VERSION 5.8 ;
BUSBITCHARS "[]" ;
DIVIDERCHAR "/" ;

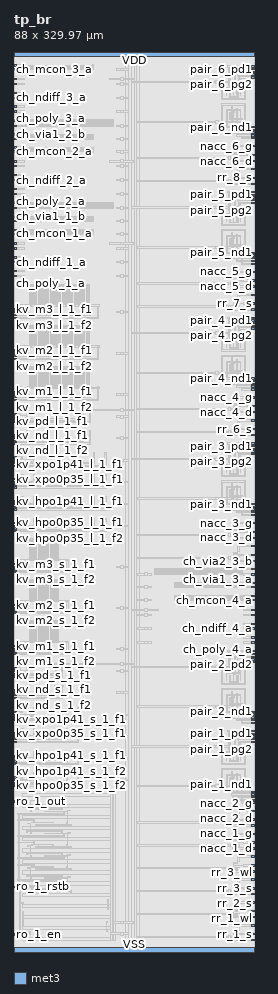
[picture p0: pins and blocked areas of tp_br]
MACRO tp_br
  CLASS BLOCK ;
  FOREIGN tp_br 0 0 ;
  ORIGIN 0 0 ;
  SIZE 88.000 BY 329.970 ;
  SYMMETRY X Y ;
  PIN VDD
    DIRECTION INOUT ;
    USE POWER ;
    PORT
      LAYER met3 ;
        RECT 0.000 328.370 88.000 329.970 ;
    END
  END VDD
  PIN VSS
    DIRECTION INOUT ;
    USE GROUND ;
    PORT
      LAYER met3 ;
        RECT 0.000 0.000 88.000 1.600 ;
    END
  END VSS
  PIN ch_mcon_1_a
    DIRECTION INOUT ;
    USE SIGNAL ;
    PORT
      LAYER met3 ;
        RECT 0.000 263.030 1.000 263.530 ;
    END
  END ch_mcon_1_a
  PIN ch_mcon_1_b
    DIRECTION INOUT ;
    USE SIGNAL ;
    PORT
      LAYER met3 ;
        RECT 0.000 264.530 1.000 265.030 ;
    END
  END ch_mcon_1_b
  PIN ch_mcon_2_a
    DIRECTION INOUT ;
    USE SIGNAL ;
    PORT
      LAYER met3 ;
        RECT 0.000 293.180 1.000 293.680 ;
    END
  END ch_mcon_2_a
  PIN ch_mcon_2_b
    DIRECTION INOUT ;
    USE SIGNAL ;
    PORT
      LAYER met3 ;
        RECT 0.000 294.680 1.000 295.180 ;
    END
  END ch_mcon_2_b
  PIN ch_mcon_3_a
    DIRECTION INOUT ;
    USE SIGNAL ;
    PORT
      LAYER met3 ;
        RECT 0.000 323.330 1.000 323.830 ;
    END
  END ch_mcon_3_a
  PIN ch_mcon_3_b
    DIRECTION INOUT ;
    USE SIGNAL ;
    PORT
      LAYER met3 ;
        RECT 0.000 324.830 1.000 325.330 ;
    END
  END ch_mcon_3_b
  PIN ch_mcon_4_a
    DIRECTION INOUT ;
    USE SIGNAL ;
    PORT
      LAYER met3 ;
        RECT 87.000 128.720 88.000 129.220 ;
    END
  END ch_mcon_4_a
  PIN ch_mcon_4_b
    DIRECTION INOUT ;
    USE SIGNAL ;
    PORT
      LAYER met3 ;
        RECT 87.000 130.220 88.000 130.720 ;
    END
  END ch_mcon_4_b
  PIN ch_ndiff_1_a
    DIRECTION INOUT ;
    USE SIGNAL ;
    PORT
      LAYER met3 ;
        RECT 0.000 252.630 1.000 253.130 ;
    END
  END ch_ndiff_1_a
  PIN ch_ndiff_1_b
    DIRECTION INOUT ;
    USE SIGNAL ;
    PORT
      LAYER met3 ;
        RECT 0.000 254.430 1.000 254.930 ;
    END
  END ch_ndiff_1_b
  PIN ch_ndiff_2_a
    DIRECTION INOUT ;
    USE SIGNAL ;
    PORT
      LAYER met3 ;
        RECT 0.000 282.780 1.000 283.280 ;
    END
  END ch_ndiff_2_a
  PIN ch_ndiff_2_b
    DIRECTION INOUT ;
    USE SIGNAL ;
    PORT
      LAYER met3 ;
        RECT 0.000 284.580 1.000 285.080 ;
    END
  END ch_ndiff_2_b
  PIN ch_ndiff_3_a
    DIRECTION INOUT ;
    USE SIGNAL ;
    PORT
      LAYER met3 ;
        RECT 0.000 312.930 1.000 313.430 ;
    END
  END ch_ndiff_3_a
  PIN ch_ndiff_3_b
    DIRECTION INOUT ;
    USE SIGNAL ;
    PORT
      LAYER met3 ;
        RECT 0.000 314.730 1.000 315.230 ;
    END
  END ch_ndiff_3_b
  PIN ch_ndiff_4_a
    DIRECTION INOUT ;
    USE SIGNAL ;
    PORT
      LAYER met3 ;
        RECT 87.000 118.320 88.000 118.820 ;
    END
  END ch_ndiff_4_a
  PIN ch_ndiff_4_b
    DIRECTION INOUT ;
    USE SIGNAL ;
    PORT
      LAYER met3 ;
        RECT 87.000 120.120 88.000 120.620 ;
    END
  END ch_ndiff_4_b
  PIN ch_pdiff_1_a
    DIRECTION INOUT ;
    USE SIGNAL ;
    PORT
      LAYER met3 ;
        RECT 0.000 257.680 1.000 258.180 ;
    END
  END ch_pdiff_1_a
  PIN ch_pdiff_1_b
    DIRECTION INOUT ;
    USE SIGNAL ;
    PORT
      LAYER met3 ;
        RECT 0.000 259.480 1.000 259.980 ;
    END
  END ch_pdiff_1_b
  PIN ch_pdiff_2_a
    DIRECTION INOUT ;
    USE SIGNAL ;
    PORT
      LAYER met3 ;
        RECT 0.000 287.830 1.000 288.330 ;
    END
  END ch_pdiff_2_a
  PIN ch_pdiff_2_b
    DIRECTION INOUT ;
    USE SIGNAL ;
    PORT
      LAYER met3 ;
        RECT 0.000 289.630 1.000 290.130 ;
    END
  END ch_pdiff_2_b
  PIN ch_pdiff_3_a
    DIRECTION INOUT ;
    USE SIGNAL ;
    PORT
      LAYER met3 ;
        RECT 0.000 317.980 1.000 318.480 ;
    END
  END ch_pdiff_3_a
  PIN ch_pdiff_3_b
    DIRECTION INOUT ;
    USE SIGNAL ;
    PORT
      LAYER met3 ;
        RECT 0.000 319.780 1.000 320.280 ;
    END
  END ch_pdiff_3_b
  PIN ch_pdiff_4_a
    DIRECTION INOUT ;
    USE SIGNAL ;
    PORT
      LAYER met3 ;
        RECT 87.000 123.370 88.000 123.870 ;
    END
  END ch_pdiff_4_a
  PIN ch_pdiff_4_b
    DIRECTION INOUT ;
    USE SIGNAL ;
    PORT
      LAYER met3 ;
        RECT 87.000 125.170 88.000 125.670 ;
    END
  END ch_pdiff_4_b
  PIN ch_poly_1_a
    DIRECTION INOUT ;
    USE SIGNAL ;
    PORT
      LAYER met3 ;
        RECT 0.000 247.580 1.000 248.080 ;
    END
  END ch_poly_1_a
  PIN ch_poly_1_b
    DIRECTION INOUT ;
    USE SIGNAL ;
    PORT
      LAYER met3 ;
        RECT 0.000 249.380 1.000 249.880 ;
    END
  END ch_poly_1_b
  PIN ch_poly_2_a
    DIRECTION INOUT ;
    USE SIGNAL ;
    PORT
      LAYER met3 ;
        RECT 0.000 277.730 1.000 278.230 ;
    END
  END ch_poly_2_a
  PIN ch_poly_2_b
    DIRECTION INOUT ;
    USE SIGNAL ;
    PORT
      LAYER met3 ;
        RECT 0.000 279.530 1.000 280.030 ;
    END
  END ch_poly_2_b
  PIN ch_poly_3_a
    DIRECTION INOUT ;
    USE SIGNAL ;
    PORT
      LAYER met3 ;
        RECT 0.000 307.880 1.000 308.380 ;
    END
  END ch_poly_3_a
  PIN ch_poly_3_b
    DIRECTION INOUT ;
    USE SIGNAL ;
    PORT
      LAYER met3 ;
        RECT 0.000 309.680 1.000 310.180 ;
    END
  END ch_poly_3_b
  PIN ch_poly_4_a
    DIRECTION INOUT ;
    USE SIGNAL ;
    PORT
      LAYER met3 ;
        RECT 87.000 113.270 88.000 113.770 ;
    END
  END ch_poly_4_a
  PIN ch_poly_4_b
    DIRECTION INOUT ;
    USE SIGNAL ;
    PORT
      LAYER met3 ;
        RECT 87.000 115.070 88.000 115.570 ;
    END
  END ch_poly_4_b
  PIN ch_via1_1_a
    DIRECTION INOUT ;
    USE SIGNAL ;
    PORT
      LAYER met3 ;
        RECT 0.000 267.780 1.000 268.280 ;
    END
  END ch_via1_1_a
  PIN ch_via1_1_b
    DIRECTION INOUT ;
    USE SIGNAL ;
    PORT
      LAYER met3 ;
        RECT 0.000 269.280 1.000 269.780 ;
    END
  END ch_via1_1_b
  PIN ch_via1_2_a
    DIRECTION INOUT ;
    USE SIGNAL ;
    PORT
      LAYER met3 ;
        RECT 0.000 297.930 1.000 298.430 ;
    END
  END ch_via1_2_a
  PIN ch_via1_2_b
    DIRECTION INOUT ;
    USE SIGNAL ;
    PORT
      LAYER met3 ;
        RECT 0.000 299.430 1.000 299.930 ;
    END
  END ch_via1_2_b
  PIN ch_via1_3_a
    DIRECTION INOUT ;
    USE SIGNAL ;
    PORT
      LAYER met3 ;
        RECT 87.000 133.470 88.000 133.970 ;
    END
  END ch_via1_3_a
  PIN ch_via1_3_b
    DIRECTION INOUT ;
    USE SIGNAL ;
    PORT
      LAYER met3 ;
        RECT 87.000 134.970 88.000 135.470 ;
    END
  END ch_via1_3_b
  PIN ch_via2_1_a
    DIRECTION INOUT ;
    USE SIGNAL ;
    PORT
      LAYER met3 ;
        RECT 0.000 272.530 1.000 273.030 ;
    END
  END ch_via2_1_a
  PIN ch_via2_1_b
    DIRECTION INOUT ;
    USE SIGNAL ;
    PORT
      LAYER met3 ;
        RECT 0.000 274.480 1.000 274.980 ;
    END
  END ch_via2_1_b
  PIN ch_via2_2_a
    DIRECTION INOUT ;
    USE SIGNAL ;
    PORT
      LAYER met3 ;
        RECT 0.000 302.680 1.000 303.180 ;
    END
  END ch_via2_2_a
  PIN ch_via2_2_b
    DIRECTION INOUT ;
    USE SIGNAL ;
    PORT
      LAYER met3 ;
        RECT 0.000 304.630 1.000 305.130 ;
    END
  END ch_via2_2_b
  PIN ch_via2_3_a
    DIRECTION INOUT ;
    USE SIGNAL ;
    PORT
      LAYER met3 ;
        RECT 87.000 138.220 88.000 138.720 ;
    END
  END ch_via2_3_a
  PIN ch_via2_3_b
    DIRECTION INOUT ;
    USE SIGNAL ;
    PORT
      LAYER met3 ;
        RECT 87.000 140.170 88.000 140.670 ;
    END
  END ch_via2_3_b
  PIN kv_hpo0p35_l_1_f1
    DIRECTION INOUT ;
    USE SIGNAL ;
    PORT
      LAYER met3 ;
        RECT 0.000 157.045 1.000 157.545 ;
    END
  END kv_hpo0p35_l_1_f1
  PIN kv_hpo0p35_l_1_f2
    DIRECTION INOUT ;
    USE SIGNAL ;
    PORT
      LAYER met3 ;
        RECT 0.000 154.045 1.000 154.545 ;
    END
  END kv_hpo0p35_l_1_f2
  PIN kv_hpo0p35_l_1_s1
    DIRECTION INOUT ;
    USE SIGNAL ;
    PORT
      LAYER met3 ;
        RECT 0.000 156.045 1.000 156.545 ;
    END
  END kv_hpo0p35_l_1_s1
  PIN kv_hpo0p35_l_1_s2
    DIRECTION INOUT ;
    USE SIGNAL ;
    PORT
      LAYER met3 ;
        RECT 0.000 155.045 1.000 155.545 ;
    END
  END kv_hpo0p35_l_1_s2
  PIN kv_hpo0p35_s_1_f1
    DIRECTION INOUT ;
    USE SIGNAL ;
    PORT
      LAYER met3 ;
        RECT 0.000 63.760 1.000 64.260 ;
    END
  END kv_hpo0p35_s_1_f1
  PIN kv_hpo0p35_s_1_f2
    DIRECTION INOUT ;
    USE SIGNAL ;
    PORT
      LAYER met3 ;
        RECT 0.000 60.760 1.000 61.260 ;
    END
  END kv_hpo0p35_s_1_f2
  PIN kv_hpo0p35_s_1_s1
    DIRECTION INOUT ;
    USE SIGNAL ;
    PORT
      LAYER met3 ;
        RECT 0.000 62.760 1.000 63.260 ;
    END
  END kv_hpo0p35_s_1_s1
  PIN kv_hpo0p35_s_1_s2
    DIRECTION INOUT ;
    USE SIGNAL ;
    PORT
      LAYER met3 ;
        RECT 0.000 61.760 1.000 62.260 ;
    END
  END kv_hpo0p35_s_1_s2
  PIN kv_hpo1p41_l_1_f1
    DIRECTION INOUT ;
    USE SIGNAL ;
    PORT
      LAYER met3 ;
        RECT 0.000 164.945 1.000 165.445 ;
    END
  END kv_hpo1p41_l_1_f1
  PIN kv_hpo1p41_l_1_f2
    DIRECTION INOUT ;
    USE SIGNAL ;
    PORT
      LAYER met3 ;
        RECT 0.000 161.945 1.000 162.445 ;
    END
  END kv_hpo1p41_l_1_f2
  PIN kv_hpo1p41_l_1_s1
    DIRECTION INOUT ;
    USE SIGNAL ;
    PORT
      LAYER met3 ;
        RECT 0.000 163.945 1.000 164.445 ;
    END
  END kv_hpo1p41_l_1_s1
  PIN kv_hpo1p41_l_1_s2
    DIRECTION INOUT ;
    USE SIGNAL ;
    PORT
      LAYER met3 ;
        RECT 0.000 162.945 1.000 163.445 ;
    END
  END kv_hpo1p41_l_1_s2
  PIN kv_hpo1p41_s_1_f1
    DIRECTION INOUT ;
    USE SIGNAL ;
    PORT
      LAYER met3 ;
        RECT 0.000 71.660 1.000 72.160 ;
    END
  END kv_hpo1p41_s_1_f1
  PIN kv_hpo1p41_s_1_f2
    DIRECTION INOUT ;
    USE SIGNAL ;
    PORT
      LAYER met3 ;
        RECT 0.000 68.660 1.000 69.160 ;
    END
  END kv_hpo1p41_s_1_f2
  PIN kv_hpo1p41_s_1_s1
    DIRECTION INOUT ;
    USE SIGNAL ;
    PORT
      LAYER met3 ;
        RECT 0.000 70.660 1.000 71.160 ;
    END
  END kv_hpo1p41_s_1_s1
  PIN kv_hpo1p41_s_1_s2
    DIRECTION INOUT ;
    USE SIGNAL ;
    PORT
      LAYER met3 ;
        RECT 0.000 69.660 1.000 70.160 ;
    END
  END kv_hpo1p41_s_1_s2
  PIN kv_m1_l_1_f1
    DIRECTION INOUT ;
    USE SIGNAL ;
    PORT
      LAYER met3 ;
        RECT 0.000 205.180 1.000 205.680 ;
    END
  END kv_m1_l_1_f1
  PIN kv_m1_l_1_f2
    DIRECTION INOUT ;
    USE SIGNAL ;
    PORT
      LAYER met3 ;
        RECT 0.000 202.180 1.000 202.680 ;
    END
  END kv_m1_l_1_f2
  PIN kv_m1_l_1_s1
    DIRECTION INOUT ;
    USE SIGNAL ;
    PORT
      LAYER met3 ;
        RECT 0.000 204.180 1.000 204.680 ;
    END
  END kv_m1_l_1_s1
  PIN kv_m1_l_1_s2
    DIRECTION INOUT ;
    USE SIGNAL ;
    PORT
      LAYER met3 ;
        RECT 0.000 203.180 1.000 203.680 ;
    END
  END kv_m1_l_1_s2
  PIN kv_m1_s_1_f1
    DIRECTION INOUT ;
    USE SIGNAL ;
    PORT
      LAYER met3 ;
        RECT 0.000 111.895 1.000 112.395 ;
    END
  END kv_m1_s_1_f1
  PIN kv_m1_s_1_f2
    DIRECTION INOUT ;
    USE SIGNAL ;
    PORT
      LAYER met3 ;
        RECT 0.000 108.895 1.000 109.395 ;
    END
  END kv_m1_s_1_f2
  PIN kv_m1_s_1_s1
    DIRECTION INOUT ;
    USE SIGNAL ;
    PORT
      LAYER met3 ;
        RECT 0.000 110.895 1.000 111.395 ;
    END
  END kv_m1_s_1_s1
  PIN kv_m1_s_1_s2
    DIRECTION INOUT ;
    USE SIGNAL ;
    PORT
      LAYER met3 ;
        RECT 0.000 109.895 1.000 110.395 ;
    END
  END kv_m1_s_1_s2
  PIN kv_m2_l_1_f1
    DIRECTION INOUT ;
    USE SIGNAL ;
    PORT
      LAYER met3 ;
        RECT 0.000 220.230 1.000 220.730 ;
    END
  END kv_m2_l_1_f1
  PIN kv_m2_l_1_f2
    DIRECTION INOUT ;
    USE SIGNAL ;
    PORT
      LAYER met3 ;
        RECT 0.000 217.230 1.000 217.730 ;
    END
  END kv_m2_l_1_f2
  PIN kv_m2_l_1_s1
    DIRECTION INOUT ;
    USE SIGNAL ;
    PORT
      LAYER met3 ;
        RECT 0.000 219.230 1.000 219.730 ;
    END
  END kv_m2_l_1_s1
  PIN kv_m2_l_1_s2
    DIRECTION INOUT ;
    USE SIGNAL ;
    PORT
      LAYER met3 ;
        RECT 0.000 218.230 1.000 218.730 ;
    END
  END kv_m2_l_1_s2
  PIN kv_m2_s_1_f1
    DIRECTION INOUT ;
    USE SIGNAL ;
    PORT
      LAYER met3 ;
        RECT 0.000 126.945 1.000 127.445 ;
    END
  END kv_m2_s_1_f1
  PIN kv_m2_s_1_f2
    DIRECTION INOUT ;
    USE SIGNAL ;
    PORT
      LAYER met3 ;
        RECT 0.000 123.945 1.000 124.445 ;
    END
  END kv_m2_s_1_f2
  PIN kv_m2_s_1_s1
    DIRECTION INOUT ;
    USE SIGNAL ;
    PORT
      LAYER met3 ;
        RECT 0.000 125.945 1.000 126.445 ;
    END
  END kv_m2_s_1_s1
  PIN kv_m2_s_1_s2
    DIRECTION INOUT ;
    USE SIGNAL ;
    PORT
      LAYER met3 ;
        RECT 0.000 124.945 1.000 125.445 ;
    END
  END kv_m2_s_1_s2
  PIN kv_m3_l_1_f1
    DIRECTION INOUT ;
    USE SIGNAL ;
    PORT
      LAYER met3 ;
        RECT 0.000 235.280 1.000 235.780 ;
    END
  END kv_m3_l_1_f1
  PIN kv_m3_l_1_f2
    DIRECTION INOUT ;
    USE SIGNAL ;
    PORT
      LAYER met3 ;
        RECT 0.000 232.280 1.000 232.780 ;
    END
  END kv_m3_l_1_f2
  PIN kv_m3_l_1_s1
    DIRECTION INOUT ;
    USE SIGNAL ;
    PORT
      LAYER met3 ;
        RECT 0.000 234.280 1.000 234.780 ;
    END
  END kv_m3_l_1_s1
  PIN kv_m3_l_1_s2
    DIRECTION INOUT ;
    USE SIGNAL ;
    PORT
      LAYER met3 ;
        RECT 0.000 233.280 1.000 233.780 ;
    END
  END kv_m3_l_1_s2
  PIN kv_m3_s_1_f1
    DIRECTION INOUT ;
    USE SIGNAL ;
    PORT
      LAYER met3 ;
        RECT 0.000 141.995 1.000 142.495 ;
    END
  END kv_m3_s_1_f1
  PIN kv_m3_s_1_f2
    DIRECTION INOUT ;
    USE SIGNAL ;
    PORT
      LAYER met3 ;
        RECT 0.000 138.995 1.000 139.495 ;
    END
  END kv_m3_s_1_f2
  PIN kv_m3_s_1_s1
    DIRECTION INOUT ;
    USE SIGNAL ;
    PORT
      LAYER met3 ;
        RECT 0.000 140.995 1.000 141.495 ;
    END
  END kv_m3_s_1_s1
  PIN kv_m3_s_1_s2
    DIRECTION INOUT ;
    USE SIGNAL ;
    PORT
      LAYER met3 ;
        RECT 0.000 139.995 1.000 140.495 ;
    END
  END kv_m3_s_1_s2
  PIN kv_nd_l_1_f1
    DIRECTION INOUT ;
    USE SIGNAL ;
    PORT
      LAYER met3 ;
        RECT 0.000 189.155 1.000 189.655 ;
    END
  END kv_nd_l_1_f1
  PIN kv_nd_l_1_f2
    DIRECTION INOUT ;
    USE SIGNAL ;
    PORT
      LAYER met3 ;
        RECT 0.000 186.155 1.000 186.655 ;
    END
  END kv_nd_l_1_f2
  PIN kv_nd_l_1_s1
    DIRECTION INOUT ;
    USE SIGNAL ;
    PORT
      LAYER met3 ;
        RECT 0.000 188.155 1.000 188.655 ;
    END
  END kv_nd_l_1_s1
  PIN kv_nd_l_1_s2
    DIRECTION INOUT ;
    USE SIGNAL ;
    PORT
      LAYER met3 ;
        RECT 0.000 187.155 1.000 187.655 ;
    END
  END kv_nd_l_1_s2
  PIN kv_nd_s_1_f1
    DIRECTION INOUT ;
    USE SIGNAL ;
    PORT
      LAYER met3 ;
        RECT 0.000 95.870 1.000 96.370 ;
    END
  END kv_nd_s_1_f1
  PIN kv_nd_s_1_f2
    DIRECTION INOUT ;
    USE SIGNAL ;
    PORT
      LAYER met3 ;
        RECT 0.000 92.870 1.000 93.370 ;
    END
  END kv_nd_s_1_f2
  PIN kv_nd_s_1_s1
    DIRECTION INOUT ;
    USE SIGNAL ;
    PORT
      LAYER met3 ;
        RECT 0.000 94.870 1.000 95.370 ;
    END
  END kv_nd_s_1_s1
  PIN kv_nd_s_1_s2
    DIRECTION INOUT ;
    USE SIGNAL ;
    PORT
      LAYER met3 ;
        RECT 0.000 93.870 1.000 94.370 ;
    END
  END kv_nd_s_1_s2
  PIN kv_pd_l_1_f1
    DIRECTION INOUT ;
    USE SIGNAL ;
    PORT
      LAYER met3 ;
        RECT 0.000 197.030 1.000 197.530 ;
    END
  END kv_pd_l_1_f1
  PIN kv_pd_l_1_f2
    DIRECTION INOUT ;
    USE SIGNAL ;
    PORT
      LAYER met3 ;
        RECT 0.000 194.030 1.000 194.530 ;
    END
  END kv_pd_l_1_f2
  PIN kv_pd_l_1_s1
    DIRECTION INOUT ;
    USE SIGNAL ;
    PORT
      LAYER met3 ;
        RECT 0.000 196.030 1.000 196.530 ;
    END
  END kv_pd_l_1_s1
  PIN kv_pd_l_1_s2
    DIRECTION INOUT ;
    USE SIGNAL ;
    PORT
      LAYER met3 ;
        RECT 0.000 195.030 1.000 195.530 ;
    END
  END kv_pd_l_1_s2
  PIN kv_pd_s_1_f1
    DIRECTION INOUT ;
    USE SIGNAL ;
    PORT
      LAYER met3 ;
        RECT 0.000 103.745 1.000 104.245 ;
    END
  END kv_pd_s_1_f1
  PIN kv_pd_s_1_f2
    DIRECTION INOUT ;
    USE SIGNAL ;
    PORT
      LAYER met3 ;
        RECT 0.000 100.745 1.000 101.245 ;
    END
  END kv_pd_s_1_f2
  PIN kv_pd_s_1_s1
    DIRECTION INOUT ;
    USE SIGNAL ;
    PORT
      LAYER met3 ;
        RECT 0.000 102.745 1.000 103.245 ;
    END
  END kv_pd_s_1_s1
  PIN kv_pd_s_1_s2
    DIRECTION INOUT ;
    USE SIGNAL ;
    PORT
      LAYER met3 ;
        RECT 0.000 101.745 1.000 102.245 ;
    END
  END kv_pd_s_1_s2
  PIN kv_xpo0p35_l_1_f1
    DIRECTION INOUT ;
    USE SIGNAL ;
    PORT
      LAYER met3 ;
        RECT 0.000 173.100 1.000 173.600 ;
    END
  END kv_xpo0p35_l_1_f1
  PIN kv_xpo0p35_l_1_f2
    DIRECTION INOUT ;
    USE SIGNAL ;
    PORT
      LAYER met3 ;
        RECT 0.000 170.100 1.000 170.600 ;
    END
  END kv_xpo0p35_l_1_f2
  PIN kv_xpo0p35_l_1_s1
    DIRECTION INOUT ;
    USE SIGNAL ;
    PORT
      LAYER met3 ;
        RECT 0.000 172.100 1.000 172.600 ;
    END
  END kv_xpo0p35_l_1_s1
  PIN kv_xpo0p35_l_1_s2
    DIRECTION INOUT ;
    USE SIGNAL ;
    PORT
      LAYER met3 ;
        RECT 0.000 171.100 1.000 171.600 ;
    END
  END kv_xpo0p35_l_1_s2
  PIN kv_xpo0p35_s_1_f1
    DIRECTION INOUT ;
    USE SIGNAL ;
    PORT
      LAYER met3 ;
        RECT 0.000 79.815 1.000 80.315 ;
    END
  END kv_xpo0p35_s_1_f1
  PIN kv_xpo0p35_s_1_f2
    DIRECTION INOUT ;
    USE SIGNAL ;
    PORT
      LAYER met3 ;
        RECT 0.000 76.815 1.000 77.315 ;
    END
  END kv_xpo0p35_s_1_f2
  PIN kv_xpo0p35_s_1_s1
    DIRECTION INOUT ;
    USE SIGNAL ;
    PORT
      LAYER met3 ;
        RECT 0.000 78.815 1.000 79.315 ;
    END
  END kv_xpo0p35_s_1_s1
  PIN kv_xpo0p35_s_1_s2
    DIRECTION INOUT ;
    USE SIGNAL ;
    PORT
      LAYER met3 ;
        RECT 0.000 77.815 1.000 78.315 ;
    END
  END kv_xpo0p35_s_1_s2
  PIN kv_xpo1p41_l_1_f1
    DIRECTION INOUT ;
    USE SIGNAL ;
    PORT
      LAYER met3 ;
        RECT 0.000 181.000 1.000 181.500 ;
    END
  END kv_xpo1p41_l_1_f1
  PIN kv_xpo1p41_l_1_f2
    DIRECTION INOUT ;
    USE SIGNAL ;
    PORT
      LAYER met3 ;
        RECT 0.000 178.000 1.000 178.500 ;
    END
  END kv_xpo1p41_l_1_f2
  PIN kv_xpo1p41_l_1_s1
    DIRECTION INOUT ;
    USE SIGNAL ;
    PORT
      LAYER met3 ;
        RECT 0.000 180.000 1.000 180.500 ;
    END
  END kv_xpo1p41_l_1_s1
  PIN kv_xpo1p41_l_1_s2
    DIRECTION INOUT ;
    USE SIGNAL ;
    PORT
      LAYER met3 ;
        RECT 0.000 179.000 1.000 179.500 ;
    END
  END kv_xpo1p41_l_1_s2
  PIN kv_xpo1p41_s_1_f1
    DIRECTION INOUT ;
    USE SIGNAL ;
    PORT
      LAYER met3 ;
        RECT 0.000 87.715 1.000 88.215 ;
    END
  END kv_xpo1p41_s_1_f1
  PIN kv_xpo1p41_s_1_f2
    DIRECTION INOUT ;
    USE SIGNAL ;
    PORT
      LAYER met3 ;
        RECT 0.000 84.715 1.000 85.215 ;
    END
  END kv_xpo1p41_s_1_f2
  PIN kv_xpo1p41_s_1_s1
    DIRECTION INOUT ;
    USE SIGNAL ;
    PORT
      LAYER met3 ;
        RECT 0.000 86.715 1.000 87.215 ;
    END
  END kv_xpo1p41_s_1_s1
  PIN kv_xpo1p41_s_1_s2
    DIRECTION INOUT ;
    USE SIGNAL ;
    PORT
      LAYER met3 ;
        RECT 0.000 85.715 1.000 86.215 ;
    END
  END kv_xpo1p41_s_1_s2
  PIN nacc_1_d
    DIRECTION INOUT ;
    USE SIGNAL ;
    PORT
      LAYER met3 ;
        RECT 87.000 37.700 88.000 38.200 ;
    END
  END nacc_1_d
  PIN nacc_1_g
    DIRECTION INOUT ;
    USE SIGNAL ;
    PORT
      LAYER met3 ;
        RECT 87.000 43.100 88.000 43.600 ;
    END
  END nacc_1_g
  PIN nacc_1_s
    DIRECTION INOUT ;
    USE SIGNAL ;
    PORT
      LAYER met3 ;
        RECT 87.000 39.890 88.000 40.390 ;
    END
  END nacc_1_s
  PIN nacc_2_d
    DIRECTION INOUT ;
    USE SIGNAL ;
    PORT
      LAYER met3 ;
        RECT 87.000 46.100 88.000 46.600 ;
    END
  END nacc_2_d
  PIN nacc_2_g
    DIRECTION INOUT ;
    USE SIGNAL ;
    PORT
      LAYER met3 ;
        RECT 87.000 51.500 88.000 52.000 ;
    END
  END nacc_2_g
  PIN nacc_2_s
    DIRECTION INOUT ;
    USE SIGNAL ;
    PORT
      LAYER met3 ;
        RECT 87.000 48.290 88.000 48.790 ;
    END
  END nacc_2_s
  PIN nacc_3_d
    DIRECTION INOUT ;
    USE SIGNAL ;
    PORT
      LAYER met3 ;
        RECT 87.000 151.570 88.000 152.070 ;
    END
  END nacc_3_d
  PIN nacc_3_g
    DIRECTION INOUT ;
    USE SIGNAL ;
    PORT
      LAYER met3 ;
        RECT 87.000 156.970 88.000 157.470 ;
    END
  END nacc_3_g
  PIN nacc_3_s
    DIRECTION INOUT ;
    USE SIGNAL ;
    PORT
      LAYER met3 ;
        RECT 87.000 153.760 88.000 154.260 ;
    END
  END nacc_3_s
  PIN nacc_4_d
    DIRECTION INOUT ;
    USE SIGNAL ;
    PORT
      LAYER met3 ;
        RECT 87.000 197.630 88.000 198.130 ;
    END
  END nacc_4_d
  PIN nacc_4_g
    DIRECTION INOUT ;
    USE SIGNAL ;
    PORT
      LAYER met3 ;
        RECT 87.000 203.030 88.000 203.530 ;
    END
  END nacc_4_g
  PIN nacc_4_s
    DIRECTION INOUT ;
    USE SIGNAL ;
    PORT
      LAYER met3 ;
        RECT 87.000 199.820 88.000 200.320 ;
    END
  END nacc_4_s
  PIN nacc_5_d
    DIRECTION INOUT ;
    USE SIGNAL ;
    PORT
      LAYER met3 ;
        RECT 87.000 243.690 88.000 244.190 ;
    END
  END nacc_5_d
  PIN nacc_5_g
    DIRECTION INOUT ;
    USE SIGNAL ;
    PORT
      LAYER met3 ;
        RECT 87.000 249.090 88.000 249.590 ;
    END
  END nacc_5_g
  PIN nacc_5_s
    DIRECTION INOUT ;
    USE SIGNAL ;
    PORT
      LAYER met3 ;
        RECT 87.000 245.880 88.000 246.380 ;
    END
  END nacc_5_s
  PIN nacc_6_d
    DIRECTION INOUT ;
    USE SIGNAL ;
    PORT
      LAYER met3 ;
        RECT 87.000 289.750 88.000 290.250 ;
    END
  END nacc_6_d
  PIN nacc_6_g
    DIRECTION INOUT ;
    USE SIGNAL ;
    PORT
      LAYER met3 ;
        RECT 87.000 295.150 88.000 295.650 ;
    END
  END nacc_6_g
  PIN nacc_6_s
    DIRECTION INOUT ;
    USE SIGNAL ;
    PORT
      LAYER met3 ;
        RECT 87.000 291.940 88.000 292.440 ;
    END
  END nacc_6_s
  PIN pair_1_nd1
    DIRECTION INOUT ;
    USE SIGNAL ;
    PORT
      LAYER met3 ;
        RECT 87.000 58.500 88.000 59.000 ;
    END
  END pair_1_nd1
  PIN pair_1_nd2
    DIRECTION INOUT ;
    USE SIGNAL ;
    PORT
      LAYER met3 ;
        RECT 87.000 56.500 88.000 57.000 ;
    END
  END pair_1_nd2
  PIN pair_1_ng1
    DIRECTION INOUT ;
    USE SIGNAL ;
    PORT
      LAYER met3 ;
        RECT 87.000 57.500 88.000 58.000 ;
    END
  END pair_1_ng1
  PIN pair_1_ng2
    DIRECTION INOUT ;
    USE SIGNAL ;
    PORT
      LAYER met3 ;
        RECT 87.000 55.500 88.000 56.000 ;
    END
  END pair_1_ng2
  PIN pair_1_ns
    DIRECTION INOUT ;
    USE SIGNAL ;
    PORT
      LAYER met3 ;
        RECT 87.000 54.500 88.000 55.000 ;
    END
  END pair_1_ns
  PIN pair_1_pd1
    DIRECTION INOUT ;
    USE SIGNAL ;
    PORT
      LAYER met3 ;
        RECT 87.000 79.760 88.000 80.260 ;
    END
  END pair_1_pd1
  PIN pair_1_pd2
    DIRECTION INOUT ;
    USE SIGNAL ;
    PORT
      LAYER met3 ;
        RECT 87.000 78.760 88.000 79.260 ;
    END
  END pair_1_pd2
  PIN pair_1_pg1
    DIRECTION INOUT ;
    USE SIGNAL ;
    PORT
      LAYER met3 ;
        RECT 87.000 80.760 88.000 81.260 ;
    END
  END pair_1_pg1
  PIN pair_1_pg2
    DIRECTION INOUT ;
    USE SIGNAL ;
    PORT
      LAYER met3 ;
        RECT 87.000 76.760 88.000 77.260 ;
    END
  END pair_1_pg2
  PIN pair_1_ps
    DIRECTION INOUT ;
    USE SIGNAL ;
    PORT
      LAYER met3 ;
        RECT 87.000 77.760 88.000 78.260 ;
    END
  END pair_1_ps
  PIN pair_2_nd1
    DIRECTION INOUT ;
    USE SIGNAL ;
    PORT
      LAYER met3 ;
        RECT 87.000 87.760 88.000 88.260 ;
    END
  END pair_2_nd1
  PIN pair_2_nd2
    DIRECTION INOUT ;
    USE SIGNAL ;
    PORT
      LAYER met3 ;
        RECT 87.000 85.760 88.000 86.260 ;
    END
  END pair_2_nd2
  PIN pair_2_ng1
    DIRECTION INOUT ;
    USE SIGNAL ;
    PORT
      LAYER met3 ;
        RECT 87.000 86.760 88.000 87.260 ;
    END
  END pair_2_ng1
  PIN pair_2_ng2
    DIRECTION INOUT ;
    USE SIGNAL ;
    PORT
      LAYER met3 ;
        RECT 87.000 84.760 88.000 85.260 ;
    END
  END pair_2_ng2
  PIN pair_2_ns
    DIRECTION INOUT ;
    USE SIGNAL ;
    PORT
      LAYER met3 ;
        RECT 87.000 83.760 88.000 84.260 ;
    END
  END pair_2_ns
  PIN pair_2_pd1
    DIRECTION INOUT ;
    USE SIGNAL ;
    PORT
      LAYER met3 ;
        RECT 87.000 109.020 88.000 109.520 ;
    END
  END pair_2_pd1
  PIN pair_2_pd2
    DIRECTION INOUT ;
    USE SIGNAL ;
    PORT
      LAYER met3 ;
        RECT 87.000 108.020 88.000 108.520 ;
    END
  END pair_2_pd2
  PIN pair_2_pg1
    DIRECTION INOUT ;
    USE SIGNAL ;
    PORT
      LAYER met3 ;
        RECT 87.000 110.020 88.000 110.520 ;
    END
  END pair_2_pg1
  PIN pair_2_pg2
    DIRECTION INOUT ;
    USE SIGNAL ;
    PORT
      LAYER met3 ;
        RECT 87.000 106.020 88.000 106.520 ;
    END
  END pair_2_pg2
  PIN pair_2_ps
    DIRECTION INOUT ;
    USE SIGNAL ;
    PORT
      LAYER met3 ;
        RECT 87.000 107.020 88.000 107.520 ;
    END
  END pair_2_ps
  PIN pair_3_nd1
    DIRECTION INOUT ;
    USE SIGNAL ;
    PORT
      LAYER met3 ;
        RECT 87.000 163.970 88.000 164.470 ;
    END
  END pair_3_nd1
  PIN pair_3_nd2
    DIRECTION INOUT ;
    USE SIGNAL ;
    PORT
      LAYER met3 ;
        RECT 87.000 161.970 88.000 162.470 ;
    END
  END pair_3_nd2
  PIN pair_3_ng1
    DIRECTION INOUT ;
    USE SIGNAL ;
    PORT
      LAYER met3 ;
        RECT 87.000 162.970 88.000 163.470 ;
    END
  END pair_3_ng1
  PIN pair_3_ng2
    DIRECTION INOUT ;
    USE SIGNAL ;
    PORT
      LAYER met3 ;
        RECT 87.000 160.970 88.000 161.470 ;
    END
  END pair_3_ng2
  PIN pair_3_ns
    DIRECTION INOUT ;
    USE SIGNAL ;
    PORT
      LAYER met3 ;
        RECT 87.000 159.970 88.000 160.470 ;
    END
  END pair_3_ns
  PIN pair_3_pd1
    DIRECTION INOUT ;
    USE SIGNAL ;
    PORT
      LAYER met3 ;
        RECT 87.000 185.230 88.000 185.730 ;
    END
  END pair_3_pd1
  PIN pair_3_pd2
    DIRECTION INOUT ;
    USE SIGNAL ;
    PORT
      LAYER met3 ;
        RECT 87.000 184.230 88.000 184.730 ;
    END
  END pair_3_pd2
  PIN pair_3_pg1
    DIRECTION INOUT ;
    USE SIGNAL ;
    PORT
      LAYER met3 ;
        RECT 87.000 186.230 88.000 186.730 ;
    END
  END pair_3_pg1
  PIN pair_3_pg2
    DIRECTION INOUT ;
    USE SIGNAL ;
    PORT
      LAYER met3 ;
        RECT 87.000 182.230 88.000 182.730 ;
    END
  END pair_3_pg2
  PIN pair_3_ps
    DIRECTION INOUT ;
    USE SIGNAL ;
    PORT
      LAYER met3 ;
        RECT 87.000 183.230 88.000 183.730 ;
    END
  END pair_3_ps
  PIN pair_4_nd1
    DIRECTION INOUT ;
    USE SIGNAL ;
    PORT
      LAYER met3 ;
        RECT 87.000 210.030 88.000 210.530 ;
    END
  END pair_4_nd1
  PIN pair_4_nd2
    DIRECTION INOUT ;
    USE SIGNAL ;
    PORT
      LAYER met3 ;
        RECT 87.000 208.030 88.000 208.530 ;
    END
  END pair_4_nd2
  PIN pair_4_ng1
    DIRECTION INOUT ;
    USE SIGNAL ;
    PORT
      LAYER met3 ;
        RECT 87.000 209.030 88.000 209.530 ;
    END
  END pair_4_ng1
  PIN pair_4_ng2
    DIRECTION INOUT ;
    USE SIGNAL ;
    PORT
      LAYER met3 ;
        RECT 87.000 207.030 88.000 207.530 ;
    END
  END pair_4_ng2
  PIN pair_4_ns
    DIRECTION INOUT ;
    USE SIGNAL ;
    PORT
      LAYER met3 ;
        RECT 87.000 206.030 88.000 206.530 ;
    END
  END pair_4_ns
  PIN pair_4_pd1
    DIRECTION INOUT ;
    USE SIGNAL ;
    PORT
      LAYER met3 ;
        RECT 87.000 231.290 88.000 231.790 ;
    END
  END pair_4_pd1
  PIN pair_4_pd2
    DIRECTION INOUT ;
    USE SIGNAL ;
    PORT
      LAYER met3 ;
        RECT 87.000 230.290 88.000 230.790 ;
    END
  END pair_4_pd2
  PIN pair_4_pg1
    DIRECTION INOUT ;
    USE SIGNAL ;
    PORT
      LAYER met3 ;
        RECT 87.000 232.290 88.000 232.790 ;
    END
  END pair_4_pg1
  PIN pair_4_pg2
    DIRECTION INOUT ;
    USE SIGNAL ;
    PORT
      LAYER met3 ;
        RECT 87.000 228.290 88.000 228.790 ;
    END
  END pair_4_pg2
  PIN pair_4_ps
    DIRECTION INOUT ;
    USE SIGNAL ;
    PORT
      LAYER met3 ;
        RECT 87.000 229.290 88.000 229.790 ;
    END
  END pair_4_ps
  PIN pair_5_nd1
    DIRECTION INOUT ;
    USE SIGNAL ;
    PORT
      LAYER met3 ;
        RECT 87.000 256.090 88.000 256.590 ;
    END
  END pair_5_nd1
  PIN pair_5_nd2
    DIRECTION INOUT ;
    USE SIGNAL ;
    PORT
      LAYER met3 ;
        RECT 87.000 254.090 88.000 254.590 ;
    END
  END pair_5_nd2
  PIN pair_5_ng1
    DIRECTION INOUT ;
    USE SIGNAL ;
    PORT
      LAYER met3 ;
        RECT 87.000 255.090 88.000 255.590 ;
    END
  END pair_5_ng1
  PIN pair_5_ng2
    DIRECTION INOUT ;
    USE SIGNAL ;
    PORT
      LAYER met3 ;
        RECT 87.000 253.090 88.000 253.590 ;
    END
  END pair_5_ng2
  PIN pair_5_ns
    DIRECTION INOUT ;
    USE SIGNAL ;
    PORT
      LAYER met3 ;
        RECT 87.000 252.090 88.000 252.590 ;
    END
  END pair_5_ns
  PIN pair_5_pd1
    DIRECTION INOUT ;
    USE SIGNAL ;
    PORT
      LAYER met3 ;
        RECT 87.000 277.350 88.000 277.850 ;
    END
  END pair_5_pd1
  PIN pair_5_pd2
    DIRECTION INOUT ;
    USE SIGNAL ;
    PORT
      LAYER met3 ;
        RECT 87.000 276.350 88.000 276.850 ;
    END
  END pair_5_pd2
  PIN pair_5_pg1
    DIRECTION INOUT ;
    USE SIGNAL ;
    PORT
      LAYER met3 ;
        RECT 87.000 278.350 88.000 278.850 ;
    END
  END pair_5_pg1
  PIN pair_5_pg2
    DIRECTION INOUT ;
    USE SIGNAL ;
    PORT
      LAYER met3 ;
        RECT 87.000 274.350 88.000 274.850 ;
    END
  END pair_5_pg2
  PIN pair_5_ps
    DIRECTION INOUT ;
    USE SIGNAL ;
    PORT
      LAYER met3 ;
        RECT 87.000 275.350 88.000 275.850 ;
    END
  END pair_5_ps
  PIN pair_6_nd1
    DIRECTION INOUT ;
    USE SIGNAL ;
    PORT
      LAYER met3 ;
        RECT 87.000 302.150 88.000 302.650 ;
    END
  END pair_6_nd1
  PIN pair_6_nd2
    DIRECTION INOUT ;
    USE SIGNAL ;
    PORT
      LAYER met3 ;
        RECT 87.000 300.150 88.000 300.650 ;
    END
  END pair_6_nd2
  PIN pair_6_ng1
    DIRECTION INOUT ;
    USE SIGNAL ;
    PORT
      LAYER met3 ;
        RECT 87.000 301.150 88.000 301.650 ;
    END
  END pair_6_ng1
  PIN pair_6_ng2
    DIRECTION INOUT ;
    USE SIGNAL ;
    PORT
      LAYER met3 ;
        RECT 87.000 299.150 88.000 299.650 ;
    END
  END pair_6_ng2
  PIN pair_6_ns
    DIRECTION INOUT ;
    USE SIGNAL ;
    PORT
      LAYER met3 ;
        RECT 87.000 298.150 88.000 298.650 ;
    END
  END pair_6_ns
  PIN pair_6_pd1
    DIRECTION INOUT ;
    USE SIGNAL ;
    PORT
      LAYER met3 ;
        RECT 87.000 323.410 88.000 323.910 ;
    END
  END pair_6_pd1
  PIN pair_6_pd2
    DIRECTION INOUT ;
    USE SIGNAL ;
    PORT
      LAYER met3 ;
        RECT 87.000 322.410 88.000 322.910 ;
    END
  END pair_6_pd2
  PIN pair_6_pg1
    DIRECTION INOUT ;
    USE SIGNAL ;
    PORT
      LAYER met3 ;
        RECT 87.000 324.410 88.000 324.910 ;
    END
  END pair_6_pg1
  PIN pair_6_pg2
    DIRECTION INOUT ;
    USE SIGNAL ;
    PORT
      LAYER met3 ;
        RECT 87.000 320.410 88.000 320.910 ;
    END
  END pair_6_pg2
  PIN pair_6_ps
    DIRECTION INOUT ;
    USE SIGNAL ;
    PORT
      LAYER met3 ;
        RECT 87.000 321.410 88.000 321.910 ;
    END
  END pair_6_ps
  PIN ro_1_en
    DIRECTION INOUT ;
    USE SIGNAL ;
    PORT
      LAYER met3 ;
        RECT 0.000 6.215 1.000 6.715 ;
    END
  END ro_1_en
  PIN ro_1_out
    DIRECTION INOUT ;
    USE SIGNAL ;
    PORT
      LAYER met3 ;
        RECT 0.000 54.980 1.000 55.480 ;
    END
  END ro_1_out
  PIN ro_1_rstb
    DIRECTION INOUT ;
    USE SIGNAL ;
    PORT
      LAYER met3 ;
        RECT 0.000 23.605 1.000 24.105 ;
    END
  END ro_1_rstb
  PIN rr_1_s
    DIRECTION INOUT ;
    USE SIGNAL ;
    PORT
      LAYER met3 ;
        RECT 87.000 6.290 88.000 6.790 ;
    END
  END rr_1_s
  PIN rr_1_te
    DIRECTION INOUT ;
    USE SIGNAL ;
    PORT
      LAYER met3 ;
        RECT 87.000 4.100 88.000 4.600 ;
    END
  END rr_1_te
  PIN rr_1_wl
    DIRECTION INOUT ;
    USE SIGNAL ;
    PORT
      LAYER met3 ;
        RECT 87.000 9.500 88.000 10.000 ;
    END
  END rr_1_wl
  PIN rr_2_s
    DIRECTION INOUT ;
    USE SIGNAL ;
    PORT
      LAYER met3 ;
        RECT 87.000 14.690 88.000 15.190 ;
    END
  END rr_2_s
  PIN rr_2_te
    DIRECTION INOUT ;
    USE SIGNAL ;
    PORT
      LAYER met3 ;
        RECT 87.000 12.500 88.000 13.000 ;
    END
  END rr_2_te
  PIN rr_2_wl
    DIRECTION INOUT ;
    USE SIGNAL ;
    PORT
      LAYER met3 ;
        RECT 87.000 17.900 88.000 18.400 ;
    END
  END rr_2_wl
  PIN rr_3_s
    DIRECTION INOUT ;
    USE SIGNAL ;
    PORT
      LAYER met3 ;
        RECT 87.000 23.090 88.000 23.590 ;
    END
  END rr_3_s
  PIN rr_3_te
    DIRECTION INOUT ;
    USE SIGNAL ;
    PORT
      LAYER met3 ;
        RECT 87.000 20.900 88.000 21.400 ;
    END
  END rr_3_te
  PIN rr_3_wl
    DIRECTION INOUT ;
    USE SIGNAL ;
    PORT
      LAYER met3 ;
        RECT 87.000 26.300 88.000 26.800 ;
    END
  END rr_3_wl
  PIN rr_4_s
    DIRECTION INOUT ;
    USE SIGNAL ;
    PORT
      LAYER met3 ;
        RECT 87.000 31.490 88.000 31.990 ;
    END
  END rr_4_s
  PIN rr_4_te
    DIRECTION INOUT ;
    USE SIGNAL ;
    PORT
      LAYER met3 ;
        RECT 87.000 29.300 88.000 29.800 ;
    END
  END rr_4_te
  PIN rr_4_wl
    DIRECTION INOUT ;
    USE SIGNAL ;
    PORT
      LAYER met3 ;
        RECT 87.000 34.700 88.000 35.200 ;
    END
  END rr_4_wl
  PIN rr_5_s
    DIRECTION INOUT ;
    USE SIGNAL ;
    PORT
      LAYER met3 ;
        RECT 87.000 145.360 88.000 145.860 ;
    END
  END rr_5_s
  PIN rr_5_te
    DIRECTION INOUT ;
    USE SIGNAL ;
    PORT
      LAYER met3 ;
        RECT 87.000 143.170 88.000 143.670 ;
    END
  END rr_5_te
  PIN rr_5_wl
    DIRECTION INOUT ;
    USE SIGNAL ;
    PORT
      LAYER met3 ;
        RECT 87.000 148.570 88.000 149.070 ;
    END
  END rr_5_wl
  PIN rr_6_s
    DIRECTION INOUT ;
    USE SIGNAL ;
    PORT
      LAYER met3 ;
        RECT 87.000 191.420 88.000 191.920 ;
    END
  END rr_6_s
  PIN rr_6_te
    DIRECTION INOUT ;
    USE SIGNAL ;
    PORT
      LAYER met3 ;
        RECT 87.000 189.230 88.000 189.730 ;
    END
  END rr_6_te
  PIN rr_6_wl
    DIRECTION INOUT ;
    USE SIGNAL ;
    PORT
      LAYER met3 ;
        RECT 87.000 194.630 88.000 195.130 ;
    END
  END rr_6_wl
  PIN rr_7_s
    DIRECTION INOUT ;
    USE SIGNAL ;
    PORT
      LAYER met3 ;
        RECT 87.000 237.480 88.000 237.980 ;
    END
  END rr_7_s
  PIN rr_7_te
    DIRECTION INOUT ;
    USE SIGNAL ;
    PORT
      LAYER met3 ;
        RECT 87.000 235.290 88.000 235.790 ;
    END
  END rr_7_te
  PIN rr_7_wl
    DIRECTION INOUT ;
    USE SIGNAL ;
    PORT
      LAYER met3 ;
        RECT 87.000 240.690 88.000 241.190 ;
    END
  END rr_7_wl
  PIN rr_8_s
    DIRECTION INOUT ;
    USE SIGNAL ;
    PORT
      LAYER met3 ;
        RECT 87.000 283.540 88.000 284.040 ;
    END
  END rr_8_s
  PIN rr_8_te
    DIRECTION INOUT ;
    USE SIGNAL ;
    PORT
      LAYER met3 ;
        RECT 87.000 281.350 88.000 281.850 ;
    END
  END rr_8_te
  PIN rr_8_wl
    DIRECTION INOUT ;
    USE SIGNAL ;
    PORT
      LAYER met3 ;
        RECT 87.000 286.750 88.000 287.250 ;
    END
  END rr_8_wl
  OBS
    LAYER li1 ;
      RECT 0.000 0.000 88.000 329.970 ;
    LAYER met1 ;
      RECT 79.095 167.250 79.325 169.440 ;
      RECT 81.675 167.250 81.905 169.440 ;
      RECT 79.095 166.910 83.665 167.250 ;
      RECT 80.335 169.610 80.665 169.950 ;
      RECT 80.385 167.440 80.615 169.610 ;
      RECT 77.805 167.440 78.035 170.210 ;
      RECT 77.805 170.210 82.965 170.550 ;
      RECT 82.965 167.440 83.195 170.550 ;
      RECT 81.530 170.730 81.870 171.070 ;
      RECT 79.730 171.380 80.070 171.720 ;
      RECT 76.000 166.470 76.340 172.280 ;
      RECT 76.000 172.280 84.660 172.780 ;
      RECT 84.660 166.470 85.000 172.780 ;
      RECT 76.000 165.970 85.000 166.470 ;
      RECT 79.095 175.510 79.325 177.700 ;
      RECT 81.675 175.510 81.905 177.700 ;
      RECT 79.095 175.170 82.465 175.510 ;
      RECT 80.385 175.700 80.615 177.870 ;
      RECT 80.385 177.870 81.265 178.210 ;
      RECT 77.805 175.700 78.035 178.470 ;
      RECT 77.805 178.470 82.965 178.810 ;
      RECT 82.965 175.700 83.195 178.810 ;
      RECT 82.730 178.990 83.070 179.330 ;
      RECT 78.530 179.640 78.870 179.980 ;
      RECT 76.000 174.730 76.340 180.540 ;
      RECT 76.000 180.540 84.660 181.040 ;
      RECT 84.660 174.730 85.000 181.040 ;
      RECT 76.000 174.230 85.000 174.730 ;
      RECT 81.000 190.240 82.820 190.990 ;
      RECT 80.980 191.525 84.390 191.815 ;
      RECT 84.710 191.525 84.800 191.815 ;
      RECT 84.390 191.510 84.710 191.830 ;
      RECT 80.335 192.325 82.055 192.615 ;
      RECT 82.150 193.040 82.470 193.360 ;
      RECT 81.000 198.640 82.820 199.390 ;
      RECT 80.980 199.925 84.390 200.215 ;
      RECT 84.710 199.925 84.800 200.215 ;
      RECT 84.390 199.910 84.710 200.230 ;
      RECT 80.335 200.725 82.055 201.015 ;
      RECT 82.150 201.440 82.470 201.760 ;
      RECT 79.095 213.310 79.325 215.500 ;
      RECT 81.675 213.310 81.905 215.500 ;
      RECT 79.095 212.970 83.665 213.310 ;
      RECT 80.335 215.670 80.665 216.010 ;
      RECT 80.385 213.500 80.615 215.670 ;
      RECT 77.805 213.500 78.035 216.270 ;
      RECT 77.805 216.270 82.965 216.610 ;
      RECT 82.965 213.500 83.195 216.610 ;
      RECT 81.530 216.790 81.870 217.130 ;
      RECT 79.730 217.440 80.070 217.780 ;
      RECT 76.000 212.530 76.340 218.340 ;
      RECT 76.000 218.340 84.660 218.840 ;
      RECT 84.660 212.530 85.000 218.840 ;
      RECT 76.000 212.030 85.000 212.530 ;
      RECT 79.095 221.570 79.325 223.760 ;
      RECT 81.675 221.570 81.905 223.760 ;
      RECT 79.095 221.230 82.465 221.570 ;
      RECT 80.385 221.760 80.615 223.930 ;
      RECT 80.385 223.930 81.265 224.270 ;
      RECT 77.805 221.760 78.035 224.530 ;
      RECT 77.805 224.530 82.965 224.870 ;
      RECT 82.965 221.760 83.195 224.870 ;
      RECT 82.730 225.050 83.070 225.390 ;
      RECT 78.530 225.700 78.870 226.040 ;
      RECT 76.000 220.790 76.340 226.600 ;
      RECT 76.000 226.600 84.660 227.100 ;
      RECT 84.660 220.790 85.000 227.100 ;
      RECT 76.000 220.290 85.000 220.790 ;
      RECT 81.000 236.300 82.820 237.050 ;
      RECT 80.980 237.585 84.390 237.875 ;
      RECT 84.710 237.585 84.800 237.875 ;
      RECT 84.390 237.570 84.710 237.890 ;
      RECT 80.335 238.385 82.055 238.675 ;
      RECT 82.150 239.100 82.470 239.420 ;
      RECT 81.000 244.700 82.820 245.450 ;
      RECT 80.980 245.985 84.390 246.275 ;
      RECT 84.710 245.985 84.800 246.275 ;
      RECT 84.390 245.970 84.710 246.290 ;
      RECT 80.335 246.785 82.055 247.075 ;
      RECT 82.150 247.500 82.470 247.820 ;
      RECT 79.095 259.370 79.325 261.560 ;
      RECT 81.675 259.370 81.905 261.560 ;
      RECT 79.095 259.030 83.665 259.370 ;
      RECT 80.335 261.730 80.665 262.070 ;
      RECT 80.385 259.560 80.615 261.730 ;
      RECT 77.805 259.560 78.035 262.330 ;
      RECT 77.805 262.330 82.965 262.670 ;
      RECT 82.965 259.560 83.195 262.670 ;
      RECT 81.530 262.850 81.870 263.190 ;
      RECT 79.730 263.500 80.070 263.840 ;
      RECT 76.000 258.590 76.340 264.400 ;
      RECT 76.000 264.400 84.660 264.900 ;
      RECT 84.660 258.590 85.000 264.900 ;
      RECT 76.000 258.090 85.000 258.590 ;
      RECT 79.095 267.630 79.325 269.820 ;
      RECT 81.675 267.630 81.905 269.820 ;
      RECT 79.095 267.290 82.465 267.630 ;
      RECT 80.385 267.820 80.615 269.990 ;
      RECT 80.385 269.990 81.265 270.330 ;
      RECT 77.805 267.820 78.035 270.590 ;
      RECT 77.805 270.590 82.965 270.930 ;
      RECT 82.965 267.820 83.195 270.930 ;
      RECT 82.730 271.110 83.070 271.450 ;
      RECT 78.530 271.760 78.870 272.100 ;
      RECT 76.000 266.850 76.340 272.660 ;
      RECT 76.000 272.660 84.660 273.160 ;
      RECT 84.660 266.850 85.000 273.160 ;
      RECT 76.000 266.350 85.000 266.850 ;
      RECT 81.000 282.360 82.820 283.110 ;
      RECT 80.980 283.645 84.390 283.935 ;
      RECT 84.710 283.645 84.800 283.935 ;
      RECT 84.390 283.630 84.710 283.950 ;
      RECT 80.335 284.445 82.055 284.735 ;
      RECT 82.150 285.160 82.470 285.480 ;
      RECT 81.000 290.760 82.820 291.510 ;
      RECT 80.980 292.045 84.390 292.335 ;
      RECT 84.710 292.045 84.800 292.335 ;
      RECT 84.390 292.030 84.710 292.350 ;
      RECT 80.335 292.845 82.055 293.135 ;
      RECT 82.150 293.560 82.470 293.880 ;
      RECT 79.095 305.430 79.325 307.620 ;
      RECT 81.675 305.430 81.905 307.620 ;
      RECT 79.095 305.090 83.665 305.430 ;
      RECT 80.335 307.790 80.665 308.130 ;
      RECT 80.385 305.620 80.615 307.790 ;
      RECT 77.805 305.620 78.035 308.390 ;
      RECT 77.805 308.390 82.965 308.730 ;
      RECT 82.965 305.620 83.195 308.730 ;
      RECT 81.530 308.910 81.870 309.250 ;
      RECT 79.730 309.560 80.070 309.900 ;
      RECT 76.000 304.650 76.340 310.460 ;
      RECT 76.000 310.460 84.660 310.960 ;
      RECT 84.660 304.650 85.000 310.960 ;
      RECT 76.000 304.150 85.000 304.650 ;
      RECT 79.095 313.690 79.325 315.880 ;
      RECT 81.675 313.690 81.905 315.880 ;
      RECT 79.095 313.350 82.465 313.690 ;
      RECT 80.385 313.880 80.615 316.050 ;
      RECT 80.385 316.050 81.265 316.390 ;
      RECT 77.805 313.880 78.035 316.650 ;
      RECT 77.805 316.650 82.965 316.990 ;
      RECT 82.965 313.880 83.195 316.990 ;
      RECT 82.730 317.170 83.070 317.510 ;
      RECT 78.530 317.820 78.870 318.160 ;
      RECT 76.000 312.910 76.340 318.720 ;
      RECT 76.000 318.720 84.660 319.220 ;
      RECT 84.660 312.910 85.000 319.220 ;
      RECT 76.000 312.410 85.000 312.910 ;
      RECT 21.855 263.165 22.645 263.395 ;
      RECT 21.855 263.665 22.645 263.895 ;
      RECT 21.855 264.165 22.645 264.395 ;
      RECT 21.855 264.665 22.645 264.895 ;
      RECT 5.600 207.130 6.000 214.330 ;
      RECT 2.000 206.730 6.000 207.130 ;
      RECT 7.200 207.130 7.600 214.330 ;
      RECT 6.400 206.730 7.600 207.130 ;
      RECT 8.800 207.130 9.200 214.330 ;
      RECT 8.000 206.730 9.200 207.130 ;
      RECT 10.400 207.130 10.800 214.330 ;
      RECT 9.600 206.730 10.800 207.130 ;
      RECT 12.000 207.130 12.400 214.330 ;
      RECT 11.200 206.730 12.400 207.130 ;
      RECT 13.600 207.130 14.000 214.330 ;
      RECT 12.800 206.730 14.000 207.130 ;
      RECT 15.200 207.130 15.600 214.330 ;
      RECT 14.400 206.730 15.600 207.130 ;
      RECT 16.800 207.130 17.200 214.330 ;
      RECT 16.000 206.730 17.200 207.130 ;
      RECT 18.400 207.130 18.800 214.330 ;
      RECT 17.600 206.730 18.800 207.130 ;
      RECT 20.000 207.130 20.400 214.330 ;
      RECT 19.200 206.730 20.400 207.130 ;
      RECT 21.600 207.130 22.000 214.330 ;
      RECT 20.800 206.730 22.000 207.130 ;
      RECT 23.200 207.130 23.600 214.330 ;
      RECT 22.400 206.730 23.600 207.130 ;
      RECT 24.800 207.130 25.200 214.330 ;
      RECT 24.000 206.730 25.200 207.130 ;
      RECT 26.400 207.130 26.800 214.330 ;
      RECT 25.600 206.730 26.800 207.130 ;
      RECT 5.600 214.330 6.800 214.730 ;
      RECT 6.400 207.130 6.800 214.330 ;
      RECT 7.200 214.330 8.400 214.730 ;
      RECT 8.000 207.130 8.400 214.330 ;
      RECT 8.800 214.330 10.000 214.730 ;
      RECT 9.600 207.130 10.000 214.330 ;
      RECT 10.400 214.330 11.600 214.730 ;
      RECT 11.200 207.130 11.600 214.330 ;
      RECT 12.000 214.330 13.200 214.730 ;
      RECT 12.800 207.130 13.200 214.330 ;
      RECT 13.600 214.330 14.800 214.730 ;
      RECT 14.400 207.130 14.800 214.330 ;
      RECT 15.200 214.330 16.400 214.730 ;
      RECT 16.000 207.130 16.400 214.330 ;
      RECT 16.800 214.330 18.000 214.730 ;
      RECT 17.600 207.130 18.000 214.330 ;
      RECT 18.400 214.330 19.600 214.730 ;
      RECT 19.200 207.130 19.600 214.330 ;
      RECT 20.000 214.330 21.200 214.730 ;
      RECT 20.800 207.130 21.200 214.330 ;
      RECT 21.600 214.330 22.800 214.730 ;
      RECT 22.400 207.130 22.800 214.330 ;
      RECT 23.200 214.330 24.400 214.730 ;
      RECT 24.000 207.130 24.400 214.330 ;
      RECT 24.800 214.330 26.000 214.730 ;
      RECT 25.600 207.130 26.000 214.330 ;
      RECT 27.200 206.730 31.200 207.130 ;
      RECT 26.400 214.330 27.600 214.730 ;
      RECT 27.200 207.130 27.600 214.330 ;
      RECT 21.855 293.315 22.645 293.545 ;
      RECT 21.855 293.815 22.645 294.045 ;
      RECT 21.855 294.315 22.645 294.545 ;
      RECT 21.855 294.815 22.645 295.045 ;
      RECT 21.855 323.465 22.645 323.695 ;
      RECT 21.855 323.965 22.645 324.195 ;
      RECT 21.855 324.465 22.645 324.695 ;
      RECT 21.855 324.965 22.645 325.195 ;
      RECT 37.840 287.920 38.160 288.240 ;
      RECT 35.240 289.720 35.560 290.040 ;
      RECT 37.840 293.270 38.160 293.590 ;
      RECT 37.840 298.020 38.160 298.340 ;
      RECT 37.840 302.770 38.160 303.090 ;
      RECT 37.840 307.970 38.160 308.290 ;
      RECT 37.840 313.020 38.160 313.340 ;
      RECT 37.840 318.070 38.160 318.390 ;
      RECT 35.240 319.870 35.560 320.190 ;
      RECT 37.840 323.420 38.160 323.740 ;
      RECT 23.855 293.815 24.645 294.045 ;
      RECT 24.855 293.815 25.645 294.045 ;
      RECT 25.855 293.815 26.645 294.045 ;
      RECT 26.855 293.815 27.645 294.045 ;
      RECT 27.855 293.815 28.645 294.045 ;
      RECT 28.885 293.285 29.115 294.075 ;
      RECT 22.855 294.315 23.645 294.545 ;
      RECT 23.855 294.315 24.645 294.545 ;
      RECT 24.855 294.315 25.645 294.545 ;
      RECT 25.855 294.315 26.645 294.545 ;
      RECT 26.855 294.315 27.645 294.545 ;
      RECT 27.855 294.315 28.645 294.545 ;
      RECT 22.855 294.815 23.645 295.045 ;
      RECT 23.855 294.815 24.645 295.045 ;
      RECT 24.855 294.815 25.645 295.045 ;
      RECT 25.855 294.815 26.645 295.045 ;
      RECT 26.855 294.815 27.645 295.045 ;
      RECT 27.855 294.815 28.645 295.045 ;
      RECT 28.885 294.285 29.115 295.075 ;
      RECT 22.340 298.050 23.160 298.310 ;
      RECT 23.340 298.050 24.160 298.310 ;
      RECT 24.340 298.050 25.160 298.310 ;
      RECT 25.340 298.050 26.160 298.310 ;
      RECT 26.340 298.050 27.160 298.310 ;
      RECT 27.340 298.050 28.160 298.310 ;
      RECT 28.340 298.050 29.160 298.310 ;
      RECT 23.855 293.315 24.645 293.545 ;
      RECT 22.340 298.550 23.160 298.810 ;
      RECT 23.340 298.550 24.160 298.810 ;
      RECT 24.340 298.550 25.160 298.810 ;
      RECT 25.340 298.550 26.160 298.810 ;
      RECT 26.340 298.550 27.160 298.810 ;
      RECT 27.340 298.550 28.160 298.810 ;
      RECT 28.340 298.550 29.160 298.810 ;
      RECT 22.340 299.050 23.160 299.310 ;
      RECT 23.340 299.050 24.160 299.310 ;
      RECT 24.340 299.050 25.160 299.310 ;
      RECT 25.340 299.050 26.160 299.310 ;
      RECT 26.340 299.050 27.160 299.310 ;
      RECT 27.340 299.050 28.160 299.310 ;
      RECT 28.340 299.050 29.160 299.310 ;
      RECT 22.340 299.550 23.160 299.810 ;
      RECT 23.340 299.550 24.160 299.810 ;
      RECT 24.340 299.550 25.160 299.810 ;
      RECT 25.340 299.550 26.160 299.810 ;
      RECT 26.340 299.550 27.160 299.810 ;
      RECT 27.340 299.550 28.160 299.810 ;
      RECT 28.340 299.550 29.160 299.810 ;
      RECT 24.855 293.315 25.645 293.545 ;
      RECT 25.855 293.315 26.645 293.545 ;
      RECT 26.855 293.315 27.645 293.545 ;
      RECT 27.855 293.315 28.645 293.545 ;
      RECT 22.855 293.315 23.645 293.545 ;
      RECT 22.855 323.465 23.645 323.695 ;
      RECT 23.855 323.465 24.645 323.695 ;
      RECT 24.855 323.465 25.645 323.695 ;
      RECT 25.855 323.465 26.645 323.695 ;
      RECT 26.855 323.465 27.645 323.695 ;
      RECT 27.855 323.465 28.645 323.695 ;
      RECT 22.855 293.815 23.645 294.045 ;
      RECT 22.855 323.965 23.645 324.195 ;
      RECT 23.855 323.965 24.645 324.195 ;
      RECT 24.855 323.965 25.645 324.195 ;
      RECT 25.855 323.965 26.645 324.195 ;
      RECT 26.855 323.965 27.645 324.195 ;
      RECT 27.855 323.965 28.645 324.195 ;
      RECT 28.885 323.435 29.115 324.225 ;
      RECT 22.855 324.465 23.645 324.695 ;
      RECT 23.855 324.465 24.645 324.695 ;
      RECT 24.855 324.465 25.645 324.695 ;
      RECT 25.855 324.465 26.645 324.695 ;
      RECT 26.855 324.465 27.645 324.695 ;
      RECT 27.855 324.465 28.645 324.695 ;
      RECT 22.855 324.965 23.645 325.195 ;
      RECT 23.855 324.965 24.645 325.195 ;
      RECT 24.855 324.965 25.645 325.195 ;
      RECT 25.855 324.965 26.645 325.195 ;
      RECT 26.855 324.965 27.645 325.195 ;
      RECT 27.855 324.965 28.645 325.195 ;
      RECT 28.885 324.435 29.115 325.225 ;
      RECT 27.340 268.900 28.160 269.160 ;
      RECT 28.340 268.900 29.160 269.160 ;
      RECT 22.340 269.400 23.160 269.660 ;
      RECT 23.340 269.400 24.160 269.660 ;
      RECT 24.340 269.400 25.160 269.660 ;
      RECT 25.340 269.400 26.160 269.660 ;
      RECT 26.340 269.400 27.160 269.660 ;
      RECT 27.340 269.400 28.160 269.660 ;
      RECT 28.340 269.400 29.160 269.660 ;
      RECT 22.855 263.165 23.645 263.395 ;
      RECT 23.855 263.665 24.645 263.895 ;
      RECT 24.855 263.665 25.645 263.895 ;
      RECT 23.855 263.165 24.645 263.395 ;
      RECT 25.855 263.665 26.645 263.895 ;
      RECT 26.855 263.665 27.645 263.895 ;
      RECT 27.855 263.665 28.645 263.895 ;
      RECT 28.885 263.135 29.115 263.925 ;
      RECT 22.855 264.165 23.645 264.395 ;
      RECT 23.855 264.165 24.645 264.395 ;
      RECT 24.855 264.165 25.645 264.395 ;
      RECT 24.855 263.165 25.645 263.395 ;
      RECT 25.855 264.165 26.645 264.395 ;
      RECT 26.855 264.165 27.645 264.395 ;
      RECT 27.855 264.165 28.645 264.395 ;
      RECT 22.855 264.665 23.645 264.895 ;
      RECT 27.855 263.165 28.645 263.395 ;
      RECT 23.855 264.665 24.645 264.895 ;
      RECT 24.855 264.665 25.645 264.895 ;
      RECT 25.855 264.665 26.645 264.895 ;
      RECT 25.855 263.165 26.645 263.395 ;
      RECT 26.855 264.665 27.645 264.895 ;
      RECT 27.855 264.665 28.645 264.895 ;
      RECT 28.885 264.135 29.115 264.925 ;
      RECT 22.340 267.900 23.160 268.160 ;
      RECT 23.340 267.900 24.160 268.160 ;
      RECT 24.340 267.900 25.160 268.160 ;
      RECT 26.855 263.165 27.645 263.395 ;
      RECT 25.340 267.900 26.160 268.160 ;
      RECT 26.340 267.900 27.160 268.160 ;
      RECT 27.340 267.900 28.160 268.160 ;
      RECT 28.340 267.900 29.160 268.160 ;
      RECT 22.340 268.400 23.160 268.660 ;
      RECT 23.340 268.400 24.160 268.660 ;
      RECT 24.340 268.400 25.160 268.660 ;
      RECT 25.340 268.400 26.160 268.660 ;
      RECT 26.340 268.400 27.160 268.660 ;
      RECT 22.855 263.665 23.645 263.895 ;
      RECT 27.340 268.400 28.160 268.660 ;
      RECT 28.340 268.400 29.160 268.660 ;
      RECT 22.340 268.900 23.160 269.160 ;
      RECT 23.340 268.900 24.160 269.160 ;
      RECT 24.340 268.900 25.160 269.160 ;
      RECT 25.340 268.900 26.160 269.160 ;
      RECT 26.340 268.900 27.160 269.160 ;
      RECT 37.840 282.870 38.160 283.190 ;
      RECT 37.840 252.720 38.160 253.040 ;
      RECT 37.840 267.870 38.160 268.190 ;
      RECT 37.840 257.770 38.160 258.090 ;
      RECT 37.840 263.120 38.160 263.440 ;
      RECT 35.240 259.570 35.560 259.890 ;
      RECT 37.840 272.620 38.160 272.940 ;
      RECT 37.840 277.820 38.160 278.140 ;
      RECT 37.840 247.670 38.160 247.990 ;
      RECT 11.340 268.900 12.160 269.160 ;
      RECT 11.340 269.400 12.160 269.660 ;
      RECT 11.340 298.050 12.160 298.310 ;
      RECT 11.340 298.550 12.160 298.810 ;
      RECT 11.340 299.050 12.160 299.310 ;
      RECT 11.340 267.900 12.160 268.160 ;
      RECT 11.340 299.550 12.160 299.810 ;
      RECT 11.340 268.400 12.160 268.660 ;
      RECT 16.855 293.815 17.645 294.045 ;
      RECT 16.855 294.315 17.645 294.545 ;
      RECT 16.855 294.815 17.645 295.045 ;
      RECT 16.340 298.050 17.160 298.310 ;
      RECT 16.340 298.550 17.160 298.810 ;
      RECT 16.340 299.050 17.160 299.310 ;
      RECT 16.340 299.550 17.160 299.810 ;
      RECT 16.855 323.465 17.645 323.695 ;
      RECT 16.855 293.315 17.645 293.545 ;
      RECT 16.855 323.965 17.645 324.195 ;
      RECT 16.855 324.465 17.645 324.695 ;
      RECT 16.855 324.965 17.645 325.195 ;
      RECT 17.855 323.465 18.645 323.695 ;
      RECT 18.855 323.465 19.645 323.695 ;
      RECT 17.855 323.965 18.645 324.195 ;
      RECT 18.855 323.965 19.645 324.195 ;
      RECT 19.855 323.965 20.645 324.195 ;
      RECT 20.855 323.965 21.645 324.195 ;
      RECT 19.855 323.465 20.645 323.695 ;
      RECT 17.855 324.465 18.645 324.695 ;
      RECT 18.855 324.465 19.645 324.695 ;
      RECT 19.855 324.465 20.645 324.695 ;
      RECT 20.855 324.465 21.645 324.695 ;
      RECT 20.855 323.465 21.645 323.695 ;
      RECT 17.855 324.965 18.645 325.195 ;
      RECT 18.855 324.965 19.645 325.195 ;
      RECT 19.855 324.965 20.645 325.195 ;
      RECT 20.855 324.965 21.645 325.195 ;
      RECT 11.855 324.465 12.645 324.695 ;
      RECT 12.855 324.465 13.645 324.695 ;
      RECT 13.855 324.465 14.645 324.695 ;
      RECT 14.855 324.465 15.645 324.695 ;
      RECT 15.855 324.465 16.645 324.695 ;
      RECT 11.855 323.965 12.645 324.195 ;
      RECT 12.855 323.965 13.645 324.195 ;
      RECT 13.855 323.965 14.645 324.195 ;
      RECT 14.855 323.965 15.645 324.195 ;
      RECT 15.855 323.965 16.645 324.195 ;
      RECT 11.855 324.965 12.645 325.195 ;
      RECT 12.855 324.965 13.645 325.195 ;
      RECT 13.855 324.965 14.645 325.195 ;
      RECT 14.855 324.965 15.645 325.195 ;
      RECT 15.855 324.965 16.645 325.195 ;
      RECT 12.855 323.465 13.645 323.695 ;
      RECT 13.855 323.465 14.645 323.695 ;
      RECT 14.855 323.465 15.645 323.695 ;
      RECT 15.855 323.465 16.645 323.695 ;
      RECT 11.855 323.465 12.645 323.695 ;
      RECT 11.855 294.815 12.645 295.045 ;
      RECT 12.855 294.815 13.645 295.045 ;
      RECT 13.855 294.815 14.645 295.045 ;
      RECT 14.855 294.815 15.645 295.045 ;
      RECT 15.855 294.815 16.645 295.045 ;
      RECT 13.855 293.815 14.645 294.045 ;
      RECT 11.855 293.315 12.645 293.545 ;
      RECT 12.340 298.050 13.160 298.310 ;
      RECT 13.340 298.050 14.160 298.310 ;
      RECT 14.340 298.050 15.160 298.310 ;
      RECT 15.340 298.050 16.160 298.310 ;
      RECT 14.855 293.815 15.645 294.045 ;
      RECT 12.855 293.315 13.645 293.545 ;
      RECT 12.340 298.550 13.160 298.810 ;
      RECT 13.340 298.550 14.160 298.810 ;
      RECT 14.340 298.550 15.160 298.810 ;
      RECT 15.340 298.550 16.160 298.810 ;
      RECT 15.855 293.815 16.645 294.045 ;
      RECT 13.855 293.315 14.645 293.545 ;
      RECT 12.340 299.050 13.160 299.310 ;
      RECT 13.340 299.050 14.160 299.310 ;
      RECT 14.340 299.050 15.160 299.310 ;
      RECT 15.340 299.050 16.160 299.310 ;
      RECT 11.855 293.815 12.645 294.045 ;
      RECT 14.855 293.315 15.645 293.545 ;
      RECT 15.855 293.315 16.645 293.545 ;
      RECT 12.340 299.550 13.160 299.810 ;
      RECT 13.340 299.550 14.160 299.810 ;
      RECT 14.340 299.550 15.160 299.810 ;
      RECT 15.340 299.550 16.160 299.810 ;
      RECT 11.855 294.315 12.645 294.545 ;
      RECT 12.855 294.315 13.645 294.545 ;
      RECT 13.855 294.315 14.645 294.545 ;
      RECT 14.855 294.315 15.645 294.545 ;
      RECT 15.855 294.315 16.645 294.545 ;
      RECT 12.855 293.815 13.645 294.045 ;
      RECT 20.855 293.315 21.645 293.545 ;
      RECT 17.855 293.315 18.645 293.545 ;
      RECT 18.855 293.315 19.645 293.545 ;
      RECT 17.340 298.550 18.160 298.810 ;
      RECT 18.340 298.550 19.160 298.810 ;
      RECT 19.340 298.550 20.160 298.810 ;
      RECT 20.340 298.550 21.160 298.810 ;
      RECT 21.340 298.550 22.160 298.810 ;
      RECT 17.855 294.815 18.645 295.045 ;
      RECT 18.855 294.815 19.645 295.045 ;
      RECT 19.855 294.815 20.645 295.045 ;
      RECT 20.855 294.815 21.645 295.045 ;
      RECT 17.855 293.815 18.645 294.045 ;
      RECT 18.855 293.815 19.645 294.045 ;
      RECT 17.340 299.050 18.160 299.310 ;
      RECT 18.340 299.050 19.160 299.310 ;
      RECT 19.340 299.050 20.160 299.310 ;
      RECT 20.340 299.050 21.160 299.310 ;
      RECT 21.340 299.050 22.160 299.310 ;
      RECT 17.855 294.315 18.645 294.545 ;
      RECT 18.855 294.315 19.645 294.545 ;
      RECT 19.855 294.315 20.645 294.545 ;
      RECT 20.855 294.315 21.645 294.545 ;
      RECT 17.340 298.050 18.160 298.310 ;
      RECT 18.340 298.050 19.160 298.310 ;
      RECT 19.340 298.050 20.160 298.310 ;
      RECT 17.340 299.550 18.160 299.810 ;
      RECT 18.340 299.550 19.160 299.810 ;
      RECT 19.340 299.550 20.160 299.810 ;
      RECT 20.340 299.550 21.160 299.810 ;
      RECT 21.340 299.550 22.160 299.810 ;
      RECT 20.340 298.050 21.160 298.310 ;
      RECT 21.340 298.050 22.160 298.310 ;
      RECT 19.855 293.815 20.645 294.045 ;
      RECT 20.855 293.815 21.645 294.045 ;
      RECT 19.855 293.315 20.645 293.545 ;
      RECT 3.660 294.815 4.645 295.045 ;
      RECT 3.340 294.770 3.660 295.090 ;
      RECT 4.340 298.050 5.160 298.310 ;
      RECT 4.340 299.550 5.160 299.810 ;
      RECT 5.340 299.550 6.160 299.810 ;
      RECT 6.340 299.550 7.160 299.810 ;
      RECT 7.340 299.550 8.160 299.810 ;
      RECT 8.340 299.550 9.160 299.810 ;
      RECT 9.340 299.550 10.160 299.810 ;
      RECT 10.340 299.550 11.160 299.810 ;
      RECT 5.340 298.050 6.160 298.310 ;
      RECT 6.340 298.050 7.160 298.310 ;
      RECT 7.340 298.050 8.160 298.310 ;
      RECT 8.340 298.050 9.160 298.310 ;
      RECT 9.340 298.050 10.160 298.310 ;
      RECT 10.340 298.050 11.160 298.310 ;
      RECT 7.855 294.315 8.645 294.545 ;
      RECT 8.855 294.315 9.645 294.545 ;
      RECT 9.855 294.315 10.645 294.545 ;
      RECT 10.855 294.315 11.645 294.545 ;
      RECT 4.855 293.815 5.645 294.045 ;
      RECT 3.340 307.970 3.660 308.290 ;
      RECT 3.340 309.770 3.660 310.090 ;
      RECT 3.340 313.020 3.660 313.340 ;
      RECT 3.340 314.820 3.660 315.140 ;
      RECT 3.340 318.070 3.660 318.390 ;
      RECT 3.340 319.870 3.660 320.190 ;
      RECT 4.855 323.465 5.645 323.695 ;
      RECT 5.855 323.465 6.645 323.695 ;
      RECT 6.855 323.465 7.645 323.695 ;
      RECT 7.855 323.465 8.645 323.695 ;
      RECT 8.855 323.465 9.645 323.695 ;
      RECT 9.855 323.465 10.645 323.695 ;
      RECT 10.855 323.465 11.645 323.695 ;
      RECT 5.855 293.815 6.645 294.045 ;
      RECT 6.855 293.815 7.645 294.045 ;
      RECT 7.855 293.815 8.645 294.045 ;
      RECT 8.855 293.815 9.645 294.045 ;
      RECT 9.855 293.815 10.645 294.045 ;
      RECT 10.855 293.815 11.645 294.045 ;
      RECT 4.340 298.550 5.160 298.810 ;
      RECT 5.340 298.550 6.160 298.810 ;
      RECT 6.340 298.550 7.160 298.810 ;
      RECT 7.340 298.550 8.160 298.810 ;
      RECT 3.660 323.465 4.645 323.695 ;
      RECT 3.340 323.420 3.660 323.740 ;
      RECT 8.340 298.550 9.160 298.810 ;
      RECT 4.855 323.965 5.645 324.195 ;
      RECT 5.855 323.965 6.645 324.195 ;
      RECT 6.855 323.965 7.645 324.195 ;
      RECT 7.855 323.965 8.645 324.195 ;
      RECT 8.855 323.965 9.645 324.195 ;
      RECT 9.855 323.965 10.645 324.195 ;
      RECT 10.855 323.965 11.645 324.195 ;
      RECT 9.340 298.550 10.160 298.810 ;
      RECT 10.340 298.550 11.160 298.810 ;
      RECT 3.340 289.720 3.660 290.040 ;
      RECT 4.855 293.315 5.645 293.545 ;
      RECT 5.855 293.315 6.645 293.545 ;
      RECT 4.385 293.785 4.615 294.575 ;
      RECT 4.855 294.815 5.645 295.045 ;
      RECT 5.855 294.815 6.645 295.045 ;
      RECT 6.855 294.815 7.645 295.045 ;
      RECT 7.855 294.815 8.645 295.045 ;
      RECT 4.855 324.465 5.645 324.695 ;
      RECT 5.855 324.465 6.645 324.695 ;
      RECT 6.855 324.465 7.645 324.695 ;
      RECT 7.855 324.465 8.645 324.695 ;
      RECT 8.855 324.465 9.645 324.695 ;
      RECT 9.855 324.465 10.645 324.695 ;
      RECT 10.855 324.465 11.645 324.695 ;
      RECT 8.855 294.815 9.645 295.045 ;
      RECT 9.855 294.815 10.645 295.045 ;
      RECT 10.855 294.815 11.645 295.045 ;
      RECT 4.340 299.050 5.160 299.310 ;
      RECT 5.340 299.050 6.160 299.310 ;
      RECT 6.340 299.050 7.160 299.310 ;
      RECT 7.340 299.050 8.160 299.310 ;
      RECT 8.340 299.050 9.160 299.310 ;
      RECT 9.340 299.050 10.160 299.310 ;
      RECT 10.340 299.050 11.160 299.310 ;
      RECT 4.385 323.935 4.615 324.725 ;
      RECT 4.855 324.965 5.645 325.195 ;
      RECT 5.855 324.965 6.645 325.195 ;
      RECT 6.855 324.965 7.645 325.195 ;
      RECT 7.855 324.965 8.645 325.195 ;
      RECT 8.855 324.965 9.645 325.195 ;
      RECT 9.855 324.965 10.645 325.195 ;
      RECT 10.855 324.965 11.645 325.195 ;
      RECT 6.855 293.315 7.645 293.545 ;
      RECT 7.855 293.315 8.645 293.545 ;
      RECT 8.855 293.315 9.645 293.545 ;
      RECT 9.855 293.315 10.645 293.545 ;
      RECT 10.855 293.315 11.645 293.545 ;
      RECT 3.340 287.920 3.660 288.240 ;
      RECT 3.660 293.315 4.645 293.545 ;
      RECT 3.340 293.270 3.660 293.590 ;
      RECT 4.855 294.315 5.645 294.545 ;
      RECT 5.855 294.315 6.645 294.545 ;
      RECT 6.855 294.315 7.645 294.545 ;
      RECT 3.660 324.965 4.645 325.195 ;
      RECT 3.340 324.920 3.660 325.240 ;
      RECT 6.855 264.165 7.645 264.395 ;
      RECT 4.340 268.400 5.160 268.660 ;
      RECT 5.340 268.400 6.160 268.660 ;
      RECT 6.340 268.400 7.160 268.660 ;
      RECT 7.340 268.400 8.160 268.660 ;
      RECT 8.340 268.400 9.160 268.660 ;
      RECT 9.340 268.400 10.160 268.660 ;
      RECT 10.340 268.400 11.160 268.660 ;
      RECT 7.855 264.165 8.645 264.395 ;
      RECT 3.340 259.570 3.660 259.890 ;
      RECT 3.340 254.520 3.660 254.840 ;
      RECT 4.855 263.165 5.645 263.395 ;
      RECT 5.855 263.165 6.645 263.395 ;
      RECT 10.340 267.900 11.160 268.160 ;
      RECT 6.855 263.165 7.645 263.395 ;
      RECT 3.660 263.165 4.645 263.395 ;
      RECT 3.340 263.120 3.660 263.440 ;
      RECT 7.855 263.165 8.645 263.395 ;
      RECT 4.855 263.665 5.645 263.895 ;
      RECT 3.340 257.770 3.660 258.090 ;
      RECT 3.340 252.720 3.660 253.040 ;
      RECT 4.385 263.635 4.615 264.425 ;
      RECT 4.855 264.665 5.645 264.895 ;
      RECT 5.855 264.665 6.645 264.895 ;
      RECT 8.855 264.165 9.645 264.395 ;
      RECT 9.855 264.165 10.645 264.395 ;
      RECT 10.855 264.165 11.645 264.395 ;
      RECT 3.340 277.820 3.660 278.140 ;
      RECT 3.340 279.620 3.660 279.940 ;
      RECT 3.340 282.870 3.660 283.190 ;
      RECT 3.340 284.670 3.660 284.990 ;
      RECT 8.855 263.165 9.645 263.395 ;
      RECT 9.855 263.165 10.645 263.395 ;
      RECT 10.855 263.165 11.645 263.395 ;
      RECT 5.855 263.665 6.645 263.895 ;
      RECT 6.855 263.665 7.645 263.895 ;
      RECT 7.855 263.665 8.645 263.895 ;
      RECT 4.340 269.400 5.160 269.660 ;
      RECT 8.855 263.665 9.645 263.895 ;
      RECT 5.340 269.400 6.160 269.660 ;
      RECT 6.340 269.400 7.160 269.660 ;
      RECT 9.855 263.665 10.645 263.895 ;
      RECT 3.660 264.665 4.645 264.895 ;
      RECT 3.340 264.620 3.660 264.940 ;
      RECT 3.340 247.670 3.660 247.990 ;
      RECT 10.855 263.665 11.645 263.895 ;
      RECT 4.340 267.900 5.160 268.160 ;
      RECT 3.340 249.470 3.660 249.790 ;
      RECT 5.340 267.900 6.160 268.160 ;
      RECT 6.340 267.900 7.160 268.160 ;
      RECT 7.340 267.900 8.160 268.160 ;
      RECT 8.340 267.900 9.160 268.160 ;
      RECT 9.340 267.900 10.160 268.160 ;
      RECT 7.340 269.400 8.160 269.660 ;
      RECT 8.340 269.400 9.160 269.660 ;
      RECT 9.340 269.400 10.160 269.660 ;
      RECT 10.340 269.400 11.160 269.660 ;
      RECT 6.855 264.665 7.645 264.895 ;
      RECT 7.855 264.665 8.645 264.895 ;
      RECT 8.855 264.665 9.645 264.895 ;
      RECT 9.855 264.665 10.645 264.895 ;
      RECT 10.855 264.665 11.645 264.895 ;
      RECT 10.340 268.900 11.160 269.160 ;
      RECT 4.855 264.165 5.645 264.395 ;
      RECT 4.340 268.900 5.160 269.160 ;
      RECT 5.340 268.900 6.160 269.160 ;
      RECT 6.340 268.900 7.160 269.160 ;
      RECT 7.340 268.900 8.160 269.160 ;
      RECT 8.340 268.900 9.160 269.160 ;
      RECT 9.340 268.900 10.160 269.160 ;
      RECT 5.855 264.165 6.645 264.395 ;
      RECT 15.340 267.900 16.160 268.160 ;
      RECT 16.340 267.900 17.160 268.160 ;
      RECT 17.340 268.900 18.160 269.160 ;
      RECT 18.340 268.900 19.160 269.160 ;
      RECT 11.855 264.665 12.645 264.895 ;
      RECT 12.855 264.665 13.645 264.895 ;
      RECT 12.855 264.165 13.645 264.395 ;
      RECT 19.340 268.900 20.160 269.160 ;
      RECT 20.340 268.900 21.160 269.160 ;
      RECT 13.855 264.165 14.645 264.395 ;
      RECT 21.340 268.900 22.160 269.160 ;
      RECT 14.855 264.165 15.645 264.395 ;
      RECT 20.855 263.665 21.645 263.895 ;
      RECT 12.340 269.400 13.160 269.660 ;
      RECT 13.340 269.400 14.160 269.660 ;
      RECT 14.340 269.400 15.160 269.660 ;
      RECT 15.340 269.400 16.160 269.660 ;
      RECT 18.855 263.165 19.645 263.395 ;
      RECT 19.855 263.165 20.645 263.395 ;
      RECT 20.855 263.165 21.645 263.395 ;
      RECT 17.340 267.900 18.160 268.160 ;
      RECT 12.340 268.400 13.160 268.660 ;
      RECT 13.340 268.400 14.160 268.660 ;
      RECT 14.340 268.400 15.160 268.660 ;
      RECT 15.340 268.400 16.160 268.660 ;
      RECT 16.340 268.400 17.160 268.660 ;
      RECT 17.340 268.400 18.160 268.660 ;
      RECT 18.340 268.400 19.160 268.660 ;
      RECT 19.340 268.400 20.160 268.660 ;
      RECT 18.340 267.900 19.160 268.160 ;
      RECT 19.340 267.900 20.160 268.160 ;
      RECT 20.340 267.900 21.160 268.160 ;
      RECT 21.340 267.900 22.160 268.160 ;
      RECT 16.340 269.400 17.160 269.660 ;
      RECT 17.340 269.400 18.160 269.660 ;
      RECT 18.340 269.400 19.160 269.660 ;
      RECT 19.340 269.400 20.160 269.660 ;
      RECT 13.855 264.665 14.645 264.895 ;
      RECT 14.855 264.665 15.645 264.895 ;
      RECT 15.855 264.665 16.645 264.895 ;
      RECT 16.855 264.665 17.645 264.895 ;
      RECT 17.855 264.665 18.645 264.895 ;
      RECT 18.855 264.665 19.645 264.895 ;
      RECT 19.855 264.665 20.645 264.895 ;
      RECT 20.855 264.665 21.645 264.895 ;
      RECT 11.855 263.665 12.645 263.895 ;
      RECT 20.340 268.400 21.160 268.660 ;
      RECT 21.340 268.400 22.160 268.660 ;
      RECT 13.855 263.665 14.645 263.895 ;
      RECT 14.855 263.665 15.645 263.895 ;
      RECT 15.855 263.665 16.645 263.895 ;
      RECT 16.855 263.665 17.645 263.895 ;
      RECT 17.855 263.665 18.645 263.895 ;
      RECT 20.340 269.400 21.160 269.660 ;
      RECT 21.340 269.400 22.160 269.660 ;
      RECT 12.855 263.665 13.645 263.895 ;
      RECT 14.855 263.165 15.645 263.395 ;
      RECT 15.855 263.165 16.645 263.395 ;
      RECT 12.340 268.900 13.160 269.160 ;
      RECT 13.340 268.900 14.160 269.160 ;
      RECT 14.340 268.900 15.160 269.160 ;
      RECT 11.855 263.165 12.645 263.395 ;
      RECT 15.855 264.165 16.645 264.395 ;
      RECT 16.855 264.165 17.645 264.395 ;
      RECT 17.855 264.165 18.645 264.395 ;
      RECT 18.855 264.165 19.645 264.395 ;
      RECT 19.855 264.165 20.645 264.395 ;
      RECT 20.855 264.165 21.645 264.395 ;
      RECT 16.855 263.165 17.645 263.395 ;
      RECT 12.855 263.165 13.645 263.395 ;
      RECT 17.855 263.165 18.645 263.395 ;
      RECT 18.855 263.665 19.645 263.895 ;
      RECT 19.855 263.665 20.645 263.895 ;
      RECT 13.855 263.165 14.645 263.395 ;
      RECT 15.340 268.900 16.160 269.160 ;
      RECT 16.340 268.900 17.160 269.160 ;
      RECT 11.855 264.165 12.645 264.395 ;
      RECT 12.340 267.900 13.160 268.160 ;
      RECT 13.340 267.900 14.160 268.160 ;
      RECT 14.340 267.900 15.160 268.160 ;
      RECT 4.590 198.620 4.910 198.940 ;
      RECT 2.920 174.690 3.240 175.010 ;
      RECT 2.920 182.590 3.240 182.910 ;
      RECT 7.080 182.590 7.400 182.910 ;
      RECT 2.920 166.535 3.240 166.855 ;
      RECT 2.090 190.745 2.410 191.065 ;
      RECT 2.090 198.620 2.410 198.940 ;
      RECT 4.590 190.745 4.910 191.065 ;
      RECT 7.080 166.535 7.400 166.855 ;
      RECT 7.080 174.690 7.400 175.010 ;
      RECT 29.140 198.620 29.460 198.940 ;
      RECT 37.840 204.270 38.160 204.590 ;
      RECT 37.840 234.370 38.160 234.690 ;
      RECT 29.240 174.690 29.560 175.010 ;
      RECT 37.840 219.320 38.160 219.640 ;
      RECT 25.090 190.745 25.410 191.065 ;
      RECT 33.400 174.690 33.720 175.010 ;
      RECT 29.240 166.535 29.560 166.855 ;
      RECT 37.840 196.120 38.160 196.440 ;
      RECT 37.840 188.245 38.160 188.565 ;
      RECT 29.240 182.590 29.560 182.910 ;
      RECT 37.840 180.090 38.160 180.410 ;
      RECT 37.840 172.190 38.160 172.510 ;
      RECT 33.400 166.535 33.720 166.855 ;
      RECT 33.400 182.590 33.720 182.910 ;
      RECT 25.090 198.620 25.410 198.940 ;
      RECT 27.590 198.620 27.910 198.940 ;
      RECT 27.590 190.745 27.910 191.065 ;
      RECT 3.000 48.870 37.300 50.120 ;
      RECT 3.000 52.940 37.300 54.190 ;
      RECT 3.000 57.010 37.300 58.260 ;
      RECT 3.000 4.100 37.300 5.350 ;
      RECT 3.000 8.170 37.300 9.420 ;
      RECT 3.000 12.240 37.300 13.490 ;
      RECT 3.000 16.310 37.300 17.560 ;
      RECT 3.000 20.380 37.300 21.630 ;
      RECT 3.000 24.450 37.300 25.700 ;
      RECT 3.000 28.520 37.300 29.770 ;
      RECT 3.000 32.590 37.300 33.840 ;
      RECT 3.000 36.660 37.300 37.910 ;
      RECT 3.000 40.730 37.300 41.980 ;
      RECT 3.000 44.800 37.300 46.050 ;
      RECT 37.840 86.805 38.160 87.125 ;
      RECT 23.400 89.305 23.720 89.625 ;
      RECT 37.840 94.960 38.160 95.280 ;
      RECT 37.840 102.835 38.160 103.155 ;
      RECT 37.840 110.985 38.160 111.305 ;
      RECT 37.840 126.035 38.160 126.355 ;
      RECT 37.840 141.085 38.160 141.405 ;
      RECT 37.840 156.135 38.160 156.455 ;
      RECT 29.240 158.635 29.560 158.955 ;
      RECT 33.400 158.635 33.720 158.955 ;
      RECT 37.840 164.035 38.160 164.355 ;
      RECT 7.080 158.635 7.400 158.955 ;
      RECT 15.090 97.460 15.410 97.780 ;
      RECT 17.590 97.460 17.910 97.780 ;
      RECT 19.240 89.305 19.560 89.625 ;
      RECT 2.090 105.335 2.410 105.655 ;
      RECT 4.590 105.335 4.910 105.655 ;
      RECT 15.090 105.335 15.410 105.655 ;
      RECT 17.590 105.335 17.910 105.655 ;
      RECT 19.140 105.335 19.460 105.655 ;
      RECT 2.920 89.305 3.240 89.625 ;
      RECT 5.600 113.845 6.000 121.045 ;
      RECT 2.000 113.445 6.000 113.845 ;
      RECT 7.200 113.845 7.600 121.045 ;
      RECT 6.400 113.445 7.600 113.845 ;
      RECT 8.800 113.845 9.200 121.045 ;
      RECT 8.000 113.445 9.200 113.845 ;
      RECT 10.400 113.845 10.800 121.045 ;
      RECT 9.600 113.445 10.800 113.845 ;
      RECT 12.000 113.845 12.400 121.045 ;
      RECT 11.200 113.445 12.400 113.845 ;
      RECT 13.600 113.845 14.000 121.045 ;
      RECT 12.800 113.445 14.000 113.845 ;
      RECT 15.200 113.845 15.600 121.045 ;
      RECT 14.400 113.445 15.600 113.845 ;
      RECT 5.600 121.045 6.800 121.445 ;
      RECT 6.400 113.845 6.800 121.045 ;
      RECT 7.200 121.045 8.400 121.445 ;
      RECT 8.000 113.845 8.400 121.045 ;
      RECT 8.800 121.045 10.000 121.445 ;
      RECT 9.600 113.845 10.000 121.045 ;
      RECT 10.400 121.045 11.600 121.445 ;
      RECT 11.200 113.845 11.600 121.045 ;
      RECT 12.000 121.045 13.200 121.445 ;
      RECT 12.800 113.845 13.200 121.045 ;
      RECT 13.600 121.045 14.800 121.445 ;
      RECT 14.400 113.845 14.800 121.045 ;
      RECT 16.000 113.445 20.000 113.845 ;
      RECT 15.200 121.045 16.400 121.445 ;
      RECT 16.000 113.845 16.400 121.045 ;
      RECT 7.080 89.305 7.400 89.625 ;
      RECT 2.090 97.460 2.410 97.780 ;
      RECT 4.590 97.460 4.910 97.780 ;
      RECT 2.920 158.635 3.240 158.955 ;
      RECT 2.920 81.405 3.240 81.725 ;
      RECT 7.080 81.405 7.400 81.725 ;
      RECT 19.240 81.405 19.560 81.725 ;
      RECT 19.400 47.215 19.720 47.535 ;
      RECT 18.130 50.555 18.420 51.275 ;
      RECT 11.255 51.415 11.545 51.460 ;
      RECT 16.535 51.415 16.825 51.460 ;
      RECT 11.255 51.600 11.545 51.645 ;
      RECT 16.535 51.600 16.825 51.645 ;
      RECT 11.255 51.460 18.935 51.600 ;
      RECT 18.935 51.415 19.225 51.645 ;
      RECT 5.960 51.455 6.280 51.775 ;
      RECT 20.355 51.705 20.675 52.025 ;
      RECT 4.540 52.205 4.860 52.525 ;
      RECT 17.500 52.205 17.820 52.525 ;
      RECT 4.965 6.255 5.285 6.575 ;
      RECT 1.660 6.320 3.715 6.610 ;
      RECT 1.340 6.305 1.660 6.625 ;
      RECT 4.200 7.180 5.735 7.470 ;
      RECT 5.735 6.320 6.025 7.470 ;
      RECT 6.455 47.345 6.745 47.390 ;
      RECT 8.855 47.345 9.145 47.390 ;
      RECT 6.455 47.530 6.745 47.575 ;
      RECT 8.855 47.530 9.145 47.575 ;
      RECT 6.455 47.390 14.135 47.530 ;
      RECT 14.135 47.345 14.425 47.575 ;
      RECT 3.130 9.805 3.450 10.125 ;
      RECT 4.780 55.070 5.100 55.390 ;
      RECT 3.130 14.445 3.450 14.765 ;
      RECT 8.330 55.355 8.650 55.675 ;
      RECT 2.360 17.960 3.435 18.250 ;
      RECT 2.040 17.945 2.360 18.265 ;
      RECT 7.260 47.715 7.550 48.435 ;
      RECT 7.860 22.045 8.180 22.365 ;
      RECT 20.820 22.045 21.140 22.365 ;
      RECT 3.320 22.585 3.640 22.905 ;
      RECT 19.400 22.795 19.720 23.115 ;
      RECT 6.455 22.925 6.745 22.970 ;
      RECT 8.855 22.925 9.145 22.970 ;
      RECT 6.455 23.110 6.745 23.155 ;
      RECT 8.855 23.110 9.145 23.155 ;
      RECT 6.455 22.970 14.135 23.110 ;
      RECT 14.135 22.925 14.425 23.155 ;
      RECT 7.260 23.295 7.550 24.015 ;
      RECT 4.005 23.760 5.310 24.050 ;
      RECT 5.020 22.560 5.310 23.760 ;
      RECT 2.920 65.350 3.240 65.670 ;
      RECT 18.130 26.135 18.420 26.855 ;
      RECT 11.255 26.995 11.545 27.040 ;
      RECT 16.535 26.995 16.825 27.040 ;
      RECT 11.255 27.180 11.545 27.225 ;
      RECT 16.535 27.180 16.825 27.225 ;
      RECT 11.255 27.040 18.935 27.180 ;
      RECT 18.935 26.995 19.225 27.225 ;
      RECT 5.960 27.035 6.280 27.355 ;
      RECT 20.355 27.285 20.675 27.605 ;
      RECT 4.540 27.785 4.860 28.105 ;
      RECT 17.500 27.785 17.820 28.105 ;
      RECT 7.080 65.350 7.400 65.670 ;
      RECT 7.860 30.185 8.180 30.505 ;
      RECT 20.820 30.185 21.140 30.505 ;
      RECT 5.005 30.685 5.325 31.005 ;
      RECT 19.400 30.935 19.720 31.255 ;
      RECT 6.455 31.065 6.745 31.110 ;
      RECT 8.855 31.065 9.145 31.110 ;
      RECT 6.455 31.250 6.745 31.295 ;
      RECT 8.855 31.250 9.145 31.295 ;
      RECT 6.455 31.110 14.135 31.250 ;
      RECT 14.135 31.065 14.425 31.295 ;
      RECT 7.260 31.435 7.550 32.155 ;
      RECT 19.240 65.350 19.560 65.670 ;
      RECT 18.130 34.275 18.420 34.995 ;
      RECT 11.255 35.135 11.545 35.180 ;
      RECT 16.535 35.135 16.825 35.180 ;
      RECT 11.255 35.320 11.545 35.365 ;
      RECT 16.535 35.320 16.825 35.365 ;
      RECT 11.255 35.180 18.935 35.320 ;
      RECT 18.935 35.135 19.225 35.365 ;
      RECT 5.960 35.175 6.280 35.495 ;
      RECT 20.355 35.425 20.675 35.745 ;
      RECT 4.540 35.925 4.860 36.245 ;
      RECT 17.500 35.925 17.820 36.245 ;
      RECT 2.920 73.250 3.240 73.570 ;
      RECT 7.860 38.325 8.180 38.645 ;
      RECT 20.820 38.325 21.140 38.645 ;
      RECT 5.005 38.825 5.325 39.145 ;
      RECT 19.400 39.075 19.720 39.395 ;
      RECT 6.455 39.205 6.745 39.250 ;
      RECT 8.855 39.205 9.145 39.250 ;
      RECT 6.455 39.390 6.745 39.435 ;
      RECT 8.855 39.390 9.145 39.435 ;
      RECT 6.455 39.250 14.135 39.390 ;
      RECT 14.135 39.205 14.425 39.435 ;
      RECT 7.260 39.575 7.550 40.295 ;
      RECT 7.080 73.250 7.400 73.570 ;
      RECT 18.130 42.415 18.420 43.135 ;
      RECT 11.255 43.275 11.545 43.320 ;
      RECT 16.535 43.275 16.825 43.320 ;
      RECT 11.255 43.460 11.545 43.505 ;
      RECT 16.535 43.460 16.825 43.505 ;
      RECT 11.255 43.320 18.935 43.460 ;
      RECT 18.935 43.275 19.225 43.505 ;
      RECT 5.960 43.315 6.280 43.635 ;
      RECT 20.355 43.565 20.675 43.885 ;
      RECT 4.540 44.065 4.860 44.385 ;
      RECT 17.500 44.065 17.820 44.385 ;
      RECT 19.240 73.250 19.560 73.570 ;
      RECT 7.860 46.465 8.180 46.785 ;
      RECT 20.820 46.465 21.140 46.785 ;
      RECT 5.005 46.965 5.325 47.285 ;
      RECT 37.840 70.750 38.160 71.070 ;
      RECT 23.400 81.405 23.720 81.725 ;
      RECT 34.230 19.105 34.550 19.425 ;
      RECT 33.815 7.465 34.135 7.785 ;
      RECT 23.400 73.250 23.720 73.570 ;
      RECT 37.840 78.905 38.160 79.225 ;
      RECT 33.815 10.965 34.135 11.285 ;
      RECT 37.840 62.850 38.160 63.170 ;
      RECT 23.400 65.350 23.720 65.670 ;
      RECT 34.230 15.605 34.550 15.925 ;
      RECT 63.355 129.855 64.145 130.085 ;
      RECT 63.355 130.355 64.145 130.585 ;
      RECT 63.840 133.590 64.660 133.850 ;
      RECT 63.840 134.090 64.660 134.350 ;
      RECT 63.840 134.590 64.660 134.850 ;
      RECT 63.840 135.090 64.660 135.350 ;
      RECT 63.355 128.855 64.145 129.085 ;
      RECT 63.355 129.355 64.145 129.585 ;
      RECT 74.355 129.855 75.145 130.085 ;
      RECT 74.355 130.355 75.145 130.585 ;
      RECT 73.840 133.590 74.660 133.850 ;
      RECT 73.840 134.090 74.660 134.350 ;
      RECT 73.840 134.590 74.660 134.850 ;
      RECT 73.840 135.090 74.660 135.350 ;
      RECT 74.355 128.855 75.145 129.085 ;
      RECT 74.355 129.355 75.145 129.585 ;
      RECT 82.355 129.855 83.145 130.085 ;
      RECT 83.385 129.325 83.615 130.115 ;
      RECT 75.355 129.855 76.145 130.085 ;
      RECT 75.355 130.355 76.145 130.585 ;
      RECT 76.355 130.355 77.145 130.585 ;
      RECT 77.355 130.355 78.145 130.585 ;
      RECT 78.355 130.355 79.145 130.585 ;
      RECT 79.355 130.355 80.145 130.585 ;
      RECT 80.355 130.355 81.145 130.585 ;
      RECT 81.355 130.355 82.145 130.585 ;
      RECT 82.355 130.355 83.145 130.585 ;
      RECT 83.355 130.355 84.340 130.585 ;
      RECT 84.340 130.310 84.660 130.630 ;
      RECT 76.355 129.855 77.145 130.085 ;
      RECT 74.840 133.590 75.660 133.850 ;
      RECT 75.840 133.590 76.660 133.850 ;
      RECT 76.840 133.590 77.660 133.850 ;
      RECT 77.840 133.590 78.660 133.850 ;
      RECT 78.840 133.590 79.660 133.850 ;
      RECT 79.840 133.590 80.660 133.850 ;
      RECT 80.840 133.590 81.660 133.850 ;
      RECT 81.840 133.590 82.660 133.850 ;
      RECT 82.840 133.590 83.660 133.850 ;
      RECT 77.355 129.855 78.145 130.085 ;
      RECT 74.840 134.090 75.660 134.350 ;
      RECT 75.840 134.090 76.660 134.350 ;
      RECT 76.840 134.090 77.660 134.350 ;
      RECT 77.840 134.090 78.660 134.350 ;
      RECT 78.840 134.090 79.660 134.350 ;
      RECT 79.840 134.090 80.660 134.350 ;
      RECT 80.840 134.090 81.660 134.350 ;
      RECT 81.840 134.090 82.660 134.350 ;
      RECT 82.840 134.090 83.660 134.350 ;
      RECT 78.355 129.855 79.145 130.085 ;
      RECT 74.840 134.590 75.660 134.850 ;
      RECT 75.840 134.590 76.660 134.850 ;
      RECT 76.840 134.590 77.660 134.850 ;
      RECT 77.840 134.590 78.660 134.850 ;
      RECT 78.840 134.590 79.660 134.850 ;
      RECT 79.840 134.590 80.660 134.850 ;
      RECT 80.840 134.590 81.660 134.850 ;
      RECT 81.840 134.590 82.660 134.850 ;
      RECT 82.840 134.590 83.660 134.850 ;
      RECT 79.355 129.855 80.145 130.085 ;
      RECT 74.840 135.090 75.660 135.350 ;
      RECT 75.840 135.090 76.660 135.350 ;
      RECT 76.840 135.090 77.660 135.350 ;
      RECT 77.840 135.090 78.660 135.350 ;
      RECT 78.840 135.090 79.660 135.350 ;
      RECT 79.840 135.090 80.660 135.350 ;
      RECT 80.840 135.090 81.660 135.350 ;
      RECT 81.840 135.090 82.660 135.350 ;
      RECT 82.840 135.090 83.660 135.350 ;
      RECT 81.000 144.180 82.820 144.930 ;
      RECT 80.980 145.465 84.390 145.755 ;
      RECT 84.710 145.465 84.800 145.755 ;
      RECT 84.390 145.450 84.710 145.770 ;
      RECT 80.335 146.265 82.055 146.555 ;
      RECT 82.150 146.980 82.470 147.300 ;
      RECT 81.000 152.580 82.820 153.330 ;
      RECT 80.980 153.865 84.390 154.155 ;
      RECT 84.710 153.865 84.800 154.155 ;
      RECT 84.390 153.850 84.710 154.170 ;
      RECT 80.335 154.665 82.055 154.955 ;
      RECT 82.150 155.380 82.470 155.700 ;
      RECT 84.340 125.260 84.660 125.580 ;
      RECT 80.355 129.855 81.145 130.085 ;
      RECT 75.355 128.855 76.145 129.085 ;
      RECT 76.355 128.855 77.145 129.085 ;
      RECT 77.355 128.855 78.145 129.085 ;
      RECT 78.355 128.855 79.145 129.085 ;
      RECT 79.355 128.855 80.145 129.085 ;
      RECT 80.355 128.855 81.145 129.085 ;
      RECT 81.355 128.855 82.145 129.085 ;
      RECT 82.355 128.855 83.145 129.085 ;
      RECT 83.355 128.855 84.340 129.085 ;
      RECT 84.340 128.810 84.660 129.130 ;
      RECT 81.355 129.855 82.145 130.085 ;
      RECT 75.355 129.355 76.145 129.585 ;
      RECT 76.355 129.355 77.145 129.585 ;
      RECT 77.355 129.355 78.145 129.585 ;
      RECT 78.355 129.355 79.145 129.585 ;
      RECT 79.355 129.355 80.145 129.585 ;
      RECT 80.355 129.355 81.145 129.585 ;
      RECT 81.355 129.355 82.145 129.585 ;
      RECT 82.355 129.355 83.145 129.585 ;
      RECT 70.355 130.355 71.145 130.585 ;
      RECT 71.355 130.355 72.145 130.585 ;
      RECT 72.355 130.355 73.145 130.585 ;
      RECT 73.355 130.355 74.145 130.585 ;
      RECT 72.355 129.855 73.145 130.085 ;
      RECT 73.355 129.855 74.145 130.085 ;
      RECT 68.355 129.855 69.145 130.085 ;
      RECT 64.840 135.090 65.660 135.350 ;
      RECT 65.840 135.090 66.660 135.350 ;
      RECT 66.840 135.090 67.660 135.350 ;
      RECT 67.840 135.090 68.660 135.350 ;
      RECT 68.840 135.090 69.660 135.350 ;
      RECT 69.840 135.090 70.660 135.350 ;
      RECT 70.840 135.090 71.660 135.350 ;
      RECT 71.840 135.090 72.660 135.350 ;
      RECT 72.840 135.090 73.660 135.350 ;
      RECT 71.355 129.855 72.145 130.085 ;
      RECT 64.355 129.855 65.145 130.085 ;
      RECT 64.355 130.355 65.145 130.585 ;
      RECT 65.355 130.355 66.145 130.585 ;
      RECT 66.355 129.855 67.145 130.085 ;
      RECT 64.840 134.090 65.660 134.350 ;
      RECT 65.840 134.090 66.660 134.350 ;
      RECT 66.840 134.090 67.660 134.350 ;
      RECT 67.840 134.090 68.660 134.350 ;
      RECT 68.840 134.090 69.660 134.350 ;
      RECT 69.840 134.090 70.660 134.350 ;
      RECT 70.840 134.090 71.660 134.350 ;
      RECT 71.840 134.090 72.660 134.350 ;
      RECT 72.840 134.090 73.660 134.350 ;
      RECT 66.355 130.355 67.145 130.585 ;
      RECT 67.355 130.355 68.145 130.585 ;
      RECT 68.355 130.355 69.145 130.585 ;
      RECT 69.355 130.355 70.145 130.585 ;
      RECT 65.355 129.855 66.145 130.085 ;
      RECT 69.355 129.855 70.145 130.085 ;
      RECT 64.355 128.855 65.145 129.085 ;
      RECT 65.355 128.855 66.145 129.085 ;
      RECT 66.355 128.855 67.145 129.085 ;
      RECT 67.355 128.855 68.145 129.085 ;
      RECT 68.355 128.855 69.145 129.085 ;
      RECT 69.355 128.855 70.145 129.085 ;
      RECT 70.355 128.855 71.145 129.085 ;
      RECT 71.355 128.855 72.145 129.085 ;
      RECT 72.355 128.855 73.145 129.085 ;
      RECT 73.355 128.855 74.145 129.085 ;
      RECT 64.840 133.590 65.660 133.850 ;
      RECT 65.840 133.590 66.660 133.850 ;
      RECT 66.840 133.590 67.660 133.850 ;
      RECT 67.840 133.590 68.660 133.850 ;
      RECT 68.840 133.590 69.660 133.850 ;
      RECT 67.355 129.855 68.145 130.085 ;
      RECT 64.840 134.590 65.660 134.850 ;
      RECT 65.840 134.590 66.660 134.850 ;
      RECT 66.840 134.590 67.660 134.850 ;
      RECT 67.840 134.590 68.660 134.850 ;
      RECT 70.355 129.855 71.145 130.085 ;
      RECT 64.355 129.355 65.145 129.585 ;
      RECT 65.355 129.355 66.145 129.585 ;
      RECT 66.355 129.355 67.145 129.585 ;
      RECT 67.355 129.355 68.145 129.585 ;
      RECT 68.355 129.355 69.145 129.585 ;
      RECT 69.355 129.355 70.145 129.585 ;
      RECT 70.355 129.355 71.145 129.585 ;
      RECT 71.355 129.355 72.145 129.585 ;
      RECT 72.355 129.355 73.145 129.585 ;
      RECT 73.355 129.355 74.145 129.585 ;
      RECT 68.840 134.590 69.660 134.850 ;
      RECT 69.840 134.590 70.660 134.850 ;
      RECT 70.840 134.590 71.660 134.850 ;
      RECT 71.840 134.590 72.660 134.850 ;
      RECT 72.840 134.590 73.660 134.850 ;
      RECT 69.840 133.590 70.660 133.850 ;
      RECT 70.840 133.590 71.660 133.850 ;
      RECT 71.840 133.590 72.660 133.850 ;
      RECT 72.840 133.590 73.660 133.850 ;
      RECT 77.805 99.490 78.035 102.260 ;
      RECT 77.805 102.260 82.965 102.600 ;
      RECT 82.965 99.490 83.195 102.600 ;
      RECT 82.730 102.780 83.070 103.120 ;
      RECT 78.530 103.430 78.870 103.770 ;
      RECT 76.000 98.520 76.340 104.330 ;
      RECT 76.000 104.330 84.660 104.830 ;
      RECT 84.660 98.520 85.000 104.830 ;
      RECT 76.000 98.020 85.000 98.520 ;
      RECT 84.340 113.360 84.660 113.680 ;
      RECT 84.340 115.160 84.660 115.480 ;
      RECT 84.340 118.410 84.660 118.730 ;
      RECT 84.340 120.210 84.660 120.530 ;
      RECT 84.340 123.460 84.660 123.780 ;
      RECT 79.095 91.040 79.325 93.230 ;
      RECT 81.675 91.040 81.905 93.230 ;
      RECT 79.095 90.700 83.665 91.040 ;
      RECT 80.335 93.400 80.665 93.740 ;
      RECT 80.385 91.230 80.615 93.400 ;
      RECT 77.805 91.230 78.035 94.000 ;
      RECT 77.805 94.000 82.965 94.340 ;
      RECT 82.965 91.230 83.195 94.340 ;
      RECT 81.530 94.520 81.870 94.860 ;
      RECT 79.730 95.170 80.070 95.510 ;
      RECT 76.000 90.260 76.340 96.070 ;
      RECT 76.000 96.070 84.660 96.570 ;
      RECT 84.660 90.260 85.000 96.570 ;
      RECT 76.000 89.760 85.000 90.260 ;
      RECT 79.095 99.300 79.325 101.490 ;
      RECT 81.675 99.300 81.905 101.490 ;
      RECT 79.095 98.960 82.465 99.300 ;
      RECT 80.385 99.490 80.615 101.660 ;
      RECT 80.385 101.660 81.265 102.000 ;
      RECT 62.840 133.590 63.660 133.850 ;
      RECT 62.355 129.855 63.145 130.085 ;
      RECT 58.885 128.825 59.115 129.615 ;
      RECT 59.355 130.355 60.145 130.585 ;
      RECT 49.840 138.310 50.160 138.630 ;
      RECT 60.355 130.355 61.145 130.585 ;
      RECT 61.355 130.355 62.145 130.585 ;
      RECT 49.840 133.560 50.160 133.880 ;
      RECT 58.840 134.090 59.660 134.350 ;
      RECT 59.840 134.090 60.660 134.350 ;
      RECT 60.840 134.090 61.660 134.350 ;
      RECT 58.840 135.090 59.660 135.350 ;
      RECT 59.840 135.090 60.660 135.350 ;
      RECT 60.840 135.090 61.660 135.350 ;
      RECT 61.840 135.090 62.660 135.350 ;
      RECT 62.840 135.090 63.660 135.350 ;
      RECT 61.840 134.090 62.660 134.350 ;
      RECT 58.840 134.590 59.660 134.850 ;
      RECT 59.840 134.590 60.660 134.850 ;
      RECT 49.840 128.810 50.160 129.130 ;
      RECT 60.840 134.590 61.660 134.850 ;
      RECT 59.355 129.355 60.145 129.585 ;
      RECT 60.355 129.355 61.145 129.585 ;
      RECT 61.355 129.355 62.145 129.585 ;
      RECT 62.355 129.355 63.145 129.585 ;
      RECT 61.840 134.590 62.660 134.850 ;
      RECT 62.840 134.590 63.660 134.850 ;
      RECT 62.840 134.090 63.660 134.350 ;
      RECT 62.355 130.355 63.145 130.585 ;
      RECT 59.355 129.855 60.145 130.085 ;
      RECT 49.840 113.360 50.160 113.680 ;
      RECT 60.355 129.855 61.145 130.085 ;
      RECT 58.885 129.825 59.115 130.615 ;
      RECT 49.840 118.410 50.160 118.730 ;
      RECT 61.355 129.855 62.145 130.085 ;
      RECT 58.840 133.590 59.660 133.850 ;
      RECT 49.840 123.460 50.160 123.780 ;
      RECT 59.840 133.590 60.660 133.850 ;
      RECT 52.440 125.260 52.760 125.580 ;
      RECT 60.840 133.590 61.660 133.850 ;
      RECT 59.355 128.855 60.145 129.085 ;
      RECT 60.355 128.855 61.145 129.085 ;
      RECT 61.355 128.855 62.145 129.085 ;
      RECT 62.355 128.855 63.145 129.085 ;
      RECT 61.840 133.590 62.660 133.850 ;
      RECT 82.730 73.520 83.070 73.860 ;
      RECT 79.095 61.780 79.325 63.970 ;
      RECT 81.675 61.780 81.905 63.970 ;
      RECT 79.095 61.440 83.665 61.780 ;
      RECT 78.530 74.170 78.870 74.510 ;
      RECT 76.000 69.260 76.340 75.070 ;
      RECT 76.000 75.070 84.660 75.570 ;
      RECT 84.660 69.260 85.000 75.570 ;
      RECT 76.000 68.760 85.000 69.260 ;
      RECT 80.335 64.140 80.665 64.480 ;
      RECT 80.385 61.970 80.615 64.140 ;
      RECT 77.805 61.970 78.035 64.740 ;
      RECT 77.805 64.740 82.965 65.080 ;
      RECT 82.965 61.970 83.195 65.080 ;
      RECT 81.530 65.260 81.870 65.600 ;
      RECT 80.980 6.395 84.390 6.685 ;
      RECT 84.710 6.395 84.800 6.685 ;
      RECT 84.390 6.380 84.710 6.700 ;
      RECT 80.980 23.195 84.390 23.485 ;
      RECT 84.710 23.195 84.800 23.485 ;
      RECT 84.390 23.180 84.710 23.500 ;
      RECT 82.150 7.910 82.470 8.230 ;
      RECT 80.980 48.395 84.390 48.685 ;
      RECT 84.710 48.395 84.800 48.685 ;
      RECT 84.390 48.380 84.710 48.700 ;
      RECT 80.335 49.195 82.055 49.485 ;
      RECT 80.980 31.595 84.390 31.885 ;
      RECT 84.710 31.595 84.800 31.885 ;
      RECT 84.390 31.580 84.710 31.900 ;
      RECT 82.150 49.910 82.470 50.230 ;
      RECT 81.000 38.710 82.820 39.460 ;
      RECT 80.980 14.795 84.390 15.085 ;
      RECT 84.710 14.795 84.800 15.085 ;
      RECT 84.390 14.780 84.710 15.100 ;
      RECT 81.000 13.510 82.820 14.260 ;
      RECT 80.980 39.995 84.390 40.285 ;
      RECT 84.710 39.995 84.800 40.285 ;
      RECT 84.390 39.980 84.710 40.300 ;
      RECT 80.335 40.795 82.055 41.085 ;
      RECT 82.150 41.510 82.470 41.830 ;
      RECT 80.335 32.395 82.055 32.685 ;
      RECT 79.730 65.910 80.070 66.250 ;
      RECT 76.000 61.000 76.340 66.810 ;
      RECT 76.000 66.810 84.660 67.310 ;
      RECT 84.660 61.000 85.000 67.310 ;
      RECT 76.000 60.500 85.000 61.000 ;
      RECT 80.335 23.995 82.055 24.285 ;
      RECT 79.095 70.040 79.325 72.230 ;
      RECT 81.675 70.040 81.905 72.230 ;
      RECT 79.095 69.700 82.465 70.040 ;
      RECT 80.385 70.230 80.615 72.400 ;
      RECT 80.385 72.400 81.265 72.740 ;
      RECT 82.150 33.110 82.470 33.430 ;
      RECT 77.805 70.230 78.035 73.000 ;
      RECT 77.805 73.000 82.965 73.340 ;
      RECT 82.965 70.230 83.195 73.340 ;
      RECT 81.000 30.310 82.820 31.060 ;
      RECT 80.335 15.595 82.055 15.885 ;
      RECT 81.000 21.910 82.820 22.660 ;
      RECT 80.335 7.195 82.055 7.485 ;
      RECT 82.150 16.310 82.470 16.630 ;
      RECT 82.150 24.710 82.470 25.030 ;
      RECT 81.000 47.110 82.820 47.860 ;
      RECT 81.000 5.110 82.820 5.860 ;
    LAYER met2 ;
      RECT 83.360 167.245 83.640 167.260 ;
      RECT 83.335 166.915 83.665 167.245 ;
      RECT 83.360 160.405 83.640 166.915 ;
      RECT 83.315 160.035 83.685 160.405 ;
      RECT 80.360 169.945 80.640 169.960 ;
      RECT 80.335 169.615 80.665 169.945 ;
      RECT 80.360 162.405 80.640 169.615 ;
      RECT 80.315 162.035 80.685 162.405 ;
      RECT 77.960 170.545 78.240 170.560 ;
      RECT 77.935 170.215 78.265 170.545 ;
      RECT 77.960 164.405 78.240 170.215 ;
      RECT 77.915 164.035 78.285 164.405 ;
      RECT 81.560 171.065 81.840 171.080 ;
      RECT 81.535 170.735 81.865 171.065 ;
      RECT 81.560 161.405 81.840 170.735 ;
      RECT 81.515 161.035 81.885 161.405 ;
      RECT 79.760 171.715 80.040 171.730 ;
      RECT 79.735 171.385 80.065 171.715 ;
      RECT 79.760 163.405 80.040 171.385 ;
      RECT 79.715 163.035 80.085 163.405 ;
      RECT 41.000 0.200 42.000 327.770 ;
      RECT 45.000 0.200 46.000 327.770 ;
      RECT 43.000 2.200 44.000 329.770 ;
      RECT 82.135 175.175 82.160 175.505 ;
      RECT 82.115 183.295 82.485 183.665 ;
      RECT 82.440 175.175 82.465 175.505 ;
      RECT 82.160 175.160 82.440 183.295 ;
      RECT 80.935 177.875 80.960 178.205 ;
      RECT 80.915 184.295 81.285 184.665 ;
      RECT 81.240 177.875 81.265 178.205 ;
      RECT 80.960 177.860 81.240 184.295 ;
      RECT 79.135 178.475 79.160 178.805 ;
      RECT 79.115 185.295 79.485 185.665 ;
      RECT 79.440 178.475 79.465 178.805 ;
      RECT 79.160 178.460 79.440 185.295 ;
      RECT 78.535 179.645 78.560 179.975 ;
      RECT 78.515 186.295 78.885 186.665 ;
      RECT 78.840 179.645 78.865 179.975 ;
      RECT 78.560 179.630 78.840 186.295 ;
      RECT 81.615 190.430 81.985 190.800 ;
      RECT 84.365 191.485 84.735 191.855 ;
      RECT 80.365 192.480 80.625 192.630 ;
      RECT 80.335 189.665 80.655 192.480 ;
      RECT 80.310 189.295 80.680 189.665 ;
      RECT 82.125 193.000 82.495 195.065 ;
      RECT 81.615 198.830 81.985 199.200 ;
      RECT 84.365 199.885 84.735 200.255 ;
      RECT 80.365 200.880 80.625 201.030 ;
      RECT 80.335 198.065 80.655 200.880 ;
      RECT 80.310 197.695 80.680 198.065 ;
      RECT 82.125 201.400 82.495 203.465 ;
      RECT 75.985 212.095 76.355 212.465 ;
      RECT 83.360 213.305 83.640 213.320 ;
      RECT 83.335 212.975 83.665 213.305 ;
      RECT 83.360 206.465 83.640 212.975 ;
      RECT 83.315 206.095 83.685 206.465 ;
      RECT 80.360 216.005 80.640 216.020 ;
      RECT 80.335 215.675 80.665 216.005 ;
      RECT 80.360 208.465 80.640 215.675 ;
      RECT 80.315 208.095 80.685 208.465 ;
      RECT 77.960 216.605 78.240 216.620 ;
      RECT 77.935 216.275 78.265 216.605 ;
      RECT 77.960 210.465 78.240 216.275 ;
      RECT 77.915 210.095 78.285 210.465 ;
      RECT 81.560 217.125 81.840 217.140 ;
      RECT 81.535 216.795 81.865 217.125 ;
      RECT 81.560 207.465 81.840 216.795 ;
      RECT 81.515 207.095 81.885 207.465 ;
      RECT 79.760 217.775 80.040 217.790 ;
      RECT 79.735 217.445 80.065 217.775 ;
      RECT 79.760 209.465 80.040 217.445 ;
      RECT 79.715 209.095 80.085 209.465 ;
      RECT 75.985 226.665 76.355 227.035 ;
      RECT 82.735 225.055 82.760 225.385 ;
      RECT 82.715 228.355 83.085 228.725 ;
      RECT 83.040 225.055 83.065 225.385 ;
      RECT 82.760 225.040 83.040 228.355 ;
      RECT 82.135 221.235 82.160 221.565 ;
      RECT 82.115 229.355 82.485 229.725 ;
      RECT 82.440 221.235 82.465 221.565 ;
      RECT 82.160 221.220 82.440 229.355 ;
      RECT 80.935 223.935 80.960 224.265 ;
      RECT 80.915 230.355 81.285 230.725 ;
      RECT 81.240 223.935 81.265 224.265 ;
      RECT 80.960 223.920 81.240 230.355 ;
      RECT 79.135 224.535 79.160 224.865 ;
      RECT 79.115 231.355 79.485 231.725 ;
      RECT 79.440 224.535 79.465 224.865 ;
      RECT 79.160 224.520 79.440 231.355 ;
      RECT 78.535 225.705 78.560 226.035 ;
      RECT 78.515 232.355 78.885 232.725 ;
      RECT 78.840 225.705 78.865 226.035 ;
      RECT 78.560 225.690 78.840 232.355 ;
      RECT 81.615 236.490 81.985 236.860 ;
      RECT 84.365 237.545 84.735 237.915 ;
      RECT 80.365 238.540 80.625 238.690 ;
      RECT 80.335 235.725 80.655 238.540 ;
      RECT 80.310 235.355 80.680 235.725 ;
      RECT 82.125 239.060 82.495 241.125 ;
      RECT 81.615 244.890 81.985 245.260 ;
      RECT 84.365 245.945 84.735 246.315 ;
      RECT 80.365 246.940 80.625 247.090 ;
      RECT 80.335 244.125 80.655 246.940 ;
      RECT 80.310 243.755 80.680 244.125 ;
      RECT 82.125 247.460 82.495 249.525 ;
      RECT 75.985 258.155 76.355 258.525 ;
      RECT 83.360 259.365 83.640 259.380 ;
      RECT 83.335 259.035 83.665 259.365 ;
      RECT 83.360 252.525 83.640 259.035 ;
      RECT 83.315 252.155 83.685 252.525 ;
      RECT 80.360 262.065 80.640 262.080 ;
      RECT 80.335 261.735 80.665 262.065 ;
      RECT 80.360 254.525 80.640 261.735 ;
      RECT 80.315 254.155 80.685 254.525 ;
      RECT 77.960 262.665 78.240 262.680 ;
      RECT 77.935 262.335 78.265 262.665 ;
      RECT 77.960 256.525 78.240 262.335 ;
      RECT 77.915 256.155 78.285 256.525 ;
      RECT 81.560 263.185 81.840 263.200 ;
      RECT 81.535 262.855 81.865 263.185 ;
      RECT 81.560 253.525 81.840 262.855 ;
      RECT 81.515 253.155 81.885 253.525 ;
      RECT 79.760 263.835 80.040 263.850 ;
      RECT 79.735 263.505 80.065 263.835 ;
      RECT 79.760 255.525 80.040 263.505 ;
      RECT 79.715 255.155 80.085 255.525 ;
      RECT 75.985 272.725 76.355 273.095 ;
      RECT 82.735 271.115 82.760 271.445 ;
      RECT 82.715 274.415 83.085 274.785 ;
      RECT 83.040 271.115 83.065 271.445 ;
      RECT 82.760 271.100 83.040 274.415 ;
      RECT 82.135 267.295 82.160 267.625 ;
      RECT 82.115 275.415 82.485 275.785 ;
      RECT 82.440 267.295 82.465 267.625 ;
      RECT 82.160 267.280 82.440 275.415 ;
      RECT 80.935 269.995 80.960 270.325 ;
      RECT 80.915 276.415 81.285 276.785 ;
      RECT 81.240 269.995 81.265 270.325 ;
      RECT 80.960 269.980 81.240 276.415 ;
      RECT 79.135 270.595 79.160 270.925 ;
      RECT 79.115 277.415 79.485 277.785 ;
      RECT 79.440 270.595 79.465 270.925 ;
      RECT 79.160 270.580 79.440 277.415 ;
      RECT 78.535 271.765 78.560 272.095 ;
      RECT 78.515 278.415 78.885 278.785 ;
      RECT 78.840 271.765 78.865 272.095 ;
      RECT 78.560 271.750 78.840 278.415 ;
      RECT 81.615 282.550 81.985 282.920 ;
      RECT 84.365 283.605 84.735 283.975 ;
      RECT 80.365 284.600 80.625 284.750 ;
      RECT 80.335 281.785 80.655 284.600 ;
      RECT 80.310 281.415 80.680 281.785 ;
      RECT 82.125 285.120 82.495 287.185 ;
      RECT 81.615 290.950 81.985 291.320 ;
      RECT 84.365 292.005 84.735 292.375 ;
      RECT 80.365 293.000 80.625 293.150 ;
      RECT 80.335 290.185 80.655 293.000 ;
      RECT 80.310 289.815 80.680 290.185 ;
      RECT 82.125 293.520 82.495 295.585 ;
      RECT 75.985 304.215 76.355 304.585 ;
      RECT 83.360 305.425 83.640 305.440 ;
      RECT 83.335 305.095 83.665 305.425 ;
      RECT 83.360 298.585 83.640 305.095 ;
      RECT 83.315 298.215 83.685 298.585 ;
      RECT 80.360 308.125 80.640 308.140 ;
      RECT 80.335 307.795 80.665 308.125 ;
      RECT 80.360 300.585 80.640 307.795 ;
      RECT 80.315 300.215 80.685 300.585 ;
      RECT 77.960 308.725 78.240 308.740 ;
      RECT 77.935 308.395 78.265 308.725 ;
      RECT 77.960 302.585 78.240 308.395 ;
      RECT 77.915 302.215 78.285 302.585 ;
      RECT 81.560 309.245 81.840 309.260 ;
      RECT 81.535 308.915 81.865 309.245 ;
      RECT 81.560 299.585 81.840 308.915 ;
      RECT 81.515 299.215 81.885 299.585 ;
      RECT 79.760 309.895 80.040 309.910 ;
      RECT 79.735 309.565 80.065 309.895 ;
      RECT 79.760 301.585 80.040 309.565 ;
      RECT 79.715 301.215 80.085 301.585 ;
      RECT 75.985 318.785 76.355 319.155 ;
      RECT 82.735 317.175 82.760 317.505 ;
      RECT 82.715 320.475 83.085 320.845 ;
      RECT 83.040 317.175 83.065 317.505 ;
      RECT 82.760 317.160 83.040 320.475 ;
      RECT 82.135 313.355 82.160 313.685 ;
      RECT 82.115 321.475 82.485 321.845 ;
      RECT 82.440 313.355 82.465 313.685 ;
      RECT 82.160 313.340 82.440 321.475 ;
      RECT 80.935 316.055 80.960 316.385 ;
      RECT 80.915 322.475 81.285 322.845 ;
      RECT 81.240 316.055 81.265 316.385 ;
      RECT 80.960 316.040 81.240 322.475 ;
      RECT 79.135 316.655 79.160 316.985 ;
      RECT 79.115 323.475 79.485 323.845 ;
      RECT 79.440 316.655 79.465 316.985 ;
      RECT 79.160 316.640 79.440 323.475 ;
      RECT 78.535 317.825 78.560 318.155 ;
      RECT 78.515 324.475 78.885 324.845 ;
      RECT 78.840 317.825 78.865 318.155 ;
      RECT 78.560 317.810 78.840 324.475 ;
      RECT 75.985 166.035 76.355 166.405 ;
      RECT 75.985 180.605 76.355 180.975 ;
      RECT 82.735 178.995 82.760 179.325 ;
      RECT 82.715 182.295 83.085 182.665 ;
      RECT 83.040 178.995 83.065 179.325 ;
      RECT 82.760 178.980 83.040 182.295 ;
      RECT 21.840 267.900 22.660 268.160 ;
      RECT 21.840 268.400 22.660 268.660 ;
      RECT 21.840 268.900 22.660 269.160 ;
      RECT 21.840 269.400 22.660 269.660 ;
      RECT 21.215 272.640 22.235 272.920 ;
      RECT 21.215 273.290 22.235 273.570 ;
      RECT 21.215 273.940 22.235 274.220 ;
      RECT 21.215 274.590 22.235 274.870 ;
      RECT 21.840 298.050 22.660 298.310 ;
      RECT 21.840 298.550 22.660 298.810 ;
      RECT 21.840 299.050 22.660 299.310 ;
      RECT 21.840 299.550 22.660 299.810 ;
      RECT 21.215 302.790 22.235 303.070 ;
      RECT 21.215 303.440 22.235 303.720 ;
      RECT 21.215 304.090 22.235 304.370 ;
      RECT 5.600 222.180 6.000 229.380 ;
      RECT 2.000 221.780 6.000 222.180 ;
      RECT 7.200 222.180 7.600 229.380 ;
      RECT 6.400 221.780 7.600 222.180 ;
      RECT 8.800 222.180 9.200 229.380 ;
      RECT 8.000 221.780 9.200 222.180 ;
      RECT 10.400 222.180 10.800 229.380 ;
      RECT 9.600 221.780 10.800 222.180 ;
      RECT 12.000 222.180 12.400 229.380 ;
      RECT 11.200 221.780 12.400 222.180 ;
      RECT 13.600 222.180 14.000 229.380 ;
      RECT 12.800 221.780 14.000 222.180 ;
      RECT 15.200 222.180 15.600 229.380 ;
      RECT 14.400 221.780 15.600 222.180 ;
      RECT 16.800 222.180 17.200 229.380 ;
      RECT 16.000 221.780 17.200 222.180 ;
      RECT 18.400 222.180 18.800 229.380 ;
      RECT 17.600 221.780 18.800 222.180 ;
      RECT 20.000 222.180 20.400 229.380 ;
      RECT 19.200 221.780 20.400 222.180 ;
      RECT 21.600 222.180 22.000 229.380 ;
      RECT 20.800 221.780 22.000 222.180 ;
      RECT 23.200 222.180 23.600 229.380 ;
      RECT 22.400 221.780 23.600 222.180 ;
      RECT 24.800 222.180 25.200 229.380 ;
      RECT 24.000 221.780 25.200 222.180 ;
      RECT 26.400 222.180 26.800 229.380 ;
      RECT 25.600 221.780 26.800 222.180 ;
      RECT 5.600 229.380 6.800 229.780 ;
      RECT 6.400 222.180 6.800 229.380 ;
      RECT 7.200 229.380 8.400 229.780 ;
      RECT 8.000 222.180 8.400 229.380 ;
      RECT 8.800 229.380 10.000 229.780 ;
      RECT 9.600 222.180 10.000 229.380 ;
      RECT 10.400 229.380 11.600 229.780 ;
      RECT 11.200 222.180 11.600 229.380 ;
      RECT 12.000 229.380 13.200 229.780 ;
      RECT 12.800 222.180 13.200 229.380 ;
      RECT 13.600 229.380 14.800 229.780 ;
      RECT 14.400 222.180 14.800 229.380 ;
      RECT 15.200 229.380 16.400 229.780 ;
      RECT 16.000 222.180 16.400 229.380 ;
      RECT 16.800 229.380 18.000 229.780 ;
      RECT 17.600 222.180 18.000 229.380 ;
      RECT 18.400 229.380 19.600 229.780 ;
      RECT 19.200 222.180 19.600 229.380 ;
      RECT 20.000 229.380 21.200 229.780 ;
      RECT 20.800 222.180 21.200 229.380 ;
      RECT 21.600 229.380 22.800 229.780 ;
      RECT 22.400 222.180 22.800 229.380 ;
      RECT 23.200 229.380 24.400 229.780 ;
      RECT 24.000 222.180 24.400 229.380 ;
      RECT 24.800 229.380 26.000 229.780 ;
      RECT 25.600 222.180 26.000 229.380 ;
      RECT 27.200 221.780 31.200 222.180 ;
      RECT 26.400 229.380 27.600 229.780 ;
      RECT 27.200 222.180 27.600 229.380 ;
      RECT 21.215 304.740 22.235 305.020 ;
      RECT 31.615 272.640 32.635 272.920 ;
      RECT 31.615 273.290 32.635 273.570 ;
      RECT 31.615 273.940 32.635 274.220 ;
      RECT 31.615 274.590 32.635 274.870 ;
      RECT 31.615 302.790 32.635 303.070 ;
      RECT 31.615 303.440 32.635 303.720 ;
      RECT 31.615 304.090 32.635 304.370 ;
      RECT 31.615 304.740 32.635 305.020 ;
      RECT 32.915 302.790 33.935 303.070 ;
      RECT 34.215 302.790 35.235 303.070 ;
      RECT 35.515 302.790 36.535 303.070 ;
      RECT 37.815 302.745 38.185 303.115 ;
      RECT 37.815 293.245 38.185 293.615 ;
      RECT 32.915 303.440 33.935 303.720 ;
      RECT 34.215 303.440 35.235 303.720 ;
      RECT 35.515 303.440 36.535 303.720 ;
      RECT 37.815 297.995 38.185 298.365 ;
      RECT 32.915 304.090 33.935 304.370 ;
      RECT 34.215 304.090 35.235 304.370 ;
      RECT 35.515 304.090 36.535 304.370 ;
      RECT 35.215 289.695 35.585 290.065 ;
      RECT 32.915 304.740 33.935 305.020 ;
      RECT 34.215 304.740 35.235 305.020 ;
      RECT 35.515 304.740 36.535 305.020 ;
      RECT 37.815 307.945 38.185 308.315 ;
      RECT 37.815 312.995 38.185 313.365 ;
      RECT 37.815 318.045 38.185 318.415 ;
      RECT 35.215 319.845 35.585 320.215 ;
      RECT 37.815 323.395 38.185 323.765 ;
      RECT 25.840 299.550 26.660 299.810 ;
      RECT 26.840 299.550 27.660 299.810 ;
      RECT 27.840 299.550 28.660 299.810 ;
      RECT 28.870 299.020 29.130 299.840 ;
      RECT 22.515 302.790 23.535 303.070 ;
      RECT 23.815 302.790 24.835 303.070 ;
      RECT 25.115 302.790 26.135 303.070 ;
      RECT 26.415 302.790 27.435 303.070 ;
      RECT 27.715 302.790 28.735 303.070 ;
      RECT 29.015 302.790 30.035 303.070 ;
      RECT 30.315 302.790 31.335 303.070 ;
      RECT 23.840 298.050 24.660 298.310 ;
      RECT 24.840 298.050 25.660 298.310 ;
      RECT 25.840 298.050 26.660 298.310 ;
      RECT 26.840 298.050 27.660 298.310 ;
      RECT 27.840 298.050 28.660 298.310 ;
      RECT 22.515 303.440 23.535 303.720 ;
      RECT 23.815 303.440 24.835 303.720 ;
      RECT 25.115 303.440 26.135 303.720 ;
      RECT 26.415 303.440 27.435 303.720 ;
      RECT 27.715 303.440 28.735 303.720 ;
      RECT 29.015 303.440 30.035 303.720 ;
      RECT 30.315 303.440 31.335 303.720 ;
      RECT 22.840 298.050 23.660 298.310 ;
      RECT 22.840 298.550 23.660 298.810 ;
      RECT 23.840 298.550 24.660 298.810 ;
      RECT 24.840 298.550 25.660 298.810 ;
      RECT 22.515 304.090 23.535 304.370 ;
      RECT 23.815 304.090 24.835 304.370 ;
      RECT 25.115 304.090 26.135 304.370 ;
      RECT 26.415 304.090 27.435 304.370 ;
      RECT 27.715 304.090 28.735 304.370 ;
      RECT 29.015 304.090 30.035 304.370 ;
      RECT 30.315 304.090 31.335 304.370 ;
      RECT 25.840 298.550 26.660 298.810 ;
      RECT 26.840 298.550 27.660 298.810 ;
      RECT 27.840 298.550 28.660 298.810 ;
      RECT 28.870 298.020 29.130 298.840 ;
      RECT 22.515 304.740 23.535 305.020 ;
      RECT 23.815 304.740 24.835 305.020 ;
      RECT 25.115 304.740 26.135 305.020 ;
      RECT 26.415 304.740 27.435 305.020 ;
      RECT 27.715 304.740 28.735 305.020 ;
      RECT 29.015 304.740 30.035 305.020 ;
      RECT 30.315 304.740 31.335 305.020 ;
      RECT 22.840 299.050 23.660 299.310 ;
      RECT 23.840 299.050 24.660 299.310 ;
      RECT 24.840 299.050 25.660 299.310 ;
      RECT 25.840 299.050 26.660 299.310 ;
      RECT 26.840 299.050 27.660 299.310 ;
      RECT 27.840 299.050 28.660 299.310 ;
      RECT 22.840 299.550 23.660 299.810 ;
      RECT 23.840 299.550 24.660 299.810 ;
      RECT 24.840 299.550 25.660 299.810 ;
      RECT 23.840 267.900 24.660 268.160 ;
      RECT 22.515 273.940 23.535 274.220 ;
      RECT 23.815 273.940 24.835 274.220 ;
      RECT 25.115 273.940 26.135 274.220 ;
      RECT 26.415 273.940 27.435 274.220 ;
      RECT 27.715 273.940 28.735 274.220 ;
      RECT 29.015 273.940 30.035 274.220 ;
      RECT 30.315 273.940 31.335 274.220 ;
      RECT 28.870 267.870 29.130 268.690 ;
      RECT 24.840 267.900 25.660 268.160 ;
      RECT 22.515 274.590 23.535 274.870 ;
      RECT 23.815 274.590 24.835 274.870 ;
      RECT 22.840 268.400 23.660 268.660 ;
      RECT 25.115 274.590 26.135 274.870 ;
      RECT 26.415 274.590 27.435 274.870 ;
      RECT 27.715 274.590 28.735 274.870 ;
      RECT 29.015 274.590 30.035 274.870 ;
      RECT 30.315 274.590 31.335 274.870 ;
      RECT 22.840 268.900 23.660 269.160 ;
      RECT 23.840 268.900 24.660 269.160 ;
      RECT 24.840 268.900 25.660 269.160 ;
      RECT 25.840 267.900 26.660 268.160 ;
      RECT 25.840 268.900 26.660 269.160 ;
      RECT 26.840 268.900 27.660 269.160 ;
      RECT 23.840 268.400 24.660 268.660 ;
      RECT 27.840 268.900 28.660 269.160 ;
      RECT 22.840 269.400 23.660 269.660 ;
      RECT 23.840 269.400 24.660 269.660 ;
      RECT 24.840 269.400 25.660 269.660 ;
      RECT 25.840 269.400 26.660 269.660 ;
      RECT 26.840 267.900 27.660 268.160 ;
      RECT 26.840 269.400 27.660 269.660 ;
      RECT 27.840 269.400 28.660 269.660 ;
      RECT 28.870 268.870 29.130 269.690 ;
      RECT 22.515 272.640 23.535 272.920 ;
      RECT 23.815 272.640 24.835 272.920 ;
      RECT 24.840 268.400 25.660 268.660 ;
      RECT 25.840 268.400 26.660 268.660 ;
      RECT 25.115 272.640 26.135 272.920 ;
      RECT 26.415 272.640 27.435 272.920 ;
      RECT 27.840 267.900 28.660 268.160 ;
      RECT 27.715 272.640 28.735 272.920 ;
      RECT 29.015 272.640 30.035 272.920 ;
      RECT 30.315 272.640 31.335 272.920 ;
      RECT 26.840 268.400 27.660 268.660 ;
      RECT 22.840 267.900 23.660 268.160 ;
      RECT 22.515 273.290 23.535 273.570 ;
      RECT 23.815 273.290 24.835 273.570 ;
      RECT 25.115 273.290 26.135 273.570 ;
      RECT 26.415 273.290 27.435 273.570 ;
      RECT 27.715 273.290 28.735 273.570 ;
      RECT 29.015 273.290 30.035 273.570 ;
      RECT 30.315 273.290 31.335 273.570 ;
      RECT 27.840 268.400 28.660 268.660 ;
      RECT 37.815 267.845 38.185 268.215 ;
      RECT 32.915 272.640 33.935 272.920 ;
      RECT 34.215 272.640 35.235 272.920 ;
      RECT 35.515 272.640 36.535 272.920 ;
      RECT 37.815 272.595 38.185 272.965 ;
      RECT 37.815 252.695 38.185 253.065 ;
      RECT 37.815 263.095 38.185 263.465 ;
      RECT 32.915 273.290 33.935 273.570 ;
      RECT 37.815 257.745 38.185 258.115 ;
      RECT 32.915 274.590 33.935 274.870 ;
      RECT 34.215 274.590 35.235 274.870 ;
      RECT 35.515 274.590 36.535 274.870 ;
      RECT 37.815 277.795 38.185 278.165 ;
      RECT 37.815 282.845 38.185 283.215 ;
      RECT 37.815 287.895 38.185 288.265 ;
      RECT 34.215 273.290 35.235 273.570 ;
      RECT 32.915 273.940 33.935 274.220 ;
      RECT 34.215 273.940 35.235 274.220 ;
      RECT 35.515 273.940 36.535 274.220 ;
      RECT 35.515 273.290 36.535 273.570 ;
      RECT 35.215 259.545 35.585 259.915 ;
      RECT 37.815 247.645 38.185 248.015 ;
      RECT 10.815 274.590 11.835 274.870 ;
      RECT 10.815 272.640 11.835 272.920 ;
      RECT 10.815 302.790 11.835 303.070 ;
      RECT 10.815 303.440 11.835 303.720 ;
      RECT 10.815 273.290 11.835 273.570 ;
      RECT 10.815 304.090 11.835 304.370 ;
      RECT 10.815 304.740 11.835 305.020 ;
      RECT 10.815 273.940 11.835 274.220 ;
      RECT 18.840 298.050 19.660 298.310 ;
      RECT 19.840 298.050 20.660 298.310 ;
      RECT 20.840 298.050 21.660 298.310 ;
      RECT 11.840 298.550 12.660 298.810 ;
      RECT 12.840 298.550 13.660 298.810 ;
      RECT 13.840 298.550 14.660 298.810 ;
      RECT 14.840 298.550 15.660 298.810 ;
      RECT 15.840 298.550 16.660 298.810 ;
      RECT 16.840 298.550 17.660 298.810 ;
      RECT 17.840 298.550 18.660 298.810 ;
      RECT 18.840 298.550 19.660 298.810 ;
      RECT 19.840 298.550 20.660 298.810 ;
      RECT 20.840 298.550 21.660 298.810 ;
      RECT 11.840 299.050 12.660 299.310 ;
      RECT 12.840 299.050 13.660 299.310 ;
      RECT 13.840 299.050 14.660 299.310 ;
      RECT 14.840 299.050 15.660 299.310 ;
      RECT 15.840 299.050 16.660 299.310 ;
      RECT 16.840 299.050 17.660 299.310 ;
      RECT 17.840 299.050 18.660 299.310 ;
      RECT 18.840 299.050 19.660 299.310 ;
      RECT 19.840 299.050 20.660 299.310 ;
      RECT 20.840 299.050 21.660 299.310 ;
      RECT 11.840 299.550 12.660 299.810 ;
      RECT 12.840 299.550 13.660 299.810 ;
      RECT 13.840 299.550 14.660 299.810 ;
      RECT 14.840 299.550 15.660 299.810 ;
      RECT 15.840 299.550 16.660 299.810 ;
      RECT 16.840 299.550 17.660 299.810 ;
      RECT 17.840 299.550 18.660 299.810 ;
      RECT 18.840 299.550 19.660 299.810 ;
      RECT 19.840 299.550 20.660 299.810 ;
      RECT 20.840 299.550 21.660 299.810 ;
      RECT 11.840 298.050 12.660 298.310 ;
      RECT 12.840 298.050 13.660 298.310 ;
      RECT 12.115 302.790 13.135 303.070 ;
      RECT 13.415 302.790 14.435 303.070 ;
      RECT 14.715 302.790 15.735 303.070 ;
      RECT 16.015 302.790 17.035 303.070 ;
      RECT 17.315 302.790 18.335 303.070 ;
      RECT 18.615 302.790 19.635 303.070 ;
      RECT 19.915 302.790 20.935 303.070 ;
      RECT 13.840 298.050 14.660 298.310 ;
      RECT 12.115 303.440 13.135 303.720 ;
      RECT 13.415 303.440 14.435 303.720 ;
      RECT 14.715 303.440 15.735 303.720 ;
      RECT 16.015 303.440 17.035 303.720 ;
      RECT 17.315 303.440 18.335 303.720 ;
      RECT 18.615 303.440 19.635 303.720 ;
      RECT 19.915 303.440 20.935 303.720 ;
      RECT 14.840 298.050 15.660 298.310 ;
      RECT 15.840 298.050 16.660 298.310 ;
      RECT 12.115 304.090 13.135 304.370 ;
      RECT 13.415 304.090 14.435 304.370 ;
      RECT 14.715 304.090 15.735 304.370 ;
      RECT 16.015 304.090 17.035 304.370 ;
      RECT 17.315 304.090 18.335 304.370 ;
      RECT 18.615 304.090 19.635 304.370 ;
      RECT 19.915 304.090 20.935 304.370 ;
      RECT 16.840 298.050 17.660 298.310 ;
      RECT 12.115 304.740 13.135 305.020 ;
      RECT 13.415 304.740 14.435 305.020 ;
      RECT 14.715 304.740 15.735 305.020 ;
      RECT 16.015 304.740 17.035 305.020 ;
      RECT 17.315 304.740 18.335 305.020 ;
      RECT 18.615 304.740 19.635 305.020 ;
      RECT 19.915 304.740 20.935 305.020 ;
      RECT 17.840 298.050 18.660 298.310 ;
      RECT 4.315 302.790 5.335 303.070 ;
      RECT 5.615 302.790 6.635 303.070 ;
      RECT 6.915 302.790 7.935 303.070 ;
      RECT 8.215 302.790 9.235 303.070 ;
      RECT 9.515 302.790 10.535 303.070 ;
      RECT 7.840 299.050 8.660 299.310 ;
      RECT 8.840 299.050 9.660 299.310 ;
      RECT 9.840 299.050 10.660 299.310 ;
      RECT 10.840 299.050 11.660 299.310 ;
      RECT 3.685 298.050 4.660 298.310 ;
      RECT 3.315 297.995 3.685 298.365 ;
      RECT 4.840 298.550 5.660 298.810 ;
      RECT 5.840 298.550 6.660 298.810 ;
      RECT 6.840 298.550 7.660 298.810 ;
      RECT 4.315 303.440 5.335 303.720 ;
      RECT 5.615 303.440 6.635 303.720 ;
      RECT 6.915 303.440 7.935 303.720 ;
      RECT 8.215 303.440 9.235 303.720 ;
      RECT 9.515 303.440 10.535 303.720 ;
      RECT 7.840 298.550 8.660 298.810 ;
      RECT 8.840 298.550 9.660 298.810 ;
      RECT 9.840 298.550 10.660 298.810 ;
      RECT 10.840 298.550 11.660 298.810 ;
      RECT 3.315 289.695 3.685 290.065 ;
      RECT 3.315 293.245 3.685 293.615 ;
      RECT 4.370 298.520 4.630 299.340 ;
      RECT 4.840 299.550 5.660 299.810 ;
      RECT 5.840 299.550 6.660 299.810 ;
      RECT 4.315 304.090 5.335 304.370 ;
      RECT 5.615 304.090 6.635 304.370 ;
      RECT 6.915 304.090 7.935 304.370 ;
      RECT 8.215 304.090 9.235 304.370 ;
      RECT 9.515 304.090 10.535 304.370 ;
      RECT 6.840 299.550 7.660 299.810 ;
      RECT 7.840 299.550 8.660 299.810 ;
      RECT 8.840 299.550 9.660 299.810 ;
      RECT 9.840 299.550 10.660 299.810 ;
      RECT 10.840 299.550 11.660 299.810 ;
      RECT 3.315 294.745 3.685 295.115 ;
      RECT 4.840 298.050 5.660 298.310 ;
      RECT 5.840 298.050 6.660 298.310 ;
      RECT 4.315 304.740 5.335 305.020 ;
      RECT 5.615 304.740 6.635 305.020 ;
      RECT 6.915 304.740 7.935 305.020 ;
      RECT 8.215 304.740 9.235 305.020 ;
      RECT 9.515 304.740 10.535 305.020 ;
      RECT 6.840 298.050 7.660 298.310 ;
      RECT 7.840 298.050 8.660 298.310 ;
      RECT 8.840 298.050 9.660 298.310 ;
      RECT 9.840 298.050 10.660 298.310 ;
      RECT 10.840 298.050 11.660 298.310 ;
      RECT 4.840 299.050 5.660 299.310 ;
      RECT 5.840 299.050 6.660 299.310 ;
      RECT 6.840 299.050 7.660 299.310 ;
      RECT 3.685 299.550 4.660 299.810 ;
      RECT 3.315 299.495 3.685 299.865 ;
      RECT 3.315 307.945 3.685 308.315 ;
      RECT 3.315 309.745 3.685 310.115 ;
      RECT 3.315 312.995 3.685 313.365 ;
      RECT 3.315 314.795 3.685 315.165 ;
      RECT 3.315 318.045 3.685 318.415 ;
      RECT 3.315 319.845 3.685 320.215 ;
      RECT 3.315 323.395 3.685 323.765 ;
      RECT 3.315 324.895 3.685 325.265 ;
      RECT 3.315 284.645 3.685 285.015 ;
      RECT 3.315 287.895 3.685 288.265 ;
      RECT 4.370 268.370 4.630 269.190 ;
      RECT 5.840 268.900 6.660 269.160 ;
      RECT 4.840 269.400 5.660 269.660 ;
      RECT 6.840 269.400 7.660 269.660 ;
      RECT 7.840 269.400 8.660 269.660 ;
      RECT 8.840 269.400 9.660 269.660 ;
      RECT 9.840 269.400 10.660 269.660 ;
      RECT 9.840 268.400 10.660 268.660 ;
      RECT 10.840 268.400 11.660 268.660 ;
      RECT 4.315 273.290 5.335 273.570 ;
      RECT 5.615 273.290 6.635 273.570 ;
      RECT 6.915 273.290 7.935 273.570 ;
      RECT 8.215 273.290 9.235 273.570 ;
      RECT 9.515 273.290 10.535 273.570 ;
      RECT 10.840 269.400 11.660 269.660 ;
      RECT 6.840 268.900 7.660 269.160 ;
      RECT 5.840 269.400 6.660 269.660 ;
      RECT 7.840 268.900 8.660 269.160 ;
      RECT 3.685 269.400 4.660 269.660 ;
      RECT 3.315 269.345 3.685 269.715 ;
      RECT 4.315 272.640 5.335 272.920 ;
      RECT 5.615 272.640 6.635 272.920 ;
      RECT 6.915 272.640 7.935 272.920 ;
      RECT 8.215 272.640 9.235 272.920 ;
      RECT 9.515 272.640 10.535 272.920 ;
      RECT 8.840 268.900 9.660 269.160 ;
      RECT 9.840 268.900 10.660 269.160 ;
      RECT 10.840 268.900 11.660 269.160 ;
      RECT 4.315 274.590 5.335 274.870 ;
      RECT 5.615 274.590 6.635 274.870 ;
      RECT 6.915 274.590 7.935 274.870 ;
      RECT 8.215 274.590 9.235 274.870 ;
      RECT 3.315 257.745 3.685 258.115 ;
      RECT 3.315 252.695 3.685 253.065 ;
      RECT 3.315 259.545 3.685 259.915 ;
      RECT 3.315 249.445 3.685 249.815 ;
      RECT 3.315 263.095 3.685 263.465 ;
      RECT 3.315 254.495 3.685 254.865 ;
      RECT 3.315 264.595 3.685 264.965 ;
      RECT 9.515 274.590 10.535 274.870 ;
      RECT 3.685 267.900 4.660 268.160 ;
      RECT 3.315 267.845 3.685 268.215 ;
      RECT 4.840 267.900 5.660 268.160 ;
      RECT 5.840 267.900 6.660 268.160 ;
      RECT 6.840 267.900 7.660 268.160 ;
      RECT 7.840 267.900 8.660 268.160 ;
      RECT 8.840 267.900 9.660 268.160 ;
      RECT 9.840 267.900 10.660 268.160 ;
      RECT 10.840 267.900 11.660 268.160 ;
      RECT 4.315 273.940 5.335 274.220 ;
      RECT 5.615 273.940 6.635 274.220 ;
      RECT 6.915 273.940 7.935 274.220 ;
      RECT 8.215 273.940 9.235 274.220 ;
      RECT 9.515 273.940 10.535 274.220 ;
      RECT 4.840 268.400 5.660 268.660 ;
      RECT 5.840 268.400 6.660 268.660 ;
      RECT 6.840 268.400 7.660 268.660 ;
      RECT 7.840 268.400 8.660 268.660 ;
      RECT 8.840 268.400 9.660 268.660 ;
      RECT 4.840 268.900 5.660 269.160 ;
      RECT 3.315 277.795 3.685 278.165 ;
      RECT 3.315 279.595 3.685 279.965 ;
      RECT 3.315 282.845 3.685 283.215 ;
      RECT 3.315 247.645 3.685 248.015 ;
      RECT 13.840 269.400 14.660 269.660 ;
      RECT 13.415 274.590 14.435 274.870 ;
      RECT 14.715 274.590 15.735 274.870 ;
      RECT 16.015 274.590 17.035 274.870 ;
      RECT 17.315 274.590 18.335 274.870 ;
      RECT 18.615 274.590 19.635 274.870 ;
      RECT 19.915 274.590 20.935 274.870 ;
      RECT 14.840 268.900 15.660 269.160 ;
      RECT 15.840 268.900 16.660 269.160 ;
      RECT 16.840 268.900 17.660 269.160 ;
      RECT 17.840 268.900 18.660 269.160 ;
      RECT 18.840 268.900 19.660 269.160 ;
      RECT 19.840 268.900 20.660 269.160 ;
      RECT 13.415 272.640 14.435 272.920 ;
      RECT 14.715 272.640 15.735 272.920 ;
      RECT 12.115 273.290 13.135 273.570 ;
      RECT 13.415 273.290 14.435 273.570 ;
      RECT 14.715 273.290 15.735 273.570 ;
      RECT 16.015 273.290 17.035 273.570 ;
      RECT 17.315 273.290 18.335 273.570 ;
      RECT 18.615 273.290 19.635 273.570 ;
      RECT 19.915 273.290 20.935 273.570 ;
      RECT 15.840 268.400 16.660 268.660 ;
      RECT 16.840 268.400 17.660 268.660 ;
      RECT 17.840 268.400 18.660 268.660 ;
      RECT 18.840 268.400 19.660 268.660 ;
      RECT 19.840 268.400 20.660 268.660 ;
      RECT 20.840 268.400 21.660 268.660 ;
      RECT 16.015 272.640 17.035 272.920 ;
      RECT 17.315 272.640 18.335 272.920 ;
      RECT 18.615 272.640 19.635 272.920 ;
      RECT 19.915 272.640 20.935 272.920 ;
      RECT 20.840 268.900 21.660 269.160 ;
      RECT 13.840 267.900 14.660 268.160 ;
      RECT 14.840 267.900 15.660 268.160 ;
      RECT 15.840 267.900 16.660 268.160 ;
      RECT 16.840 267.900 17.660 268.160 ;
      RECT 14.840 269.400 15.660 269.660 ;
      RECT 15.840 269.400 16.660 269.660 ;
      RECT 16.840 269.400 17.660 269.660 ;
      RECT 17.840 269.400 18.660 269.660 ;
      RECT 18.840 269.400 19.660 269.660 ;
      RECT 19.840 269.400 20.660 269.660 ;
      RECT 20.840 269.400 21.660 269.660 ;
      RECT 20.840 267.900 21.660 268.160 ;
      RECT 17.840 267.900 18.660 268.160 ;
      RECT 11.840 267.900 12.660 268.160 ;
      RECT 18.840 267.900 19.660 268.160 ;
      RECT 12.840 267.900 13.660 268.160 ;
      RECT 19.915 273.940 20.935 274.220 ;
      RECT 19.840 267.900 20.660 268.160 ;
      RECT 11.840 268.900 12.660 269.160 ;
      RECT 12.840 268.900 13.660 269.160 ;
      RECT 13.840 268.900 14.660 269.160 ;
      RECT 12.115 273.940 13.135 274.220 ;
      RECT 11.840 268.400 12.660 268.660 ;
      RECT 12.840 268.400 13.660 268.660 ;
      RECT 13.415 273.940 14.435 274.220 ;
      RECT 13.840 268.400 14.660 268.660 ;
      RECT 14.840 268.400 15.660 268.660 ;
      RECT 14.715 273.940 15.735 274.220 ;
      RECT 11.840 269.400 12.660 269.660 ;
      RECT 16.015 273.940 17.035 274.220 ;
      RECT 12.840 269.400 13.660 269.660 ;
      RECT 17.315 273.940 18.335 274.220 ;
      RECT 12.115 272.640 13.135 272.920 ;
      RECT 12.115 274.590 13.135 274.870 ;
      RECT 18.615 273.940 19.635 274.220 ;
      RECT 7.055 166.510 7.425 166.880 ;
      RECT 5.015 206.745 5.385 207.115 ;
      RECT 7.055 174.665 7.425 175.035 ;
      RECT 2.895 166.510 3.265 166.880 ;
      RECT 4.565 190.720 4.935 191.090 ;
      RECT 2.065 198.595 2.435 198.965 ;
      RECT 2.895 182.565 3.265 182.935 ;
      RECT 2.895 174.665 3.265 175.035 ;
      RECT 4.565 198.595 4.935 198.965 ;
      RECT 2.065 190.720 2.435 191.090 ;
      RECT 2.215 206.745 2.585 207.115 ;
      RECT 7.055 182.565 7.425 182.935 ;
      RECT 37.815 204.245 38.185 204.615 ;
      RECT 29.115 198.595 29.485 198.965 ;
      RECT 33.375 182.565 33.745 182.935 ;
      RECT 29.215 166.510 29.585 166.880 ;
      RECT 33.375 166.510 33.745 166.880 ;
      RECT 27.815 206.745 28.185 207.115 ;
      RECT 33.375 174.665 33.745 175.035 ;
      RECT 37.815 219.295 38.185 219.665 ;
      RECT 37.815 188.220 38.185 188.590 ;
      RECT 37.815 180.065 38.185 180.435 ;
      RECT 37.815 196.095 38.185 196.465 ;
      RECT 30.615 206.745 30.985 207.115 ;
      RECT 25.065 190.720 25.435 191.090 ;
      RECT 29.215 182.565 29.585 182.935 ;
      RECT 37.815 172.165 38.185 172.535 ;
      RECT 25.065 198.595 25.435 198.965 ;
      RECT 27.565 190.720 27.935 191.090 ;
      RECT 37.815 234.345 38.185 234.715 ;
      RECT 29.215 174.665 29.585 175.035 ;
      RECT 27.565 198.595 27.935 198.965 ;
      RECT 19.215 65.325 19.585 65.695 ;
      RECT 23.375 65.325 23.745 65.695 ;
      RECT 37.815 70.725 38.185 71.095 ;
      RECT 2.895 73.225 3.265 73.595 ;
      RECT 7.055 73.225 7.425 73.595 ;
      RECT 19.215 73.225 19.585 73.595 ;
      RECT 23.375 73.225 23.745 73.595 ;
      RECT 37.815 78.880 38.185 79.250 ;
      RECT 2.895 81.380 3.265 81.750 ;
      RECT 7.055 81.380 7.425 81.750 ;
      RECT 19.215 81.380 19.585 81.750 ;
      RECT 23.375 81.380 23.745 81.750 ;
      RECT 37.815 86.780 38.185 87.150 ;
      RECT 2.895 89.280 3.265 89.650 ;
      RECT 7.055 89.280 7.425 89.650 ;
      RECT 19.215 89.280 19.585 89.650 ;
      RECT 23.375 89.280 23.745 89.650 ;
      RECT 37.815 94.935 38.185 95.305 ;
      RECT 2.065 97.435 2.435 97.805 ;
      RECT 4.565 97.435 4.935 97.805 ;
      RECT 15.065 97.435 15.435 97.805 ;
      RECT 17.565 97.435 17.935 97.805 ;
      RECT 37.815 102.810 38.185 103.180 ;
      RECT 2.065 105.310 2.435 105.680 ;
      RECT 4.565 105.310 4.935 105.680 ;
      RECT 15.065 105.310 15.435 105.680 ;
      RECT 17.565 105.310 17.935 105.680 ;
      RECT 19.115 105.310 19.485 105.680 ;
      RECT 37.815 110.960 38.185 111.330 ;
      RECT 2.215 113.460 2.585 113.830 ;
      RECT 5.015 113.460 5.385 113.830 ;
      RECT 16.615 113.460 16.985 113.830 ;
      RECT 19.415 113.460 19.785 113.830 ;
      RECT 37.815 126.010 38.185 126.380 ;
      RECT 5.600 128.895 6.000 136.095 ;
      RECT 2.000 128.495 6.000 128.895 ;
      RECT 7.200 128.895 7.600 136.095 ;
      RECT 6.400 128.495 7.600 128.895 ;
      RECT 8.800 128.895 9.200 136.095 ;
      RECT 8.000 128.495 9.200 128.895 ;
      RECT 10.400 128.895 10.800 136.095 ;
      RECT 9.600 128.495 10.800 128.895 ;
      RECT 12.000 128.895 12.400 136.095 ;
      RECT 11.200 128.495 12.400 128.895 ;
      RECT 13.600 128.895 14.000 136.095 ;
      RECT 12.800 128.495 14.000 128.895 ;
      RECT 15.200 128.895 15.600 136.095 ;
      RECT 14.400 128.495 15.600 128.895 ;
      RECT 5.600 136.095 6.800 136.495 ;
      RECT 6.400 128.895 6.800 136.095 ;
      RECT 7.200 136.095 8.400 136.495 ;
      RECT 8.000 128.895 8.400 136.095 ;
      RECT 8.800 136.095 10.000 136.495 ;
      RECT 9.600 128.895 10.000 136.095 ;
      RECT 10.400 136.095 11.600 136.495 ;
      RECT 11.200 128.895 11.600 136.095 ;
      RECT 12.000 136.095 13.200 136.495 ;
      RECT 12.800 128.895 13.200 136.095 ;
      RECT 13.600 136.095 14.800 136.495 ;
      RECT 14.400 128.895 14.800 136.095 ;
      RECT 16.000 128.495 20.000 128.895 ;
      RECT 15.200 136.095 16.400 136.495 ;
      RECT 16.000 128.895 16.400 136.095 ;
      RECT 37.815 141.060 38.185 141.430 ;
      RECT 37.815 156.110 38.185 156.480 ;
      RECT 2.895 158.610 3.265 158.980 ;
      RECT 7.055 158.610 7.425 158.980 ;
      RECT 29.215 158.610 29.585 158.980 ;
      RECT 33.375 158.610 33.745 158.980 ;
      RECT 37.815 164.010 38.185 164.380 ;
      RECT 1.315 6.280 1.685 6.650 ;
      RECT 33.815 10.965 34.135 11.285 ;
      RECT 33.875 7.785 34.075 10.965 ;
      RECT 33.815 7.465 34.135 7.785 ;
      RECT 3.130 14.445 3.450 14.765 ;
      RECT 3.190 10.125 3.390 14.445 ;
      RECT 3.130 9.805 3.450 10.125 ;
      RECT 34.230 19.105 34.550 19.425 ;
      RECT 34.290 15.925 34.490 19.105 ;
      RECT 34.230 15.605 34.550 15.925 ;
      RECT 7.835 22.020 8.205 22.390 ;
      RECT 20.795 22.020 21.165 22.390 ;
      RECT 2.100 6.315 4.965 6.515 ;
      RECT 4.965 6.255 5.285 6.575 ;
      RECT 2.100 18.265 2.300 22.645 ;
      RECT 2.040 17.945 2.360 18.265 ;
      RECT 2.100 6.515 2.300 17.945 ;
      RECT 2.100 22.645 3.320 22.845 ;
      RECT 3.320 22.585 3.640 22.905 ;
      RECT 7.220 23.670 7.590 24.040 ;
      RECT 18.090 26.110 18.460 26.480 ;
      RECT 19.460 23.115 19.660 27.345 ;
      RECT 19.400 22.795 19.720 23.115 ;
      RECT 19.460 27.345 20.355 27.545 ;
      RECT 20.355 27.285 20.675 27.605 ;
      RECT 4.515 27.760 4.885 28.130 ;
      RECT 17.475 27.760 17.845 28.130 ;
      RECT 7.835 30.160 8.205 30.530 ;
      RECT 20.795 30.160 21.165 30.530 ;
      RECT 5.005 30.685 5.325 30.745 ;
      RECT 5.325 30.745 6.220 30.945 ;
      RECT 6.020 27.355 6.220 30.745 ;
      RECT 5.960 27.035 6.280 27.355 ;
      RECT 5.005 30.745 5.325 31.005 ;
      RECT 7.220 31.810 7.590 32.180 ;
      RECT 18.090 34.250 18.460 34.620 ;
      RECT 19.460 31.255 19.660 35.485 ;
      RECT 19.400 30.935 19.720 31.255 ;
      RECT 19.460 35.485 20.355 35.685 ;
      RECT 20.355 35.425 20.675 35.745 ;
      RECT 4.515 35.900 4.885 36.270 ;
      RECT 17.475 35.900 17.845 36.270 ;
      RECT 7.835 38.300 8.205 38.670 ;
      RECT 20.795 38.300 21.165 38.670 ;
      RECT 5.005 38.825 5.325 38.885 ;
      RECT 5.325 38.885 6.220 39.085 ;
      RECT 6.020 35.495 6.220 38.885 ;
      RECT 5.960 35.175 6.280 35.495 ;
      RECT 5.005 38.885 5.325 39.145 ;
      RECT 7.220 39.950 7.590 40.320 ;
      RECT 18.090 42.390 18.460 42.760 ;
      RECT 19.460 39.395 19.660 43.625 ;
      RECT 19.400 39.075 19.720 39.395 ;
      RECT 19.460 43.625 20.355 43.825 ;
      RECT 20.355 43.565 20.675 43.885 ;
      RECT 4.515 44.040 4.885 44.410 ;
      RECT 17.475 44.040 17.845 44.410 ;
      RECT 7.835 46.440 8.205 46.810 ;
      RECT 20.795 46.440 21.165 46.810 ;
      RECT 5.005 46.965 5.325 47.025 ;
      RECT 5.325 47.025 6.220 47.225 ;
      RECT 6.020 43.635 6.220 47.025 ;
      RECT 5.960 43.315 6.280 43.635 ;
      RECT 5.005 47.025 5.325 47.285 ;
      RECT 7.220 48.090 7.590 48.460 ;
      RECT 18.090 50.530 18.460 50.900 ;
      RECT 19.460 47.535 19.660 51.765 ;
      RECT 19.400 47.215 19.720 47.535 ;
      RECT 19.460 51.765 20.355 51.965 ;
      RECT 20.355 51.705 20.675 52.025 ;
      RECT 4.515 52.180 4.885 52.550 ;
      RECT 17.475 52.180 17.845 52.550 ;
      RECT 4.755 55.045 5.125 55.415 ;
      RECT 6.020 51.775 6.220 55.415 ;
      RECT 5.960 51.455 6.280 51.775 ;
      RECT 6.020 55.415 8.330 55.615 ;
      RECT 8.330 55.355 8.650 55.675 ;
      RECT 35.300 4.100 36.100 58.260 ;
      RECT 36.500 4.100 37.300 58.260 ;
      RECT 37.815 62.825 38.185 63.195 ;
      RECT 2.895 65.325 3.265 65.695 ;
      RECT 7.055 65.325 7.425 65.695 ;
      RECT 63.340 133.590 64.160 133.850 ;
      RECT 63.340 134.090 64.160 134.350 ;
      RECT 63.340 134.590 64.160 134.850 ;
      RECT 63.340 135.090 64.160 135.350 ;
      RECT 63.165 138.330 64.185 138.610 ;
      RECT 63.165 138.980 64.185 139.260 ;
      RECT 63.165 139.630 64.185 139.910 ;
      RECT 63.165 140.280 64.185 140.560 ;
      RECT 84.315 123.435 84.685 123.805 ;
      RECT 73.565 138.330 74.585 138.610 ;
      RECT 73.565 138.980 74.585 139.260 ;
      RECT 73.565 139.630 74.585 139.910 ;
      RECT 73.565 140.280 74.585 140.560 ;
      RECT 75.340 133.590 76.160 133.850 ;
      RECT 76.340 133.590 77.160 133.850 ;
      RECT 77.340 133.590 78.160 133.850 ;
      RECT 78.340 133.590 79.160 133.850 ;
      RECT 79.340 133.590 80.160 133.850 ;
      RECT 80.340 133.590 81.160 133.850 ;
      RECT 81.340 133.590 82.160 133.850 ;
      RECT 82.340 133.590 83.160 133.850 ;
      RECT 83.340 133.590 84.315 133.850 ;
      RECT 84.315 133.535 84.685 133.905 ;
      RECT 74.340 134.090 75.160 134.350 ;
      RECT 75.340 134.090 76.160 134.350 ;
      RECT 76.340 134.090 77.160 134.350 ;
      RECT 77.340 134.090 78.160 134.350 ;
      RECT 78.340 134.090 79.160 134.350 ;
      RECT 79.340 134.090 80.160 134.350 ;
      RECT 80.340 134.090 81.160 134.350 ;
      RECT 81.340 134.090 82.160 134.350 ;
      RECT 82.340 134.090 83.160 134.350 ;
      RECT 74.340 134.590 75.160 134.850 ;
      RECT 75.340 134.590 76.160 134.850 ;
      RECT 76.340 134.590 77.160 134.850 ;
      RECT 77.340 134.590 78.160 134.850 ;
      RECT 78.340 134.590 79.160 134.850 ;
      RECT 79.340 134.590 80.160 134.850 ;
      RECT 80.340 134.590 81.160 134.850 ;
      RECT 81.340 134.590 82.160 134.850 ;
      RECT 82.340 134.590 83.160 134.850 ;
      RECT 83.370 134.060 83.630 134.880 ;
      RECT 74.340 135.090 75.160 135.350 ;
      RECT 75.340 135.090 76.160 135.350 ;
      RECT 76.340 135.090 77.160 135.350 ;
      RECT 77.340 135.090 78.160 135.350 ;
      RECT 78.340 135.090 79.160 135.350 ;
      RECT 79.340 135.090 80.160 135.350 ;
      RECT 80.340 135.090 81.160 135.350 ;
      RECT 81.340 135.090 82.160 135.350 ;
      RECT 82.340 135.090 83.160 135.350 ;
      RECT 83.340 135.090 84.315 135.350 ;
      RECT 84.315 135.035 84.685 135.405 ;
      RECT 84.315 125.235 84.685 125.605 ;
      RECT 74.865 138.330 75.885 138.610 ;
      RECT 76.165 138.330 77.185 138.610 ;
      RECT 77.465 138.330 78.485 138.610 ;
      RECT 78.765 138.330 79.785 138.610 ;
      RECT 80.065 138.330 81.085 138.610 ;
      RECT 81.365 138.330 82.385 138.610 ;
      RECT 82.665 138.330 83.685 138.610 ;
      RECT 84.315 128.785 84.685 129.155 ;
      RECT 74.865 138.980 75.885 139.260 ;
      RECT 76.165 138.980 77.185 139.260 ;
      RECT 77.465 138.980 78.485 139.260 ;
      RECT 78.765 138.980 79.785 139.260 ;
      RECT 80.065 138.980 81.085 139.260 ;
      RECT 81.365 138.980 82.385 139.260 ;
      RECT 82.665 138.980 83.685 139.260 ;
      RECT 84.315 130.285 84.685 130.655 ;
      RECT 74.865 139.630 75.885 139.910 ;
      RECT 76.165 139.630 77.185 139.910 ;
      RECT 77.465 139.630 78.485 139.910 ;
      RECT 78.765 139.630 79.785 139.910 ;
      RECT 80.065 139.630 81.085 139.910 ;
      RECT 81.365 139.630 82.385 139.910 ;
      RECT 82.665 139.630 83.685 139.910 ;
      RECT 74.340 133.590 75.160 133.850 ;
      RECT 74.865 140.280 75.885 140.560 ;
      RECT 76.165 140.280 77.185 140.560 ;
      RECT 77.465 140.280 78.485 140.560 ;
      RECT 78.765 140.280 79.785 140.560 ;
      RECT 80.065 140.280 81.085 140.560 ;
      RECT 81.365 140.280 82.385 140.560 ;
      RECT 82.665 140.280 83.685 140.560 ;
      RECT 81.615 144.370 81.985 144.740 ;
      RECT 84.365 145.425 84.735 145.795 ;
      RECT 80.365 146.420 80.625 146.570 ;
      RECT 80.335 143.605 80.655 146.420 ;
      RECT 80.310 143.235 80.680 143.605 ;
      RECT 82.125 146.940 82.495 149.005 ;
      RECT 81.615 152.770 81.985 153.140 ;
      RECT 84.365 153.825 84.735 154.195 ;
      RECT 80.365 154.820 80.625 154.970 ;
      RECT 80.335 152.005 80.655 154.820 ;
      RECT 80.310 151.635 80.680 152.005 ;
      RECT 82.125 155.340 82.495 157.405 ;
      RECT 64.465 138.330 65.485 138.610 ;
      RECT 65.765 138.330 66.785 138.610 ;
      RECT 67.065 138.330 68.085 138.610 ;
      RECT 68.365 138.330 69.385 138.610 ;
      RECT 69.665 138.330 70.685 138.610 ;
      RECT 70.965 138.330 71.985 138.610 ;
      RECT 72.265 138.330 73.285 138.610 ;
      RECT 64.340 134.590 65.160 134.850 ;
      RECT 65.340 134.590 66.160 134.850 ;
      RECT 66.340 134.590 67.160 134.850 ;
      RECT 67.340 134.590 68.160 134.850 ;
      RECT 68.340 134.590 69.160 134.850 ;
      RECT 69.340 134.590 70.160 134.850 ;
      RECT 70.340 134.590 71.160 134.850 ;
      RECT 71.340 134.590 72.160 134.850 ;
      RECT 64.465 138.980 65.485 139.260 ;
      RECT 65.765 138.980 66.785 139.260 ;
      RECT 67.065 138.980 68.085 139.260 ;
      RECT 68.365 138.980 69.385 139.260 ;
      RECT 69.665 138.980 70.685 139.260 ;
      RECT 70.965 138.980 71.985 139.260 ;
      RECT 72.265 138.980 73.285 139.260 ;
      RECT 72.340 134.590 73.160 134.850 ;
      RECT 73.340 134.590 74.160 134.850 ;
      RECT 73.340 133.590 74.160 133.850 ;
      RECT 64.340 134.090 65.160 134.350 ;
      RECT 65.340 134.090 66.160 134.350 ;
      RECT 66.340 134.090 67.160 134.350 ;
      RECT 67.340 134.090 68.160 134.350 ;
      RECT 68.340 134.090 69.160 134.350 ;
      RECT 64.465 139.630 65.485 139.910 ;
      RECT 65.765 139.630 66.785 139.910 ;
      RECT 67.065 139.630 68.085 139.910 ;
      RECT 68.365 139.630 69.385 139.910 ;
      RECT 69.665 139.630 70.685 139.910 ;
      RECT 70.965 139.630 71.985 139.910 ;
      RECT 72.265 139.630 73.285 139.910 ;
      RECT 69.340 134.090 70.160 134.350 ;
      RECT 70.340 134.090 71.160 134.350 ;
      RECT 71.340 134.090 72.160 134.350 ;
      RECT 72.340 134.090 73.160 134.350 ;
      RECT 64.340 135.090 65.160 135.350 ;
      RECT 65.340 135.090 66.160 135.350 ;
      RECT 66.340 135.090 67.160 135.350 ;
      RECT 67.340 135.090 68.160 135.350 ;
      RECT 64.465 140.280 65.485 140.560 ;
      RECT 65.765 140.280 66.785 140.560 ;
      RECT 67.065 140.280 68.085 140.560 ;
      RECT 68.365 140.280 69.385 140.560 ;
      RECT 69.665 140.280 70.685 140.560 ;
      RECT 70.965 140.280 71.985 140.560 ;
      RECT 72.265 140.280 73.285 140.560 ;
      RECT 68.340 135.090 69.160 135.350 ;
      RECT 69.340 135.090 70.160 135.350 ;
      RECT 70.340 135.090 71.160 135.350 ;
      RECT 71.340 135.090 72.160 135.350 ;
      RECT 72.340 135.090 73.160 135.350 ;
      RECT 73.340 135.090 74.160 135.350 ;
      RECT 73.340 134.090 74.160 134.350 ;
      RECT 64.340 133.590 65.160 133.850 ;
      RECT 65.340 133.590 66.160 133.850 ;
      RECT 66.340 133.590 67.160 133.850 ;
      RECT 67.340 133.590 68.160 133.850 ;
      RECT 68.340 133.590 69.160 133.850 ;
      RECT 69.340 133.590 70.160 133.850 ;
      RECT 70.340 133.590 71.160 133.850 ;
      RECT 71.340 133.590 72.160 133.850 ;
      RECT 72.340 133.590 73.160 133.850 ;
      RECT 80.935 101.665 80.960 101.995 ;
      RECT 80.915 108.085 81.285 108.455 ;
      RECT 81.240 101.665 81.265 101.995 ;
      RECT 80.960 101.650 81.240 108.085 ;
      RECT 79.135 102.265 79.160 102.595 ;
      RECT 79.115 109.085 79.485 109.455 ;
      RECT 79.440 102.265 79.465 102.595 ;
      RECT 79.160 102.250 79.440 109.085 ;
      RECT 81.560 94.855 81.840 94.870 ;
      RECT 81.535 94.525 81.865 94.855 ;
      RECT 81.560 85.195 81.840 94.525 ;
      RECT 81.515 84.825 81.885 85.195 ;
      RECT 78.535 103.435 78.560 103.765 ;
      RECT 78.515 110.085 78.885 110.455 ;
      RECT 78.840 103.435 78.865 103.765 ;
      RECT 78.560 103.420 78.840 110.085 ;
      RECT 75.985 89.825 76.355 90.195 ;
      RECT 79.760 95.505 80.040 95.520 ;
      RECT 79.735 95.175 80.065 95.505 ;
      RECT 79.760 87.195 80.040 95.175 ;
      RECT 79.715 86.825 80.085 87.195 ;
      RECT 84.315 113.335 84.685 113.705 ;
      RECT 75.985 104.395 76.355 104.765 ;
      RECT 82.735 102.785 82.760 103.115 ;
      RECT 82.715 106.085 83.085 106.455 ;
      RECT 83.040 102.785 83.065 103.115 ;
      RECT 82.760 102.770 83.040 106.085 ;
      RECT 77.960 94.335 78.240 94.350 ;
      RECT 77.935 94.005 78.265 94.335 ;
      RECT 77.960 88.195 78.240 94.005 ;
      RECT 77.915 87.825 78.285 88.195 ;
      RECT 84.315 115.135 84.685 115.505 ;
      RECT 80.360 93.735 80.640 93.750 ;
      RECT 80.335 93.405 80.665 93.735 ;
      RECT 80.360 86.195 80.640 93.405 ;
      RECT 80.315 85.825 80.685 86.195 ;
      RECT 83.360 91.035 83.640 91.050 ;
      RECT 83.335 90.705 83.665 91.035 ;
      RECT 83.360 84.195 83.640 90.705 ;
      RECT 83.315 83.825 83.685 84.195 ;
      RECT 84.315 118.385 84.685 118.755 ;
      RECT 84.315 120.185 84.685 120.555 ;
      RECT 82.135 98.965 82.160 99.295 ;
      RECT 82.115 107.085 82.485 107.455 ;
      RECT 82.440 98.965 82.465 99.295 ;
      RECT 82.160 98.950 82.440 107.085 ;
      RECT 57.965 138.330 58.985 138.610 ;
      RECT 59.265 138.330 60.285 138.610 ;
      RECT 60.565 138.330 61.585 138.610 ;
      RECT 51.465 139.630 52.485 139.910 ;
      RECT 52.765 139.630 53.785 139.910 ;
      RECT 54.065 139.630 55.085 139.910 ;
      RECT 55.365 139.630 56.385 139.910 ;
      RECT 56.665 139.630 57.685 139.910 ;
      RECT 57.965 139.630 58.985 139.910 ;
      RECT 59.265 139.630 60.285 139.910 ;
      RECT 60.565 139.630 61.585 139.910 ;
      RECT 61.865 139.630 62.885 139.910 ;
      RECT 61.865 138.330 62.885 138.610 ;
      RECT 61.340 135.090 62.160 135.350 ;
      RECT 62.340 135.090 63.160 135.350 ;
      RECT 49.815 133.535 50.185 133.905 ;
      RECT 49.815 128.785 50.185 129.155 ;
      RECT 59.340 134.090 60.160 134.350 ;
      RECT 60.340 134.090 61.160 134.350 ;
      RECT 61.340 134.090 62.160 134.350 ;
      RECT 62.340 134.090 63.160 134.350 ;
      RECT 49.815 123.435 50.185 123.805 ;
      RECT 49.815 113.335 50.185 113.705 ;
      RECT 59.340 133.590 60.160 133.850 ;
      RECT 60.340 133.590 61.160 133.850 ;
      RECT 61.340 133.590 62.160 133.850 ;
      RECT 62.340 133.590 63.160 133.850 ;
      RECT 58.870 133.560 59.130 134.380 ;
      RECT 51.465 140.280 52.485 140.560 ;
      RECT 52.765 140.280 53.785 140.560 ;
      RECT 54.065 140.280 55.085 140.560 ;
      RECT 55.365 140.280 56.385 140.560 ;
      RECT 56.665 140.280 57.685 140.560 ;
      RECT 57.965 140.280 58.985 140.560 ;
      RECT 59.265 140.280 60.285 140.560 ;
      RECT 60.565 140.280 61.585 140.560 ;
      RECT 61.865 140.280 62.885 140.560 ;
      RECT 59.340 134.590 60.160 134.850 ;
      RECT 49.815 138.285 50.185 138.655 ;
      RECT 51.465 138.980 52.485 139.260 ;
      RECT 52.765 138.980 53.785 139.260 ;
      RECT 54.065 138.980 55.085 139.260 ;
      RECT 55.365 138.980 56.385 139.260 ;
      RECT 56.665 138.980 57.685 139.260 ;
      RECT 57.965 138.980 58.985 139.260 ;
      RECT 59.265 138.980 60.285 139.260 ;
      RECT 60.565 138.980 61.585 139.260 ;
      RECT 61.865 138.980 62.885 139.260 ;
      RECT 60.340 134.590 61.160 134.850 ;
      RECT 61.340 134.590 62.160 134.850 ;
      RECT 62.340 134.590 63.160 134.850 ;
      RECT 52.415 125.235 52.785 125.605 ;
      RECT 49.815 118.385 50.185 118.755 ;
      RECT 59.340 135.090 60.160 135.350 ;
      RECT 58.870 134.560 59.130 135.380 ;
      RECT 60.340 135.090 61.160 135.350 ;
      RECT 51.465 138.330 52.485 138.610 ;
      RECT 52.765 138.330 53.785 138.610 ;
      RECT 54.065 138.330 55.085 138.610 ;
      RECT 55.365 138.330 56.385 138.610 ;
      RECT 56.665 138.330 57.685 138.610 ;
      RECT 80.365 15.750 80.625 15.900 ;
      RECT 80.335 12.935 80.655 15.750 ;
      RECT 80.310 12.565 80.680 12.935 ;
      RECT 82.125 16.270 82.495 18.335 ;
      RECT 81.615 38.900 81.985 39.270 ;
      RECT 80.365 40.950 80.625 41.100 ;
      RECT 80.335 38.135 80.655 40.950 ;
      RECT 80.310 37.765 80.680 38.135 ;
      RECT 75.985 60.565 76.355 60.935 ;
      RECT 83.360 61.775 83.640 61.790 ;
      RECT 83.335 61.445 83.665 61.775 ;
      RECT 83.360 54.935 83.640 61.445 ;
      RECT 83.315 54.565 83.685 54.935 ;
      RECT 82.125 7.870 82.495 9.935 ;
      RECT 82.125 41.470 82.495 43.535 ;
      RECT 79.760 66.245 80.040 66.260 ;
      RECT 79.735 65.915 80.065 66.245 ;
      RECT 79.760 57.935 80.040 65.915 ;
      RECT 79.715 57.565 80.085 57.935 ;
      RECT 81.615 5.300 81.985 5.670 ;
      RECT 81.615 22.100 81.985 22.470 ;
      RECT 80.365 24.150 80.625 24.300 ;
      RECT 80.335 21.335 80.655 24.150 ;
      RECT 80.310 20.965 80.680 21.335 ;
      RECT 84.365 31.555 84.735 31.925 ;
      RECT 80.365 7.350 80.625 7.500 ;
      RECT 80.335 4.535 80.655 7.350 ;
      RECT 80.310 4.165 80.680 4.535 ;
      RECT 80.360 64.475 80.640 64.490 ;
      RECT 80.335 64.145 80.665 64.475 ;
      RECT 80.360 56.935 80.640 64.145 ;
      RECT 80.315 56.565 80.685 56.935 ;
      RECT 77.960 65.075 78.240 65.090 ;
      RECT 77.935 64.745 78.265 65.075 ;
      RECT 77.960 58.935 78.240 64.745 ;
      RECT 77.915 58.565 78.285 58.935 ;
      RECT 81.560 65.595 81.840 65.610 ;
      RECT 81.535 65.265 81.865 65.595 ;
      RECT 81.560 55.935 81.840 65.265 ;
      RECT 81.515 55.565 81.885 55.935 ;
      RECT 84.365 39.955 84.735 40.325 ;
      RECT 82.125 24.670 82.495 26.735 ;
      RECT 84.365 14.755 84.735 15.125 ;
      RECT 81.615 13.700 81.985 14.070 ;
      RECT 81.615 30.500 81.985 30.870 ;
      RECT 75.985 75.135 76.355 75.505 ;
      RECT 82.735 73.525 82.760 73.855 ;
      RECT 82.715 76.825 83.085 77.195 ;
      RECT 83.040 73.525 83.065 73.855 ;
      RECT 82.760 73.510 83.040 76.825 ;
      RECT 82.135 69.705 82.160 70.035 ;
      RECT 82.115 77.825 82.485 78.195 ;
      RECT 82.440 69.705 82.465 70.035 ;
      RECT 82.160 69.690 82.440 77.825 ;
      RECT 80.935 72.405 80.960 72.735 ;
      RECT 80.915 78.825 81.285 79.195 ;
      RECT 81.240 72.405 81.265 72.735 ;
      RECT 80.960 72.390 81.240 78.825 ;
      RECT 80.365 32.550 80.625 32.700 ;
      RECT 80.335 29.735 80.655 32.550 ;
      RECT 80.310 29.365 80.680 29.735 ;
      RECT 79.135 73.005 79.160 73.335 ;
      RECT 79.115 79.825 79.485 80.195 ;
      RECT 79.440 73.005 79.465 73.335 ;
      RECT 79.160 72.990 79.440 79.825 ;
      RECT 78.535 74.175 78.560 74.505 ;
      RECT 78.515 80.825 78.885 81.195 ;
      RECT 78.840 74.175 78.865 74.505 ;
      RECT 78.560 74.160 78.840 80.825 ;
      RECT 81.615 47.300 81.985 47.670 ;
      RECT 84.365 23.155 84.735 23.525 ;
      RECT 84.365 48.355 84.735 48.725 ;
      RECT 80.365 49.350 80.625 49.500 ;
      RECT 80.335 46.535 80.655 49.350 ;
      RECT 80.310 46.165 80.680 46.535 ;
      RECT 82.125 33.070 82.495 35.135 ;
      RECT 82.125 49.870 82.495 51.935 ;
      RECT 84.365 6.355 84.735 6.725 ;
    LAYER met3 ;
      RECT 43.100 75.070 74.000 75.570 ;
      RECT 75.000 75.070 76.420 75.570 ;
      RECT 74.000 74.820 75.000 75.820 ;
      RECT 43.100 104.330 74.000 104.830 ;
      RECT 75.000 104.330 76.420 104.830 ;
      RECT 74.000 104.080 75.000 105.080 ;
      RECT 43.100 125.170 48.000 125.670 ;
      RECT 49.000 125.170 52.850 125.670 ;
      RECT 48.000 124.920 49.000 125.920 ;
      RECT 6.990 166.445 7.490 166.945 ;
      RECT 7.040 163.945 7.440 166.445 ;
      RECT 1.300 163.945 7.040 164.445 ;
      RECT 29.150 166.445 29.650 166.945 ;
      RECT 29.200 162.945 29.600 166.445 ;
      RECT 1.300 162.945 29.200 163.445 ;
      RECT 33.310 166.445 33.810 166.945 ;
      RECT 33.360 161.945 33.760 166.445 ;
      RECT 1.300 161.945 33.360 162.445 ;
      RECT 43.100 180.540 74.000 181.040 ;
      RECT 75.000 180.540 76.420 181.040 ;
      RECT 74.000 180.290 75.000 181.290 ;
      RECT 43.100 226.600 74.000 227.100 ;
      RECT 75.000 226.600 76.420 227.100 ;
      RECT 74.000 226.350 75.000 227.350 ;
      RECT 43.100 272.660 74.000 273.160 ;
      RECT 75.000 272.660 76.420 273.160 ;
      RECT 74.000 272.410 75.000 273.410 ;
      RECT 43.100 318.720 74.000 319.220 ;
      RECT 75.000 318.720 76.420 319.220 ;
      RECT 74.000 318.470 75.000 319.470 ;
      RECT 80.850 184.230 86.700 184.730 ;
      RECT 79.050 185.230 86.700 185.730 ;
      RECT 78.450 186.230 86.700 186.730 ;
      RECT 80.245 189.230 86.700 189.730 ;
      RECT 45.100 190.365 78.500 190.865 ;
      RECT 79.500 190.365 82.050 190.865 ;
      RECT 78.500 190.115 79.500 191.115 ;
      RECT 84.300 191.420 86.700 191.920 ;
      RECT 82.060 194.630 86.700 195.130 ;
      RECT 80.245 197.630 86.700 198.130 ;
      RECT 45.100 198.765 78.500 199.265 ;
      RECT 79.500 198.765 82.050 199.265 ;
      RECT 78.500 198.515 79.500 199.515 ;
      RECT 84.300 199.820 86.700 200.320 ;
      RECT 82.060 203.030 86.700 203.530 ;
      RECT 83.250 206.030 86.700 206.530 ;
      RECT 81.450 207.030 86.700 207.530 ;
      RECT 80.250 208.030 86.700 208.530 ;
      RECT 79.650 209.030 86.700 209.530 ;
      RECT 77.850 210.030 86.700 210.530 ;
      RECT 45.100 212.030 74.000 212.530 ;
      RECT 75.000 212.030 76.420 212.530 ;
      RECT 74.000 211.780 75.000 212.780 ;
      RECT 45.100 165.970 74.000 166.470 ;
      RECT 75.000 165.970 76.420 166.470 ;
      RECT 74.000 165.720 75.000 166.720 ;
      RECT 82.650 228.290 86.700 228.790 ;
      RECT 82.050 229.290 86.700 229.790 ;
      RECT 80.850 230.290 86.700 230.790 ;
      RECT 79.050 231.290 86.700 231.790 ;
      RECT 78.450 232.290 86.700 232.790 ;
      RECT 80.245 235.290 86.700 235.790 ;
      RECT 45.100 236.425 78.500 236.925 ;
      RECT 79.500 236.425 82.050 236.925 ;
      RECT 78.500 236.175 79.500 237.175 ;
      RECT 84.300 237.480 86.700 237.980 ;
      RECT 82.060 240.690 86.700 241.190 ;
      RECT 80.245 243.690 86.700 244.190 ;
      RECT 45.100 244.825 78.500 245.325 ;
      RECT 79.500 244.825 82.050 245.325 ;
      RECT 78.500 244.575 79.500 245.575 ;
      RECT 84.300 245.880 86.700 246.380 ;
      RECT 82.060 249.090 86.700 249.590 ;
      RECT 83.250 252.090 86.700 252.590 ;
      RECT 81.450 253.090 86.700 253.590 ;
      RECT 80.250 254.090 86.700 254.590 ;
      RECT 79.650 255.090 86.700 255.590 ;
      RECT 77.850 256.090 86.700 256.590 ;
      RECT 45.100 258.090 74.000 258.590 ;
      RECT 75.000 258.090 76.420 258.590 ;
      RECT 74.000 257.840 75.000 258.840 ;
      RECT 82.650 182.230 86.700 182.730 ;
      RECT 82.650 274.350 86.700 274.850 ;
      RECT 82.050 275.350 86.700 275.850 ;
      RECT 80.850 276.350 86.700 276.850 ;
      RECT 79.050 277.350 86.700 277.850 ;
      RECT 78.450 278.350 86.700 278.850 ;
      RECT 80.245 281.350 86.700 281.850 ;
      RECT 45.100 282.485 78.500 282.985 ;
      RECT 79.500 282.485 82.050 282.985 ;
      RECT 78.500 282.235 79.500 283.235 ;
      RECT 84.300 283.540 86.700 284.040 ;
      RECT 82.060 286.750 86.700 287.250 ;
      RECT 80.245 289.750 86.700 290.250 ;
      RECT 45.100 290.885 78.500 291.385 ;
      RECT 79.500 290.885 82.050 291.385 ;
      RECT 78.500 290.635 79.500 291.635 ;
      RECT 84.300 291.940 86.700 292.440 ;
      RECT 82.060 295.150 86.700 295.650 ;
      RECT 83.250 298.150 86.700 298.650 ;
      RECT 81.450 299.150 86.700 299.650 ;
      RECT 80.250 300.150 86.700 300.650 ;
      RECT 79.650 301.150 86.700 301.650 ;
      RECT 77.850 302.150 86.700 302.650 ;
      RECT 45.100 304.150 74.000 304.650 ;
      RECT 75.000 304.150 76.420 304.650 ;
      RECT 74.000 303.900 75.000 304.900 ;
      RECT 82.050 183.230 86.700 183.730 ;
      RECT 82.650 320.410 86.700 320.910 ;
      RECT 82.050 321.410 86.700 321.910 ;
      RECT 80.850 322.410 86.700 322.910 ;
      RECT 79.050 323.410 86.700 323.910 ;
      RECT 78.450 324.410 86.700 324.910 ;
      RECT 29.150 182.500 29.650 183.000 ;
      RECT 29.200 179.000 29.600 182.500 ;
      RECT 1.300 179.000 29.200 179.500 ;
      RECT 33.310 182.500 33.810 183.000 ;
      RECT 33.360 178.000 33.760 182.500 ;
      RECT 1.300 178.000 33.360 178.500 ;
      RECT 21.885 272.615 22.865 272.945 ;
      RECT 27.750 206.680 28.250 207.180 ;
      RECT 27.800 203.180 28.200 206.680 ;
      RECT 1.300 203.180 27.800 203.680 ;
      RECT 21.885 273.265 22.865 273.595 ;
      RECT 21.885 273.915 22.865 274.245 ;
      RECT 30.550 206.680 31.050 207.180 ;
      RECT 30.600 202.180 31.000 206.680 ;
      RECT 1.300 202.180 30.600 202.680 ;
      RECT 21.885 274.565 22.865 274.895 ;
      RECT 29.150 174.600 29.650 175.100 ;
      RECT 29.200 171.100 29.600 174.600 ;
      RECT 1.300 171.100 29.200 171.600 ;
      RECT 33.310 174.600 33.810 175.100 ;
      RECT 33.360 170.100 33.760 174.600 ;
      RECT 1.300 170.100 33.360 170.600 ;
      RECT 27.750 221.730 28.250 222.230 ;
      RECT 27.800 218.230 28.200 221.730 ;
      RECT 1.300 218.230 27.800 218.730 ;
      RECT 30.550 221.730 31.050 222.230 ;
      RECT 30.600 217.230 31.000 221.730 ;
      RECT 1.300 217.230 30.600 217.730 ;
      RECT 25.000 190.655 25.500 191.155 ;
      RECT 25.050 187.155 25.450 190.655 ;
      RECT 1.300 187.155 25.050 187.655 ;
      RECT 27.500 190.655 28.000 191.155 ;
      RECT 27.550 186.155 27.950 190.655 ;
      RECT 1.300 186.155 27.550 186.655 ;
      RECT 21.885 302.765 22.865 303.095 ;
      RECT 21.885 303.415 22.865 303.745 ;
      RECT 21.885 304.065 22.865 304.395 ;
      RECT 21.885 304.715 22.865 305.045 ;
      RECT 25.000 198.530 25.500 199.030 ;
      RECT 25.050 195.030 25.450 198.530 ;
      RECT 1.300 195.030 25.050 195.530 ;
      RECT 2.200 235.280 2.600 236.830 ;
      RECT 1.300 235.280 2.200 235.780 ;
      RECT 27.800 233.280 28.200 236.830 ;
      RECT 1.300 233.280 27.800 233.780 ;
      RECT 5.600 237.230 6.000 244.430 ;
      RECT 2.000 236.830 6.000 237.230 ;
      RECT 5.000 234.780 5.400 236.830 ;
      RECT 1.300 234.280 5.400 234.780 ;
      RECT 7.200 237.230 7.600 244.430 ;
      RECT 6.400 236.830 7.600 237.230 ;
      RECT 8.800 237.230 9.200 244.430 ;
      RECT 8.000 236.830 9.200 237.230 ;
      RECT 10.400 237.230 10.800 244.430 ;
      RECT 9.600 236.830 10.800 237.230 ;
      RECT 12.000 237.230 12.400 244.430 ;
      RECT 11.200 236.830 12.400 237.230 ;
      RECT 13.600 237.230 14.000 244.430 ;
      RECT 12.800 236.830 14.000 237.230 ;
      RECT 15.200 237.230 15.600 244.430 ;
      RECT 14.400 236.830 15.600 237.230 ;
      RECT 16.800 237.230 17.200 244.430 ;
      RECT 16.000 236.830 17.200 237.230 ;
      RECT 18.400 237.230 18.800 244.430 ;
      RECT 17.600 236.830 18.800 237.230 ;
      RECT 20.000 237.230 20.400 244.430 ;
      RECT 19.200 236.830 20.400 237.230 ;
      RECT 21.600 237.230 22.000 244.430 ;
      RECT 20.800 236.830 22.000 237.230 ;
      RECT 23.200 237.230 23.600 244.430 ;
      RECT 22.400 236.830 23.600 237.230 ;
      RECT 24.800 237.230 25.200 244.430 ;
      RECT 24.000 236.830 25.200 237.230 ;
      RECT 26.400 237.230 26.800 244.430 ;
      RECT 25.600 236.830 26.800 237.230 ;
      RECT 5.600 244.430 6.800 244.830 ;
      RECT 6.400 237.230 6.800 244.430 ;
      RECT 7.200 244.430 8.400 244.830 ;
      RECT 8.000 237.230 8.400 244.430 ;
      RECT 8.800 244.430 10.000 244.830 ;
      RECT 9.600 237.230 10.000 244.430 ;
      RECT 10.400 244.430 11.600 244.830 ;
      RECT 11.200 237.230 11.600 244.430 ;
      RECT 12.000 244.430 13.200 244.830 ;
      RECT 12.800 237.230 13.200 244.430 ;
      RECT 13.600 244.430 14.800 244.830 ;
      RECT 14.400 237.230 14.800 244.430 ;
      RECT 15.200 244.430 16.400 244.830 ;
      RECT 16.000 237.230 16.400 244.430 ;
      RECT 16.800 244.430 18.000 244.830 ;
      RECT 17.600 237.230 18.000 244.430 ;
      RECT 18.400 244.430 19.600 244.830 ;
      RECT 19.200 237.230 19.600 244.430 ;
      RECT 20.000 244.430 21.200 244.830 ;
      RECT 20.800 237.230 21.200 244.430 ;
      RECT 21.600 244.430 22.800 244.830 ;
      RECT 22.400 237.230 22.800 244.430 ;
      RECT 23.200 244.430 24.400 244.830 ;
      RECT 24.000 237.230 24.400 244.430 ;
      RECT 24.800 244.430 26.000 244.830 ;
      RECT 25.600 237.230 26.000 244.430 ;
      RECT 27.600 236.830 31.200 237.230 ;
      RECT 30.600 232.280 31.000 236.830 ;
      RECT 1.300 232.280 30.600 232.780 ;
      RECT 26.400 244.430 27.600 244.830 ;
      RECT 27.200 236.830 27.600 244.430 ;
      RECT 27.500 198.530 28.000 199.030 ;
      RECT 27.550 194.030 27.950 198.530 ;
      RECT 1.300 194.030 27.550 194.530 ;
      RECT 40.000 287.830 41.900 288.330 ;
      RECT 37.750 287.830 39.000 288.330 ;
      RECT 39.000 287.580 40.000 288.580 ;
      RECT 35.150 289.630 39.000 290.130 ;
      RECT 40.000 289.630 43.900 290.130 ;
      RECT 39.000 289.380 40.000 290.380 ;
      RECT 40.000 293.180 41.900 293.680 ;
      RECT 37.750 293.180 39.000 293.680 ;
      RECT 39.000 292.930 40.000 293.930 ;
      RECT 40.000 297.930 41.900 298.430 ;
      RECT 37.750 297.930 39.000 298.430 ;
      RECT 39.000 297.680 40.000 298.680 ;
      RECT 33.585 302.765 34.565 303.095 ;
      RECT 34.885 302.765 35.865 303.095 ;
      RECT 40.000 302.680 41.900 303.180 ;
      RECT 37.750 302.680 39.000 303.180 ;
      RECT 39.000 302.430 40.000 303.430 ;
      RECT 33.585 303.415 34.565 303.745 ;
      RECT 34.885 303.415 35.865 303.745 ;
      RECT 36.185 302.765 36.515 303.745 ;
      RECT 33.585 304.065 34.565 304.395 ;
      RECT 34.885 304.065 35.865 304.395 ;
      RECT 33.585 304.715 34.565 305.045 ;
      RECT 34.885 304.715 35.865 305.045 ;
      RECT 36.185 304.065 36.515 305.045 ;
      RECT 40.000 307.880 41.900 308.380 ;
      RECT 37.750 307.880 39.000 308.380 ;
      RECT 39.000 307.630 40.000 308.630 ;
      RECT 40.000 312.930 41.900 313.430 ;
      RECT 37.750 312.930 39.000 313.430 ;
      RECT 39.000 312.680 40.000 313.680 ;
      RECT 40.000 317.980 41.900 318.480 ;
      RECT 37.750 317.980 39.000 318.480 ;
      RECT 39.000 317.730 40.000 318.730 ;
      RECT 35.150 319.780 39.000 320.280 ;
      RECT 40.000 319.780 43.900 320.280 ;
      RECT 39.000 319.530 40.000 320.530 ;
      RECT 40.000 323.330 41.900 323.830 ;
      RECT 37.750 323.330 39.000 323.830 ;
      RECT 39.000 323.080 40.000 324.080 ;
      RECT 29.685 303.415 30.665 303.745 ;
      RECT 30.985 303.415 31.965 303.745 ;
      RECT 32.285 303.415 33.265 303.745 ;
      RECT 27.085 302.765 28.065 303.095 ;
      RECT 28.385 302.765 29.365 303.095 ;
      RECT 29.685 302.765 30.665 303.095 ;
      RECT 23.185 304.065 24.165 304.395 ;
      RECT 24.485 304.065 25.465 304.395 ;
      RECT 25.785 304.065 26.765 304.395 ;
      RECT 27.085 304.065 28.065 304.395 ;
      RECT 28.385 304.065 29.365 304.395 ;
      RECT 29.685 304.065 30.665 304.395 ;
      RECT 30.985 304.065 31.965 304.395 ;
      RECT 32.285 304.065 33.265 304.395 ;
      RECT 30.985 302.765 31.965 303.095 ;
      RECT 32.285 302.765 33.265 303.095 ;
      RECT 23.185 304.715 24.165 305.045 ;
      RECT 24.485 304.715 25.465 305.045 ;
      RECT 25.785 304.715 26.765 305.045 ;
      RECT 27.085 304.715 28.065 305.045 ;
      RECT 28.385 304.715 29.365 305.045 ;
      RECT 29.685 304.715 30.665 305.045 ;
      RECT 30.985 304.715 31.965 305.045 ;
      RECT 32.285 304.715 33.265 305.045 ;
      RECT 23.185 302.765 24.165 303.095 ;
      RECT 24.485 302.765 25.465 303.095 ;
      RECT 25.785 302.765 26.765 303.095 ;
      RECT 23.185 303.415 24.165 303.745 ;
      RECT 24.485 303.415 25.465 303.745 ;
      RECT 25.785 303.415 26.765 303.745 ;
      RECT 27.085 303.415 28.065 303.745 ;
      RECT 28.385 303.415 29.365 303.745 ;
      RECT 29.685 274.565 30.665 274.895 ;
      RECT 30.985 274.565 31.965 274.895 ;
      RECT 32.285 274.565 33.265 274.895 ;
      RECT 23.185 272.615 24.165 272.945 ;
      RECT 23.185 273.265 24.165 273.595 ;
      RECT 32.285 272.615 33.265 272.945 ;
      RECT 24.485 272.615 25.465 272.945 ;
      RECT 24.485 273.265 25.465 273.595 ;
      RECT 25.785 272.615 26.765 272.945 ;
      RECT 25.785 273.265 26.765 273.595 ;
      RECT 27.085 272.615 28.065 272.945 ;
      RECT 27.085 273.265 28.065 273.595 ;
      RECT 28.385 272.615 29.365 272.945 ;
      RECT 29.685 272.615 30.665 272.945 ;
      RECT 28.385 273.265 29.365 273.595 ;
      RECT 29.685 273.265 30.665 273.595 ;
      RECT 30.985 273.265 31.965 273.595 ;
      RECT 32.285 273.265 33.265 273.595 ;
      RECT 23.185 273.915 24.165 274.245 ;
      RECT 24.485 273.915 25.465 274.245 ;
      RECT 25.785 273.915 26.765 274.245 ;
      RECT 27.085 273.915 28.065 274.245 ;
      RECT 28.385 273.915 29.365 274.245 ;
      RECT 29.685 273.915 30.665 274.245 ;
      RECT 30.985 273.915 31.965 274.245 ;
      RECT 30.985 272.615 31.965 272.945 ;
      RECT 32.285 273.915 33.265 274.245 ;
      RECT 23.185 274.565 24.165 274.895 ;
      RECT 24.485 274.565 25.465 274.895 ;
      RECT 25.785 274.565 26.765 274.895 ;
      RECT 27.085 274.565 28.065 274.895 ;
      RECT 28.385 274.565 29.365 274.895 ;
      RECT 40.000 277.730 41.900 278.230 ;
      RECT 37.750 277.730 39.000 278.230 ;
      RECT 39.000 277.480 40.000 278.480 ;
      RECT 40.000 282.780 41.900 283.280 ;
      RECT 37.750 282.780 39.000 283.280 ;
      RECT 39.000 282.530 40.000 283.530 ;
      RECT 36.185 272.615 36.515 273.595 ;
      RECT 35.150 259.480 39.000 259.980 ;
      RECT 40.000 259.480 43.900 259.980 ;
      RECT 39.000 259.230 40.000 260.230 ;
      RECT 40.000 257.680 41.900 258.180 ;
      RECT 37.750 257.680 39.000 258.180 ;
      RECT 39.000 257.430 40.000 258.430 ;
      RECT 33.585 273.265 34.565 273.595 ;
      RECT 34.885 273.265 35.865 273.595 ;
      RECT 33.585 273.915 34.565 274.245 ;
      RECT 34.885 273.915 35.865 274.245 ;
      RECT 40.000 263.030 41.900 263.530 ;
      RECT 37.750 263.030 39.000 263.530 ;
      RECT 39.000 262.780 40.000 263.780 ;
      RECT 33.585 274.565 34.565 274.895 ;
      RECT 34.885 274.565 35.865 274.895 ;
      RECT 36.185 273.915 36.515 274.895 ;
      RECT 40.000 247.580 41.900 248.080 ;
      RECT 37.750 247.580 39.000 248.080 ;
      RECT 39.000 247.330 40.000 248.330 ;
      RECT 40.000 267.780 41.900 268.280 ;
      RECT 37.750 267.780 39.000 268.280 ;
      RECT 39.000 267.530 40.000 268.530 ;
      RECT 34.885 272.615 35.865 272.945 ;
      RECT 40.000 272.530 41.900 273.030 ;
      RECT 37.750 272.530 39.000 273.030 ;
      RECT 39.000 272.280 40.000 273.280 ;
      RECT 33.585 272.615 34.565 272.945 ;
      RECT 40.000 252.630 41.900 253.130 ;
      RECT 37.750 252.630 39.000 253.130 ;
      RECT 39.000 252.380 40.000 253.380 ;
      RECT 11.485 272.615 12.465 272.945 ;
      RECT 11.485 302.765 12.465 303.095 ;
      RECT 11.485 273.915 12.465 274.245 ;
      RECT 11.485 303.415 12.465 303.745 ;
      RECT 11.485 304.065 12.465 304.395 ;
      RECT 11.485 274.565 12.465 274.895 ;
      RECT 11.485 304.715 12.465 305.045 ;
      RECT 11.485 273.265 12.465 273.595 ;
      RECT 20.585 302.765 21.565 303.095 ;
      RECT 12.785 302.765 13.765 303.095 ;
      RECT 14.085 302.765 15.065 303.095 ;
      RECT 12.785 303.415 13.765 303.745 ;
      RECT 14.085 303.415 15.065 303.745 ;
      RECT 15.385 303.415 16.365 303.745 ;
      RECT 16.685 303.415 17.665 303.745 ;
      RECT 17.985 303.415 18.965 303.745 ;
      RECT 19.285 303.415 20.265 303.745 ;
      RECT 20.585 303.415 21.565 303.745 ;
      RECT 15.385 302.765 16.365 303.095 ;
      RECT 12.785 304.065 13.765 304.395 ;
      RECT 14.085 304.065 15.065 304.395 ;
      RECT 15.385 304.065 16.365 304.395 ;
      RECT 16.685 304.065 17.665 304.395 ;
      RECT 17.985 304.065 18.965 304.395 ;
      RECT 19.285 304.065 20.265 304.395 ;
      RECT 20.585 304.065 21.565 304.395 ;
      RECT 16.685 302.765 17.665 303.095 ;
      RECT 17.985 302.765 18.965 303.095 ;
      RECT 12.785 304.715 13.765 305.045 ;
      RECT 14.085 304.715 15.065 305.045 ;
      RECT 15.385 304.715 16.365 305.045 ;
      RECT 16.685 304.715 17.665 305.045 ;
      RECT 17.985 304.715 18.965 305.045 ;
      RECT 19.285 304.715 20.265 305.045 ;
      RECT 20.585 304.715 21.565 305.045 ;
      RECT 19.285 302.765 20.265 303.095 ;
      RECT 4.985 304.065 5.965 304.395 ;
      RECT 6.285 304.065 7.265 304.395 ;
      RECT 7.585 304.065 8.565 304.395 ;
      RECT 8.885 304.065 9.865 304.395 ;
      RECT 10.185 304.065 11.165 304.395 ;
      RECT 4.985 302.765 5.965 303.095 ;
      RECT 6.285 302.765 7.265 303.095 ;
      RECT 7.585 302.765 8.565 303.095 ;
      RECT 3.750 302.765 4.665 303.095 ;
      RECT 1.300 302.680 3.750 303.180 ;
      RECT 4.985 303.415 5.965 303.745 ;
      RECT 6.285 303.415 7.265 303.745 ;
      RECT 7.585 303.415 8.565 303.745 ;
      RECT 8.885 303.415 9.865 303.745 ;
      RECT 10.185 303.415 11.165 303.745 ;
      RECT 4.985 304.715 5.965 305.045 ;
      RECT 6.285 304.715 7.265 305.045 ;
      RECT 7.585 304.715 8.565 305.045 ;
      RECT 8.885 304.715 9.865 305.045 ;
      RECT 10.185 304.715 11.165 305.045 ;
      RECT 8.885 302.765 9.865 303.095 ;
      RECT 10.185 302.765 11.165 303.095 ;
      RECT 1.300 287.830 3.750 288.330 ;
      RECT 1.300 289.630 3.750 290.130 ;
      RECT 1.300 293.180 3.750 293.680 ;
      RECT 1.300 294.680 3.750 295.180 ;
      RECT 1.300 297.930 3.750 298.430 ;
      RECT 1.300 299.430 3.750 299.930 ;
      RECT 4.335 303.415 4.665 304.395 ;
      RECT 3.750 304.715 4.665 305.045 ;
      RECT 1.300 304.630 3.750 305.130 ;
      RECT 1.300 307.880 3.750 308.380 ;
      RECT 1.300 309.680 3.750 310.180 ;
      RECT 1.300 312.930 3.750 313.430 ;
      RECT 1.300 314.730 3.750 315.230 ;
      RECT 1.300 317.980 3.750 318.480 ;
      RECT 1.300 319.780 3.750 320.280 ;
      RECT 1.300 323.330 3.750 323.830 ;
      RECT 1.300 324.830 3.750 325.330 ;
      RECT 7.585 272.615 8.565 272.945 ;
      RECT 4.985 274.565 5.965 274.895 ;
      RECT 6.285 274.565 7.265 274.895 ;
      RECT 7.585 274.565 8.565 274.895 ;
      RECT 8.885 274.565 9.865 274.895 ;
      RECT 10.185 274.565 11.165 274.895 ;
      RECT 1.300 252.630 3.750 253.130 ;
      RECT 1.300 263.030 3.750 263.530 ;
      RECT 1.300 249.380 3.750 249.880 ;
      RECT 1.300 264.530 3.750 265.030 ;
      RECT 1.300 267.780 3.750 268.280 ;
      RECT 1.300 254.430 3.750 254.930 ;
      RECT 1.300 269.280 3.750 269.780 ;
      RECT 4.985 272.615 5.965 272.945 ;
      RECT 1.300 284.580 3.750 285.080 ;
      RECT 1.300 257.680 3.750 258.180 ;
      RECT 10.185 272.615 11.165 272.945 ;
      RECT 1.300 279.530 3.750 280.030 ;
      RECT 1.300 247.580 3.750 248.080 ;
      RECT 4.335 273.265 4.665 274.245 ;
      RECT 4.985 273.265 5.965 273.595 ;
      RECT 6.285 273.265 7.265 273.595 ;
      RECT 7.585 273.265 8.565 273.595 ;
      RECT 8.885 273.265 9.865 273.595 ;
      RECT 10.185 273.265 11.165 273.595 ;
      RECT 4.985 273.915 5.965 274.245 ;
      RECT 6.285 273.915 7.265 274.245 ;
      RECT 7.585 273.915 8.565 274.245 ;
      RECT 8.885 273.915 9.865 274.245 ;
      RECT 10.185 273.915 11.165 274.245 ;
      RECT 1.300 282.780 3.750 283.280 ;
      RECT 1.300 277.730 3.750 278.230 ;
      RECT 1.300 259.480 3.750 259.980 ;
      RECT 3.750 272.615 4.665 272.945 ;
      RECT 1.300 272.530 3.750 273.030 ;
      RECT 3.750 274.565 4.665 274.895 ;
      RECT 1.300 274.480 3.750 274.980 ;
      RECT 8.885 272.615 9.865 272.945 ;
      RECT 6.285 272.615 7.265 272.945 ;
      RECT 16.685 274.565 17.665 274.895 ;
      RECT 17.985 274.565 18.965 274.895 ;
      RECT 19.285 274.565 20.265 274.895 ;
      RECT 20.585 274.565 21.565 274.895 ;
      RECT 12.785 272.615 13.765 272.945 ;
      RECT 12.785 274.565 13.765 274.895 ;
      RECT 14.085 274.565 15.065 274.895 ;
      RECT 12.785 273.915 13.765 274.245 ;
      RECT 14.085 273.915 15.065 274.245 ;
      RECT 15.385 273.915 16.365 274.245 ;
      RECT 12.785 273.265 13.765 273.595 ;
      RECT 17.985 272.615 18.965 272.945 ;
      RECT 16.685 273.915 17.665 274.245 ;
      RECT 14.085 273.265 15.065 273.595 ;
      RECT 14.085 272.615 15.065 272.945 ;
      RECT 15.385 272.615 16.365 272.945 ;
      RECT 15.385 273.265 16.365 273.595 ;
      RECT 17.985 273.915 18.965 274.245 ;
      RECT 19.285 273.915 20.265 274.245 ;
      RECT 16.685 273.265 17.665 273.595 ;
      RECT 20.585 273.915 21.565 274.245 ;
      RECT 17.985 273.265 18.965 273.595 ;
      RECT 19.285 273.265 20.265 273.595 ;
      RECT 19.285 272.615 20.265 272.945 ;
      RECT 20.585 272.615 21.565 272.945 ;
      RECT 20.585 273.265 21.565 273.595 ;
      RECT 16.685 272.615 17.665 272.945 ;
      RECT 15.385 274.565 16.365 274.895 ;
      RECT 2.000 190.655 2.500 191.155 ;
      RECT 2.050 189.655 2.450 190.655 ;
      RECT 1.300 189.155 2.450 189.655 ;
      RECT 2.830 182.500 3.330 183.000 ;
      RECT 2.880 181.000 3.280 182.500 ;
      RECT 1.300 181.000 2.880 181.500 ;
      RECT 6.990 182.500 7.490 183.000 ;
      RECT 7.040 180.000 7.440 182.500 ;
      RECT 1.300 180.000 7.040 180.500 ;
      RECT 4.950 221.730 5.450 222.230 ;
      RECT 5.000 219.230 5.400 221.730 ;
      RECT 1.300 219.230 5.000 219.730 ;
      RECT 2.150 206.680 2.650 207.180 ;
      RECT 2.200 205.680 2.600 206.680 ;
      RECT 1.300 205.180 2.600 205.680 ;
      RECT 2.000 198.530 2.500 199.030 ;
      RECT 2.050 197.530 2.450 198.530 ;
      RECT 1.300 197.030 2.450 197.530 ;
      RECT 4.500 198.530 5.000 199.030 ;
      RECT 4.550 196.030 4.950 198.530 ;
      RECT 1.300 196.030 4.550 196.530 ;
      RECT 2.830 166.445 3.330 166.945 ;
      RECT 2.880 164.945 3.280 166.445 ;
      RECT 1.300 164.945 2.880 165.445 ;
      RECT 4.500 190.655 5.000 191.155 ;
      RECT 4.550 188.155 4.950 190.655 ;
      RECT 1.300 188.155 4.550 188.655 ;
      RECT 2.830 174.600 3.330 175.100 ;
      RECT 2.880 173.100 3.280 174.600 ;
      RECT 1.300 173.100 2.880 173.600 ;
      RECT 6.990 174.600 7.490 175.100 ;
      RECT 7.040 172.100 7.440 174.600 ;
      RECT 1.300 172.100 7.040 172.600 ;
      RECT 2.150 221.730 2.650 222.230 ;
      RECT 2.200 220.730 2.600 221.730 ;
      RECT 1.300 220.230 2.600 220.730 ;
      RECT 4.950 206.680 5.450 207.180 ;
      RECT 5.000 204.180 5.400 206.680 ;
      RECT 1.300 204.180 5.000 204.680 ;
      RECT 40.000 172.100 41.900 172.600 ;
      RECT 37.750 172.100 39.000 172.600 ;
      RECT 39.000 171.850 40.000 172.850 ;
      RECT 40.000 180.000 41.900 180.500 ;
      RECT 37.750 180.000 39.000 180.500 ;
      RECT 39.000 179.750 40.000 180.750 ;
      RECT 40.000 196.030 41.900 196.530 ;
      RECT 37.750 196.030 39.000 196.530 ;
      RECT 39.000 195.780 40.000 196.780 ;
      RECT 40.000 234.280 41.900 234.780 ;
      RECT 37.750 234.280 39.000 234.780 ;
      RECT 39.000 234.030 40.000 235.030 ;
      RECT 40.000 188.155 41.900 188.655 ;
      RECT 37.750 188.155 39.000 188.655 ;
      RECT 39.000 187.905 40.000 188.905 ;
      RECT 29.050 198.530 39.000 199.030 ;
      RECT 40.000 198.530 43.900 199.030 ;
      RECT 39.000 198.280 40.000 199.280 ;
      RECT 40.000 219.230 41.900 219.730 ;
      RECT 37.750 219.230 39.000 219.730 ;
      RECT 39.000 218.980 40.000 219.980 ;
      RECT 40.000 204.180 41.900 204.680 ;
      RECT 37.750 204.180 39.000 204.680 ;
      RECT 39.000 203.930 40.000 204.930 ;
      RECT 40.000 110.895 41.900 111.395 ;
      RECT 37.750 110.895 39.000 111.395 ;
      RECT 39.000 110.645 40.000 111.645 ;
      RECT 2.150 113.395 2.650 113.895 ;
      RECT 2.200 112.395 2.600 113.395 ;
      RECT 1.300 111.895 2.600 112.395 ;
      RECT 4.950 113.395 5.450 113.895 ;
      RECT 5.000 110.895 5.400 113.395 ;
      RECT 1.300 110.895 5.000 111.395 ;
      RECT 16.550 113.395 17.050 113.895 ;
      RECT 16.600 109.895 17.000 113.395 ;
      RECT 1.300 109.895 16.600 110.395 ;
      RECT 19.350 113.395 19.850 113.895 ;
      RECT 19.400 108.895 19.800 113.395 ;
      RECT 1.300 108.895 19.400 109.395 ;
      RECT 36.650 10.545 39.000 11.045 ;
      RECT 40.000 10.545 43.900 11.045 ;
      RECT 39.000 10.295 40.000 11.295 ;
      RECT 40.000 125.945 41.900 126.445 ;
      RECT 37.750 125.945 39.000 126.445 ;
      RECT 39.000 125.695 40.000 126.695 ;
      RECT 2.150 128.445 2.650 128.945 ;
      RECT 2.200 127.445 2.600 128.445 ;
      RECT 1.300 126.945 2.600 127.445 ;
      RECT 4.950 128.445 5.450 128.945 ;
      RECT 5.000 125.945 5.400 128.445 ;
      RECT 1.300 125.945 5.000 126.445 ;
      RECT 16.550 128.445 17.050 128.945 ;
      RECT 16.600 124.945 17.000 128.445 ;
      RECT 1.300 124.945 16.600 125.445 ;
      RECT 19.350 128.445 19.850 128.945 ;
      RECT 19.400 123.945 19.800 128.445 ;
      RECT 1.300 123.945 19.400 124.445 ;
      RECT 40.000 140.995 41.900 141.495 ;
      RECT 37.750 140.995 39.000 141.495 ;
      RECT 39.000 140.745 40.000 141.745 ;
      RECT 2.200 141.995 2.600 143.545 ;
      RECT 1.300 141.995 2.200 142.495 ;
      RECT 16.600 139.995 17.000 143.545 ;
      RECT 1.300 139.995 16.600 140.495 ;
      RECT 5.600 143.945 6.000 151.145 ;
      RECT 2.000 143.545 6.000 143.945 ;
      RECT 5.000 141.495 5.400 143.545 ;
      RECT 1.300 140.995 5.400 141.495 ;
      RECT 7.200 143.945 7.600 151.145 ;
      RECT 6.400 143.545 7.600 143.945 ;
      RECT 8.800 143.945 9.200 151.145 ;
      RECT 8.000 143.545 9.200 143.945 ;
      RECT 10.400 143.945 10.800 151.145 ;
      RECT 9.600 143.545 10.800 143.945 ;
      RECT 12.000 143.945 12.400 151.145 ;
      RECT 11.200 143.545 12.400 143.945 ;
      RECT 13.600 143.945 14.000 151.145 ;
      RECT 12.800 143.545 14.000 143.945 ;
      RECT 15.200 143.945 15.600 151.145 ;
      RECT 14.400 143.545 15.600 143.945 ;
      RECT 5.600 151.145 6.800 151.545 ;
      RECT 6.400 143.945 6.800 151.145 ;
      RECT 7.200 151.145 8.400 151.545 ;
      RECT 8.000 143.945 8.400 151.145 ;
      RECT 8.800 151.145 10.000 151.545 ;
      RECT 9.600 143.945 10.000 151.145 ;
      RECT 10.400 151.145 11.600 151.545 ;
      RECT 11.200 143.945 11.600 151.145 ;
      RECT 12.000 151.145 13.200 151.545 ;
      RECT 12.800 143.945 13.200 151.145 ;
      RECT 13.600 151.145 14.800 151.545 ;
      RECT 14.400 143.945 14.800 151.145 ;
      RECT 16.400 143.545 20.000 143.945 ;
      RECT 19.400 138.995 19.800 143.545 ;
      RECT 1.300 138.995 19.400 139.495 ;
      RECT 15.200 151.145 16.400 151.545 ;
      RECT 16.000 143.545 16.400 151.145 ;
      RECT 40.000 156.045 41.900 156.545 ;
      RECT 37.750 156.045 39.000 156.545 ;
      RECT 39.000 155.795 40.000 156.795 ;
      RECT 2.830 158.545 3.330 159.045 ;
      RECT 2.880 157.045 3.280 158.545 ;
      RECT 1.300 157.045 2.880 157.545 ;
      RECT 6.990 158.545 7.490 159.045 ;
      RECT 7.040 156.045 7.440 158.545 ;
      RECT 1.300 156.045 7.040 156.545 ;
      RECT 29.150 158.545 29.650 159.045 ;
      RECT 29.200 155.045 29.600 158.545 ;
      RECT 1.300 155.045 29.200 155.545 ;
      RECT 33.310 158.545 33.810 159.045 ;
      RECT 33.360 154.045 33.760 158.545 ;
      RECT 1.300 154.045 33.360 154.545 ;
      RECT 40.000 163.945 41.900 164.445 ;
      RECT 37.750 163.945 39.000 164.445 ;
      RECT 39.000 163.695 40.000 164.695 ;
      RECT 7.770 21.955 8.270 22.055 ;
      RECT 7.770 22.355 8.270 22.455 ;
      RECT 7.770 22.055 20.730 22.355 ;
      RECT 20.730 21.955 21.230 22.455 ;
      RECT 4.450 27.695 4.950 27.795 ;
      RECT 4.450 28.095 4.950 28.195 ;
      RECT 4.450 27.795 17.410 28.095 ;
      RECT 17.410 27.695 17.910 28.195 ;
      RECT 7.770 30.095 8.270 30.195 ;
      RECT 7.770 30.495 8.270 30.595 ;
      RECT 7.770 30.195 20.730 30.495 ;
      RECT 20.730 30.095 21.230 30.595 ;
      RECT 4.450 35.835 4.950 35.935 ;
      RECT 4.450 36.235 4.950 36.335 ;
      RECT 4.450 35.935 17.410 36.235 ;
      RECT 17.410 35.835 17.910 36.335 ;
      RECT 7.770 38.235 8.270 38.335 ;
      RECT 7.770 38.635 8.270 38.735 ;
      RECT 7.770 38.335 20.730 38.635 ;
      RECT 20.730 38.235 21.230 38.735 ;
      RECT 4.450 43.975 4.950 44.075 ;
      RECT 4.450 44.375 4.950 44.475 ;
      RECT 4.450 44.075 17.410 44.375 ;
      RECT 17.410 43.975 17.910 44.475 ;
      RECT 7.770 46.375 8.270 46.475 ;
      RECT 7.770 46.775 8.270 46.875 ;
      RECT 7.770 46.475 20.730 46.775 ;
      RECT 20.730 46.375 21.230 46.875 ;
      RECT 1.300 23.605 1.900 23.705 ;
      RECT 1.300 23.705 7.155 24.005 ;
      RECT 7.155 23.605 7.655 24.105 ;
      RECT 1.600 24.105 1.900 26.145 ;
      RECT 1.300 24.005 1.900 24.105 ;
      RECT 1.450 26.145 18.025 26.445 ;
      RECT 18.025 26.045 18.525 26.545 ;
      RECT 1.600 26.445 1.900 31.845 ;
      RECT 1.450 31.845 7.155 32.145 ;
      RECT 7.155 31.745 7.655 32.245 ;
      RECT 1.600 32.145 1.900 34.285 ;
      RECT 1.450 34.285 18.025 34.585 ;
      RECT 18.025 34.185 18.525 34.685 ;
      RECT 1.600 34.585 1.900 39.985 ;
      RECT 1.450 39.985 7.155 40.285 ;
      RECT 7.155 39.885 7.655 40.385 ;
      RECT 1.600 40.285 1.900 42.425 ;
      RECT 1.450 42.425 18.025 42.725 ;
      RECT 18.025 42.325 18.525 42.825 ;
      RECT 1.600 42.725 1.900 48.125 ;
      RECT 1.450 48.125 7.155 48.425 ;
      RECT 7.155 48.025 7.655 48.525 ;
      RECT 1.600 48.425 1.900 50.565 ;
      RECT 1.450 50.565 18.025 50.865 ;
      RECT 18.025 50.465 18.525 50.965 ;
      RECT 4.450 52.115 4.950 52.215 ;
      RECT 4.450 52.515 4.950 52.615 ;
      RECT 4.450 52.215 17.410 52.515 ;
      RECT 17.410 52.115 17.910 52.615 ;
      RECT 1.300 54.980 5.190 55.480 ;
      RECT 40.000 62.760 41.900 63.260 ;
      RECT 37.750 62.760 39.000 63.260 ;
      RECT 39.000 62.510 40.000 63.510 ;
      RECT 2.830 65.260 3.330 65.760 ;
      RECT 2.880 63.760 3.280 65.260 ;
      RECT 1.300 63.760 2.880 64.260 ;
      RECT 6.990 65.260 7.490 65.760 ;
      RECT 7.040 62.760 7.440 65.260 ;
      RECT 1.300 62.760 7.040 63.260 ;
      RECT 19.150 65.260 19.650 65.760 ;
      RECT 19.200 61.760 19.600 65.260 ;
      RECT 1.300 61.760 19.200 62.260 ;
      RECT 23.310 65.260 23.810 65.760 ;
      RECT 23.360 60.760 23.760 65.260 ;
      RECT 1.300 60.760 23.360 61.260 ;
      RECT 40.000 70.660 41.900 71.160 ;
      RECT 37.750 70.660 39.000 71.160 ;
      RECT 39.000 70.410 40.000 71.410 ;
      RECT 2.830 73.160 3.330 73.660 ;
      RECT 2.880 71.660 3.280 73.160 ;
      RECT 1.300 71.660 2.880 72.160 ;
      RECT 6.990 73.160 7.490 73.660 ;
      RECT 7.040 70.660 7.440 73.160 ;
      RECT 1.300 70.660 7.040 71.160 ;
      RECT 19.150 73.160 19.650 73.660 ;
      RECT 19.200 69.660 19.600 73.160 ;
      RECT 1.300 69.660 19.200 70.160 ;
      RECT 23.310 73.160 23.810 73.660 ;
      RECT 23.360 68.660 23.760 73.160 ;
      RECT 1.300 68.660 23.360 69.160 ;
      RECT 1.300 6.215 1.750 6.715 ;
      RECT 40.000 78.815 41.900 79.315 ;
      RECT 37.750 78.815 39.000 79.315 ;
      RECT 39.000 78.565 40.000 79.565 ;
      RECT 2.830 81.315 3.330 81.815 ;
      RECT 2.880 79.815 3.280 81.315 ;
      RECT 1.300 79.815 2.880 80.315 ;
      RECT 6.990 81.315 7.490 81.815 ;
      RECT 7.040 78.815 7.440 81.315 ;
      RECT 1.300 78.815 7.040 79.315 ;
      RECT 19.150 81.315 19.650 81.815 ;
      RECT 19.200 77.815 19.600 81.315 ;
      RECT 1.300 77.815 19.200 78.315 ;
      RECT 23.310 81.315 23.810 81.815 ;
      RECT 23.360 76.815 23.760 81.315 ;
      RECT 1.300 76.815 23.360 77.315 ;
      RECT 40.000 86.715 41.900 87.215 ;
      RECT 37.750 86.715 39.000 87.215 ;
      RECT 39.000 86.465 40.000 87.465 ;
      RECT 2.830 89.215 3.330 89.715 ;
      RECT 2.880 87.715 3.280 89.215 ;
      RECT 1.300 87.715 2.880 88.215 ;
      RECT 6.990 89.215 7.490 89.715 ;
      RECT 7.040 86.715 7.440 89.215 ;
      RECT 1.300 86.715 7.040 87.215 ;
      RECT 19.150 89.215 19.650 89.715 ;
      RECT 19.200 85.715 19.600 89.215 ;
      RECT 1.300 85.715 19.200 86.215 ;
      RECT 23.310 89.215 23.810 89.715 ;
      RECT 23.360 84.715 23.760 89.215 ;
      RECT 1.300 84.715 23.360 85.215 ;
      RECT 40.000 94.870 41.900 95.370 ;
      RECT 37.750 94.870 39.000 95.370 ;
      RECT 39.000 94.620 40.000 95.620 ;
      RECT 2.000 97.370 2.500 97.870 ;
      RECT 2.050 96.370 2.450 97.370 ;
      RECT 1.300 95.870 2.450 96.370 ;
      RECT 4.500 97.370 5.000 97.870 ;
      RECT 4.550 94.870 4.950 97.370 ;
      RECT 1.300 94.870 4.550 95.370 ;
      RECT 15.000 97.370 15.500 97.870 ;
      RECT 15.050 93.870 15.450 97.370 ;
      RECT 1.300 93.870 15.050 94.370 ;
      RECT 17.500 97.370 18.000 97.870 ;
      RECT 17.550 92.870 17.950 97.370 ;
      RECT 1.300 92.870 17.550 93.370 ;
      RECT 40.000 102.745 41.900 103.245 ;
      RECT 37.750 102.745 39.000 103.245 ;
      RECT 39.000 102.495 40.000 103.495 ;
      RECT 35.450 6.475 39.000 6.975 ;
      RECT 40.000 6.475 41.900 6.975 ;
      RECT 39.000 6.225 40.000 7.225 ;
      RECT 2.000 105.245 2.500 105.745 ;
      RECT 2.050 104.245 2.450 105.245 ;
      RECT 1.300 103.745 2.450 104.245 ;
      RECT 4.500 105.245 5.000 105.745 ;
      RECT 4.550 102.745 4.950 105.245 ;
      RECT 1.300 102.745 4.550 103.245 ;
      RECT 15.000 105.245 15.500 105.745 ;
      RECT 15.050 101.745 15.450 105.245 ;
      RECT 1.300 101.745 15.050 102.245 ;
      RECT 17.500 105.245 18.000 105.745 ;
      RECT 17.550 100.745 17.950 105.245 ;
      RECT 1.300 100.745 17.550 101.245 ;
      RECT 19.050 105.245 39.000 105.745 ;
      RECT 40.000 105.245 43.900 105.745 ;
      RECT 39.000 104.995 40.000 105.995 ;
      RECT 45.100 47.235 78.500 47.735 ;
      RECT 79.500 47.235 82.050 47.735 ;
      RECT 78.500 46.985 79.500 47.985 ;
      RECT 45.100 89.760 74.000 90.260 ;
      RECT 75.000 89.760 76.420 90.260 ;
      RECT 74.000 89.510 75.000 90.510 ;
      RECT 45.100 60.500 74.000 61.000 ;
      RECT 75.000 60.500 76.420 61.000 ;
      RECT 74.000 60.250 75.000 61.250 ;
      RECT 45.100 22.035 78.500 22.535 ;
      RECT 79.500 22.035 82.050 22.535 ;
      RECT 78.500 21.785 79.500 22.785 ;
      RECT 45.100 5.235 78.500 5.735 ;
      RECT 79.500 5.235 82.050 5.735 ;
      RECT 78.500 4.985 79.500 5.985 ;
      RECT 45.100 30.435 78.500 30.935 ;
      RECT 79.500 30.435 82.050 30.935 ;
      RECT 78.500 30.185 79.500 31.185 ;
      RECT 65.135 138.305 66.115 138.635 ;
      RECT 65.135 138.955 66.115 139.285 ;
      RECT 65.135 139.605 66.115 139.935 ;
      RECT 65.135 140.255 66.115 140.585 ;
      RECT 45.100 144.305 78.500 144.805 ;
      RECT 79.500 144.305 82.050 144.805 ;
      RECT 78.500 144.055 79.500 145.055 ;
      RECT 45.100 152.705 78.500 153.205 ;
      RECT 79.500 152.705 82.050 153.205 ;
      RECT 78.500 152.455 79.500 153.455 ;
      RECT 45.100 38.835 78.500 39.335 ;
      RECT 79.500 38.835 82.050 39.335 ;
      RECT 78.500 38.585 79.500 39.585 ;
      RECT 45.100 13.635 78.500 14.135 ;
      RECT 79.500 13.635 82.050 14.135 ;
      RECT 78.500 13.385 79.500 14.385 ;
      RECT 77.850 87.760 86.700 88.260 ;
      RECT 84.250 115.070 86.700 115.570 ;
      RECT 84.250 118.320 86.700 118.820 ;
      RECT 84.250 120.120 86.700 120.620 ;
      RECT 84.250 123.370 86.700 123.870 ;
      RECT 84.250 125.170 86.700 125.670 ;
      RECT 84.250 128.720 86.700 129.220 ;
      RECT 84.250 130.220 86.700 130.720 ;
      RECT 84.250 133.470 86.700 133.970 ;
      RECT 84.250 134.970 86.700 135.470 ;
      RECT 80.250 85.760 86.700 86.260 ;
      RECT 66.435 138.305 67.415 138.635 ;
      RECT 67.735 138.305 68.715 138.635 ;
      RECT 69.035 138.305 70.015 138.635 ;
      RECT 70.335 138.305 71.315 138.635 ;
      RECT 71.635 138.305 72.615 138.635 ;
      RECT 72.935 138.305 73.915 138.635 ;
      RECT 74.235 138.305 75.215 138.635 ;
      RECT 75.535 138.305 76.515 138.635 ;
      RECT 76.835 138.305 77.815 138.635 ;
      RECT 78.135 138.305 79.115 138.635 ;
      RECT 79.435 138.305 80.415 138.635 ;
      RECT 80.735 138.305 81.715 138.635 ;
      RECT 82.035 138.305 83.015 138.635 ;
      RECT 83.335 138.305 84.250 138.635 ;
      RECT 84.250 138.220 86.700 138.720 ;
      RECT 82.650 106.020 86.700 106.520 ;
      RECT 66.435 138.955 67.415 139.285 ;
      RECT 67.735 138.955 68.715 139.285 ;
      RECT 69.035 138.955 70.015 139.285 ;
      RECT 70.335 138.955 71.315 139.285 ;
      RECT 71.635 138.955 72.615 139.285 ;
      RECT 72.935 138.955 73.915 139.285 ;
      RECT 74.235 138.955 75.215 139.285 ;
      RECT 75.535 138.955 76.515 139.285 ;
      RECT 76.835 138.955 77.815 139.285 ;
      RECT 78.135 138.955 79.115 139.285 ;
      RECT 79.435 138.955 80.415 139.285 ;
      RECT 80.735 138.955 81.715 139.285 ;
      RECT 82.035 138.955 83.015 139.285 ;
      RECT 82.050 107.020 86.700 107.520 ;
      RECT 66.435 139.605 67.415 139.935 ;
      RECT 67.735 139.605 68.715 139.935 ;
      RECT 69.035 139.605 70.015 139.935 ;
      RECT 70.335 139.605 71.315 139.935 ;
      RECT 71.635 139.605 72.615 139.935 ;
      RECT 72.935 139.605 73.915 139.935 ;
      RECT 74.235 139.605 75.215 139.935 ;
      RECT 75.535 139.605 76.515 139.935 ;
      RECT 76.835 139.605 77.815 139.935 ;
      RECT 78.135 139.605 79.115 139.935 ;
      RECT 79.435 139.605 80.415 139.935 ;
      RECT 80.735 139.605 81.715 139.935 ;
      RECT 82.035 139.605 83.015 139.935 ;
      RECT 83.335 138.955 83.665 139.935 ;
      RECT 80.850 108.020 86.700 108.520 ;
      RECT 66.435 140.255 67.415 140.585 ;
      RECT 67.735 140.255 68.715 140.585 ;
      RECT 69.035 140.255 70.015 140.585 ;
      RECT 70.335 140.255 71.315 140.585 ;
      RECT 71.635 140.255 72.615 140.585 ;
      RECT 72.935 140.255 73.915 140.585 ;
      RECT 74.235 140.255 75.215 140.585 ;
      RECT 75.535 140.255 76.515 140.585 ;
      RECT 76.835 140.255 77.815 140.585 ;
      RECT 78.135 140.255 79.115 140.585 ;
      RECT 79.435 140.255 80.415 140.585 ;
      RECT 80.735 140.255 81.715 140.585 ;
      RECT 82.035 140.255 83.015 140.585 ;
      RECT 83.335 140.255 84.250 140.585 ;
      RECT 84.250 140.170 86.700 140.670 ;
      RECT 80.245 143.170 86.700 143.670 ;
      RECT 79.050 109.020 86.700 109.520 ;
      RECT 84.300 145.360 86.700 145.860 ;
      RECT 82.060 148.570 86.700 149.070 ;
      RECT 80.245 151.570 86.700 152.070 ;
      RECT 78.450 110.020 86.700 110.520 ;
      RECT 84.300 153.760 86.700 154.260 ;
      RECT 82.060 156.970 86.700 157.470 ;
      RECT 79.650 86.760 86.700 87.260 ;
      RECT 84.250 113.270 86.700 113.770 ;
      RECT 83.250 159.970 86.700 160.470 ;
      RECT 81.450 160.970 86.700 161.470 ;
      RECT 80.250 161.970 86.700 162.470 ;
      RECT 79.650 162.970 86.700 163.470 ;
      RECT 77.850 163.970 86.700 164.470 ;
      RECT 81.450 84.760 86.700 85.260 ;
      RECT 59.935 138.955 60.915 139.285 ;
      RECT 61.235 138.955 62.215 139.285 ;
      RECT 62.535 138.955 63.515 139.285 ;
      RECT 63.835 138.955 64.815 139.285 ;
      RECT 45.100 128.720 48.000 129.220 ;
      RECT 49.000 128.720 50.250 129.220 ;
      RECT 48.000 128.470 49.000 129.470 ;
      RECT 45.100 123.370 48.000 123.870 ;
      RECT 49.000 123.370 50.250 123.870 ;
      RECT 48.000 123.120 49.000 124.120 ;
      RECT 51.485 139.605 51.815 140.585 ;
      RECT 52.135 140.255 53.115 140.585 ;
      RECT 53.435 140.255 54.415 140.585 ;
      RECT 54.735 140.255 55.715 140.585 ;
      RECT 56.035 140.255 57.015 140.585 ;
      RECT 57.335 140.255 58.315 140.585 ;
      RECT 58.635 140.255 59.615 140.585 ;
      RECT 59.935 140.255 60.915 140.585 ;
      RECT 61.235 140.255 62.215 140.585 ;
      RECT 62.535 140.255 63.515 140.585 ;
      RECT 63.835 140.255 64.815 140.585 ;
      RECT 45.100 113.270 48.000 113.770 ;
      RECT 49.000 113.270 50.250 113.770 ;
      RECT 48.000 113.020 49.000 114.020 ;
      RECT 45.100 133.470 48.000 133.970 ;
      RECT 49.000 133.470 50.250 133.970 ;
      RECT 48.000 133.220 49.000 134.220 ;
      RECT 45.100 118.320 48.000 118.820 ;
      RECT 49.000 118.320 50.250 118.820 ;
      RECT 48.000 118.070 49.000 119.070 ;
      RECT 52.135 138.305 53.115 138.635 ;
      RECT 53.435 138.305 54.415 138.635 ;
      RECT 54.735 138.305 55.715 138.635 ;
      RECT 56.035 138.305 57.015 138.635 ;
      RECT 57.335 138.305 58.315 138.635 ;
      RECT 58.635 138.305 59.615 138.635 ;
      RECT 59.935 138.305 60.915 138.635 ;
      RECT 61.235 138.305 62.215 138.635 ;
      RECT 62.535 138.305 63.515 138.635 ;
      RECT 52.135 139.605 53.115 139.935 ;
      RECT 53.435 139.605 54.415 139.935 ;
      RECT 54.735 139.605 55.715 139.935 ;
      RECT 56.035 139.605 57.015 139.935 ;
      RECT 57.335 139.605 58.315 139.935 ;
      RECT 58.635 139.605 59.615 139.935 ;
      RECT 59.935 139.605 60.915 139.935 ;
      RECT 61.235 139.605 62.215 139.935 ;
      RECT 62.535 139.605 63.515 139.935 ;
      RECT 63.835 139.605 64.815 139.935 ;
      RECT 63.835 138.305 64.815 138.635 ;
      RECT 45.100 138.220 48.000 138.720 ;
      RECT 49.000 138.220 50.250 138.720 ;
      RECT 48.000 137.970 49.000 138.970 ;
      RECT 51.485 138.305 51.815 139.285 ;
      RECT 52.135 138.955 53.115 139.285 ;
      RECT 53.435 138.955 54.415 139.285 ;
      RECT 54.735 138.955 55.715 139.285 ;
      RECT 56.035 138.955 57.015 139.285 ;
      RECT 57.335 138.955 58.315 139.285 ;
      RECT 58.635 138.955 59.615 139.285 ;
      RECT 79.650 57.500 86.700 58.000 ;
      RECT 77.850 58.500 86.700 59.000 ;
      RECT 80.245 46.100 86.700 46.600 ;
      RECT 84.300 48.290 86.700 48.790 ;
      RECT 84.300 23.090 86.700 23.590 ;
      RECT 82.060 26.300 86.700 26.800 ;
      RECT 82.060 17.900 86.700 18.400 ;
      RECT 80.245 12.500 86.700 13.000 ;
      RECT 84.300 14.690 86.700 15.190 ;
      RECT 82.060 34.700 86.700 35.200 ;
      RECT 80.245 4.100 86.700 4.600 ;
      RECT 80.245 37.700 86.700 38.200 ;
      RECT 79.050 79.760 86.700 80.260 ;
      RECT 82.650 76.760 86.700 77.260 ;
      RECT 82.050 77.760 86.700 78.260 ;
      RECT 80.850 78.760 86.700 79.260 ;
      RECT 78.450 80.760 86.700 81.260 ;
      RECT 82.060 51.500 86.700 52.000 ;
      RECT 80.245 20.900 86.700 21.400 ;
      RECT 84.300 39.890 86.700 40.390 ;
      RECT 82.060 43.100 86.700 43.600 ;
      RECT 83.250 54.500 86.700 55.000 ;
      RECT 84.300 6.290 86.700 6.790 ;
      RECT 81.450 55.500 86.700 56.000 ;
      RECT 80.245 29.300 86.700 29.800 ;
      RECT 82.060 9.500 86.700 10.000 ;
      RECT 80.250 56.500 86.700 57.000 ;
      RECT 83.250 83.760 86.700 84.260 ;
      RECT 84.300 31.490 86.700 31.990 ;
  END
END tp_br

END LIBRARY
